# Confidential Information of ARM, Inc.
# Use subject to ARM license.
# Copyright (c) 2025 ARM, Inc.

# ACI Version r1p0

# Reifier 4.0.0

VERSION 5.7 ;

BUSBITCHARS "[]" ;

#name: High Speed Single Port SRAM HVT RVT Compiler | TSMC cln65lp 65nm Process, 0.620um^2 Bit Cell
#version: r1p0
#comment: 
#configuration:  -activity_factor 50 -back_biasing off -bits 32 -bmux off -bus_notation on -check_instname on -diodes on -drive 6 -ema on -frequency 1.0 -instname sp_hse_8192_m16 -left_bus_delim "[" -mux 16 -mvt "" -name_case upper -power_type otc -prefix "" -pwr_gnd_rename vddpe:VDDPE,vddce:VDDCE,vsse:VSSE -retention on -right_bus_delim "]" -rows_p_bl 64 -ser none -site_def off -top_layer m5-m10 -words 8192 -wp_size 1 -write_mask on -write_thru off -corners ff_1p32v_1p32v_125c,ff_1p32v_1p32v_m40c,ss_1p08v_1p08v_125c,ss_1p08v_1p08v_m40c,tt_1p20v_1p20v_25c
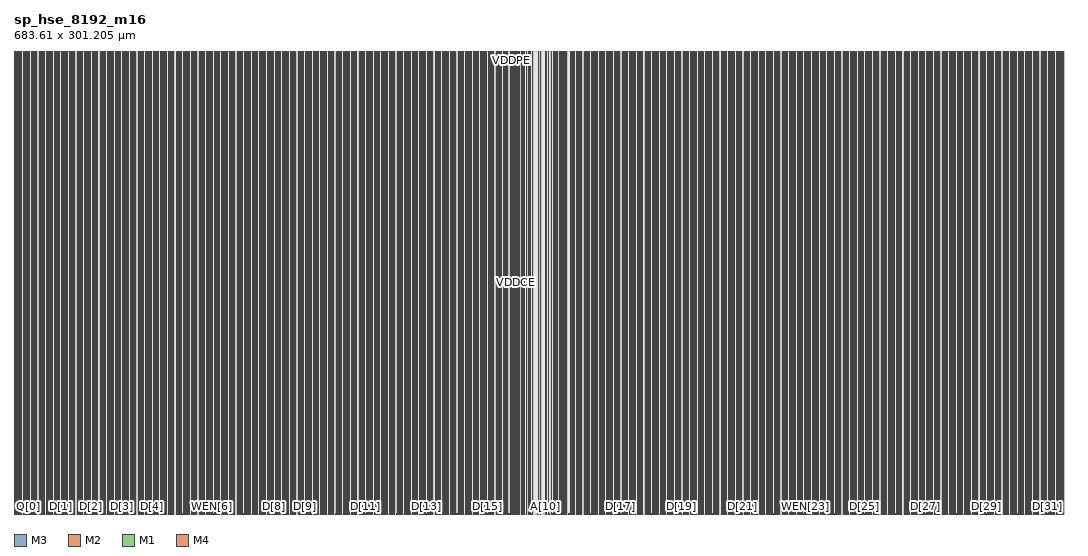
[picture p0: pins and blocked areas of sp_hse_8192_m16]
MACRO sp_hse_8192_m16
  FOREIGN sp_hse_8192_m16 0 0 ;
  SYMMETRY X Y R90 ;
  SIZE 683.61 BY 301.205 ;
  CLASS BLOCK ;
  PIN A[8]
    DIRECTION INPUT ;
    USE SIGNAL ;
    SHAPE ABUTMENT ;
    PORT
      LAYER M3 ;
      RECT 341.26 0.0 341.47 0.38 ;
      LAYER M2 ;
      RECT 341.26 0.0 341.47 0.38 ;
      LAYER M1 ;
      RECT 341.26 0.0 341.47 0.38 ;
      END
    ANTENNAGATEAREA 0.0072 ;
    ANTENNADIFFAREA 0.0737 ;
    END A[8]
  PIN A[9]
    DIRECTION INPUT ;
    USE SIGNAL ;
    SHAPE ABUTMENT ;
    PORT
      LAYER M1 ;
      RECT 345.865 0.0 346.075 0.38 ;
      LAYER M2 ;
      RECT 345.865 0.0 346.075 0.38 ;
      LAYER M3 ;
      RECT 345.865 0.0 346.075 0.38 ;
      END
    ANTENNAGATEAREA 0.0072 ;
    ANTENNADIFFAREA 0.0737 ;
    END A[9]
  PIN A[7]
    DIRECTION INPUT ;
    USE SIGNAL ;
    SHAPE ABUTMENT ;
    PORT
      LAYER M3 ;
      RECT 340.725 0.0 340.935 0.38 ;
      LAYER M2 ;
      RECT 340.725 0.0 340.935 0.38 ;
      LAYER M1 ;
      RECT 340.725 0.0 340.935 0.38 ;
      END
    ANTENNAGATEAREA 0.0072 ;
    ANTENNADIFFAREA 0.0737 ;
    END A[7]
  PIN A[10]
    DIRECTION INPUT ;
    USE SIGNAL ;
    SHAPE ABUTMENT ;
    PORT
      LAYER M1 ;
      RECT 346.245 0.0 346.455 0.38 ;
      LAYER M2 ;
      RECT 346.245 0.0 346.455 0.38 ;
      LAYER M3 ;
      RECT 346.245 0.0 346.455 0.38 ;
      END
    ANTENNAGATEAREA 0.0072 ;
    ANTENNADIFFAREA 0.0737 ;
    END A[10]
  PIN A[6]
    DIRECTION INPUT ;
    USE SIGNAL ;
    SHAPE ABUTMENT ;
    PORT
      LAYER M3 ;
      RECT 336.805 0.0 337.015 0.38 ;
      LAYER M2 ;
      RECT 336.805 0.0 337.015 0.38 ;
      LAYER M1 ;
      RECT 336.805 0.0 337.015 0.38 ;
      END
    ANTENNAGATEAREA 0.0072 ;
    ANTENNADIFFAREA 0.0737 ;
    END A[6]
  PIN A[4]
    DIRECTION INPUT ;
    USE SIGNAL ;
    SHAPE ABUTMENT ;
    PORT
      LAYER M1 ;
      RECT 348.32 0.0 348.53 0.38 ;
      LAYER M2 ;
      RECT 348.32 0.0 348.53 0.38 ;
      LAYER M3 ;
      RECT 348.32 0.0 348.53 0.38 ;
      END
    ANTENNAGATEAREA 0.0072 ;
    ANTENNADIFFAREA 0.0737 ;
    END A[4]
  PIN A[5]
    DIRECTION INPUT ;
    USE SIGNAL ;
    SHAPE ABUTMENT ;
    PORT
      LAYER M3 ;
      RECT 335.97 0.0 336.18 0.38 ;
      LAYER M2 ;
      RECT 335.97 0.0 336.18 0.38 ;
      LAYER M1 ;
      RECT 335.97 0.0 336.18 0.38 ;
      END
    ANTENNAGATEAREA 0.0072 ;
    ANTENNADIFFAREA 0.0737 ;
    END A[5]
  PIN A[11]
    DIRECTION INPUT ;
    USE SIGNAL ;
    SHAPE ABUTMENT ;
    PORT
      LAYER M1 ;
      RECT 350.39 0.0 350.6 0.38 ;
      LAYER M2 ;
      RECT 350.39 0.0 350.6 0.38 ;
      LAYER M3 ;
      RECT 350.39 0.0 350.6 0.38 ;
      END
    ANTENNAGATEAREA 0.0072 ;
    ANTENNADIFFAREA 0.0737 ;
    END A[11]
  PIN GWEN
    DIRECTION INPUT ;
    USE SIGNAL ;
    SHAPE ABUTMENT ;
    PORT
      LAYER M3 ;
      RECT 331.555 0.0 331.765 0.38 ;
      LAYER M2 ;
      RECT 331.555 0.0 331.765 0.38 ;
      LAYER M1 ;
      RECT 331.555 0.0 331.765 0.38 ;
      END
    ANTENNAGATEAREA 0.0072 ;
    ANTENNADIFFAREA 0.0737 ;
    END GWEN
  PIN A[12]
    DIRECTION INPUT ;
    USE SIGNAL ;
    SHAPE ABUTMENT ;
    PORT
      LAYER M1 ;
      RECT 350.985 0.0 351.195 0.38 ;
      LAYER M2 ;
      RECT 350.985 0.0 351.195 0.38 ;
      LAYER M3 ;
      RECT 350.985 0.0 351.195 0.38 ;
      END
    ANTENNAGATEAREA 0.0072 ;
    ANTENNADIFFAREA 0.0737 ;
    END A[12]
  PIN CEN
    DIRECTION INPUT ;
    USE SIGNAL ;
    SHAPE ABUTMENT ;
    PORT
      LAYER M3 ;
      RECT 331.14 0.0 331.35 0.38 ;
      LAYER M2 ;
      RECT 331.14 0.0 331.35 0.38 ;
      LAYER M1 ;
      RECT 331.14 0.0 331.35 0.38 ;
      END
    ANTENNAGATEAREA 0.0072 ;
    ANTENNADIFFAREA 0.0737 ;
    END CEN
  PIN A[3]
    DIRECTION INPUT ;
    USE SIGNAL ;
    SHAPE ABUTMENT ;
    PORT
      LAYER M1 ;
      RECT 354.62 0.0 354.83 0.38 ;
      LAYER M2 ;
      RECT 354.62 0.0 354.83 0.38 ;
      LAYER M3 ;
      RECT 354.62 0.0 354.83 0.38 ;
      END
    ANTENNAGATEAREA 0.0072 ;
    ANTENNADIFFAREA 0.0737 ;
    END A[3]
  PIN CLK
    DIRECTION INPUT ;
    USE SIGNAL ;
    SHAPE ABUTMENT ;
    PORT
      LAYER M4 ;
      RECT 327.685 0.0 327.895 0.38 ;
      LAYER M3 ;
      RECT 327.685 0.0 327.895 0.38 ;
      LAYER M2 ;
      RECT 327.685 0.0 327.895 0.38 ;
      LAYER M1 ;
      RECT 327.685 0.0 327.895 0.38 ;
      END
    ANTENNAGATEAREA 0.0072 ;
    ANTENNADIFFAREA 0.0737 ;
    END CLK
  PIN A[2]
    DIRECTION INPUT ;
    USE SIGNAL ;
    SHAPE ABUTMENT ;
    PORT
      LAYER M1 ;
      RECT 355.8 0.0 356.01 0.38 ;
      LAYER M2 ;
      RECT 355.8 0.0 356.01 0.38 ;
      LAYER M3 ;
      RECT 355.8 0.0 356.01 0.38 ;
      END
    ANTENNAGATEAREA 0.0072 ;
    ANTENNADIFFAREA 0.0737 ;
    END A[2]
  PIN EMAW[1]
    DIRECTION INPUT ;
    USE SIGNAL ;
    SHAPE ABUTMENT ;
    PORT
      LAYER M3 ;
      RECT 326.51 0.0 326.72 0.38 ;
      LAYER M2 ;
      RECT 326.51 0.0 326.72 0.38 ;
      LAYER M1 ;
      RECT 326.51 0.0 326.72 0.38 ;
      END
    ANTENNAGATEAREA 0.0072 ;
    ANTENNADIFFAREA 0.0737 ;
    END EMAW[1]
  PIN A[1]
    DIRECTION INPUT ;
    USE SIGNAL ;
    SHAPE ABUTMENT ;
    PORT
      LAYER M1 ;
      RECT 356.95 0.0 357.16 0.38 ;
      LAYER M2 ;
      RECT 356.95 0.0 357.16 0.38 ;
      LAYER M3 ;
      RECT 356.95 0.0 357.16 0.38 ;
      END
    ANTENNAGATEAREA 0.0072 ;
    ANTENNADIFFAREA 0.0737 ;
    END A[1]
  PIN EMAW[0]
    DIRECTION INPUT ;
    USE SIGNAL ;
    SHAPE ABUTMENT ;
    PORT
      LAYER M3 ;
      RECT 325.285 0.0 325.495 0.38 ;
      LAYER M2 ;
      RECT 325.285 0.0 325.495 0.38 ;
      LAYER M1 ;
      RECT 325.285 0.0 325.495 0.38 ;
      END
    ANTENNAGATEAREA 0.0072 ;
    ANTENNADIFFAREA 0.0737 ;
    END EMAW[0]
  PIN RET1N
    DIRECTION INPUT ;
    USE SIGNAL ;
    SHAPE ABUTMENT ;
    PORT
      LAYER M1 ;
      RECT 358.25 0.0 358.46 0.38 ;
      LAYER M2 ;
      RECT 358.25 0.0 358.46 0.38 ;
      LAYER M3 ;
      RECT 358.25 0.0 358.46 0.38 ;
      END
    ANTENNAGATEAREA 0.0072 ;
    ANTENNADIFFAREA 0.0737 ;
    END RET1N
  PIN EMA[2]
    DIRECTION INPUT ;
    USE SIGNAL ;
    SHAPE ABUTMENT ;
    PORT
      LAYER M3 ;
      RECT 322.23 0.0 322.44 0.38 ;
      LAYER M2 ;
      RECT 322.23 0.0 322.44 0.38 ;
      LAYER M1 ;
      RECT 322.23 0.0 322.44 0.38 ;
      END
    ANTENNAGATEAREA 0.0072 ;
    ANTENNADIFFAREA 0.0737 ;
    END EMA[2]
  PIN EMAS
    DIRECTION INPUT ;
    USE SIGNAL ;
    SHAPE ABUTMENT ;
    PORT
      LAYER M1 ;
      RECT 361.035 0.0 361.245 0.38 ;
      LAYER M2 ;
      RECT 361.035 0.0 361.245 0.38 ;
      LAYER M3 ;
      RECT 361.035 0.0 361.245 0.38 ;
      END
    ANTENNAGATEAREA 0.0072 ;
    ANTENNADIFFAREA 0.0737 ;
    END EMAS
  PIN EMA[1]
    DIRECTION INPUT ;
    USE SIGNAL ;
    SHAPE ABUTMENT ;
    PORT
      LAYER M3 ;
      RECT 321.84 0.0 322.05 0.38 ;
      LAYER M2 ;
      RECT 321.84 0.0 322.05 0.38 ;
      LAYER M1 ;
      RECT 321.84 0.0 322.05 0.38 ;
      END
    ANTENNAGATEAREA 0.0072 ;
    ANTENNADIFFAREA 0.0737 ;
    END EMA[1]
  PIN A[0]
    DIRECTION INPUT ;
    USE SIGNAL ;
    SHAPE ABUTMENT ;
    PORT
      LAYER M1 ;
      RECT 361.455 0.0 361.665 0.38 ;
      LAYER M2 ;
      RECT 361.455 0.0 361.665 0.38 ;
      LAYER M3 ;
      RECT 361.455 0.0 361.665 0.38 ;
      END
    ANTENNAGATEAREA 0.0072 ;
    ANTENNADIFFAREA 0.0737 ;
    END A[0]
  PIN EMA[0]
    DIRECTION INPUT ;
    USE SIGNAL ;
    SHAPE ABUTMENT ;
    PORT
      LAYER M3 ;
      RECT 321.48 0.0 321.69 0.38 ;
      LAYER M2 ;
      RECT 321.48 0.0 321.69 0.38 ;
      LAYER M1 ;
      RECT 321.48 0.0 321.69 0.38 ;
      END
    ANTENNAGATEAREA 0.0072 ;
    ANTENNADIFFAREA 0.0737 ;
    END EMA[0]
  PIN D[16]
    DIRECTION INPUT ;
    USE SIGNAL ;
    SHAPE ABUTMENT ;
    PORT
      LAYER M1 ;
      RECT 375.155 0.0 375.365 0.38 ;
      LAYER M2 ;
      RECT 375.155 0.0 375.365 0.38 ;
      LAYER M3 ;
      RECT 375.155 0.0 375.365 0.38 ;
      END
    ANTENNAGATEAREA 0.0072 ;
    ANTENNADIFFAREA 0.0737 ;
    END D[16]
  PIN D[15]
    DIRECTION INPUT ;
    USE SIGNAL ;
    SHAPE ABUTMENT ;
    PORT
      LAYER M3 ;
      RECT 308.245 0.0 308.455 0.38 ;
      LAYER M2 ;
      RECT 308.245 0.0 308.455 0.38 ;
      LAYER M1 ;
      RECT 308.245 0.0 308.455 0.38 ;
      END
    ANTENNAGATEAREA 0.0072 ;
    ANTENNADIFFAREA 0.0737 ;
    END D[15]
  PIN WEN[16]
    DIRECTION INPUT ;
    USE SIGNAL ;
    SHAPE ABUTMENT ;
    PORT
      LAYER M1 ;
      RECT 376.195 0.0 376.405 0.38 ;
      LAYER M2 ;
      RECT 376.195 0.0 376.405 0.38 ;
      LAYER M3 ;
      RECT 376.195 0.0 376.405 0.38 ;
      END
    ANTENNAGATEAREA 0.0072 ;
    ANTENNADIFFAREA 0.0737 ;
    END WEN[16]
  PIN WEN[15]
    DIRECTION INPUT ;
    USE SIGNAL ;
    SHAPE ABUTMENT ;
    PORT
      LAYER M3 ;
      RECT 307.205 0.0 307.415 0.38 ;
      LAYER M2 ;
      RECT 307.205 0.0 307.415 0.38 ;
      LAYER M1 ;
      RECT 307.205 0.0 307.415 0.38 ;
      END
    ANTENNAGATEAREA 0.0072 ;
    ANTENNADIFFAREA 0.0737 ;
    END WEN[15]
  PIN Q[16]
    DIRECTION OUTPUT ;
    USE SIGNAL ;
    SHAPE ABUTMENT ;
    PORT
      LAYER M1 ;
      RECT 376.545 0.0 376.755 0.38 ;
      LAYER M2 ;
      RECT 376.545 0.0 376.755 0.38 ;
      LAYER M3 ;
      RECT 376.545 0.0 376.755 0.38 ;
      END
    ANTENNADIFFAREA 0.0737 ;
    END Q[16]
  PIN Q[15]
    DIRECTION OUTPUT ;
    USE SIGNAL ;
    SHAPE ABUTMENT ;
    PORT
      LAYER M3 ;
      RECT 306.855 0.0 307.065 0.38 ;
      LAYER M2 ;
      RECT 306.855 0.0 307.065 0.38 ;
      LAYER M1 ;
      RECT 306.855 0.0 307.065 0.38 ;
      END
    ANTENNADIFFAREA 0.0737 ;
    END Q[15]
  PIN D[17]
    DIRECTION INPUT ;
    USE SIGNAL ;
    SHAPE ABUTMENT ;
    PORT
      LAYER M1 ;
      RECT 394.995 0.0 395.205 0.38 ;
      LAYER M2 ;
      RECT 394.995 0.0 395.205 0.38 ;
      LAYER M3 ;
      RECT 394.995 0.0 395.205 0.38 ;
      END
    ANTENNAGATEAREA 0.0072 ;
    ANTENNADIFFAREA 0.0737 ;
    END D[17]
  PIN D[14]
    DIRECTION INPUT ;
    USE SIGNAL ;
    SHAPE ABUTMENT ;
    PORT
      LAYER M3 ;
      RECT 288.405 0.0 288.615 0.38 ;
      LAYER M2 ;
      RECT 288.405 0.0 288.615 0.38 ;
      LAYER M1 ;
      RECT 288.405 0.0 288.615 0.38 ;
      END
    ANTENNAGATEAREA 0.0072 ;
    ANTENNADIFFAREA 0.0737 ;
    END D[14]
  PIN WEN[17]
    DIRECTION INPUT ;
    USE SIGNAL ;
    SHAPE ABUTMENT ;
    PORT
      LAYER M1 ;
      RECT 396.035 0.0 396.245 0.38 ;
      LAYER M2 ;
      RECT 396.035 0.0 396.245 0.38 ;
      LAYER M3 ;
      RECT 396.035 0.0 396.245 0.38 ;
      END
    ANTENNAGATEAREA 0.0072 ;
    ANTENNADIFFAREA 0.0737 ;
    END WEN[17]
  PIN WEN[14]
    DIRECTION INPUT ;
    USE SIGNAL ;
    SHAPE ABUTMENT ;
    PORT
      LAYER M3 ;
      RECT 287.365 0.0 287.575 0.38 ;
      LAYER M2 ;
      RECT 287.365 0.0 287.575 0.38 ;
      LAYER M1 ;
      RECT 287.365 0.0 287.575 0.38 ;
      END
    ANTENNAGATEAREA 0.0072 ;
    ANTENNADIFFAREA 0.0737 ;
    END WEN[14]
  PIN Q[17]
    DIRECTION OUTPUT ;
    USE SIGNAL ;
    SHAPE ABUTMENT ;
    PORT
      LAYER M1 ;
      RECT 396.385 0.0 396.595 0.38 ;
      LAYER M2 ;
      RECT 396.385 0.0 396.595 0.38 ;
      LAYER M3 ;
      RECT 396.385 0.0 396.595 0.38 ;
      END
    ANTENNADIFFAREA 0.0737 ;
    END Q[17]
  PIN Q[14]
    DIRECTION OUTPUT ;
    USE SIGNAL ;
    SHAPE ABUTMENT ;
    PORT
      LAYER M3 ;
      RECT 287.015 0.0 287.225 0.38 ;
      LAYER M2 ;
      RECT 287.015 0.0 287.225 0.38 ;
      LAYER M1 ;
      RECT 287.015 0.0 287.225 0.38 ;
      END
    ANTENNADIFFAREA 0.0737 ;
    END Q[14]
  PIN D[18]
    DIRECTION INPUT ;
    USE SIGNAL ;
    SHAPE ABUTMENT ;
    PORT
      LAYER M1 ;
      RECT 414.835 0.0 415.045 0.38 ;
      LAYER M2 ;
      RECT 414.835 0.0 415.045 0.38 ;
      LAYER M3 ;
      RECT 414.835 0.0 415.045 0.38 ;
      END
    ANTENNAGATEAREA 0.0072 ;
    ANTENNADIFFAREA 0.0737 ;
    END D[18]
  PIN D[13]
    DIRECTION INPUT ;
    USE SIGNAL ;
    SHAPE ABUTMENT ;
    PORT
      LAYER M3 ;
      RECT 268.565 0.0 268.775 0.38 ;
      LAYER M2 ;
      RECT 268.565 0.0 268.775 0.38 ;
      LAYER M1 ;
      RECT 268.565 0.0 268.775 0.38 ;
      END
    ANTENNAGATEAREA 0.0072 ;
    ANTENNADIFFAREA 0.0737 ;
    END D[13]
  PIN WEN[18]
    DIRECTION INPUT ;
    USE SIGNAL ;
    SHAPE ABUTMENT ;
    PORT
      LAYER M1 ;
      RECT 415.875 0.0 416.085 0.38 ;
      LAYER M2 ;
      RECT 415.875 0.0 416.085 0.38 ;
      LAYER M3 ;
      RECT 415.875 0.0 416.085 0.38 ;
      END
    ANTENNAGATEAREA 0.0072 ;
    ANTENNADIFFAREA 0.0737 ;
    END WEN[18]
  PIN WEN[13]
    DIRECTION INPUT ;
    USE SIGNAL ;
    SHAPE ABUTMENT ;
    PORT
      LAYER M3 ;
      RECT 267.525 0.0 267.735 0.38 ;
      LAYER M2 ;
      RECT 267.525 0.0 267.735 0.38 ;
      LAYER M1 ;
      RECT 267.525 0.0 267.735 0.38 ;
      END
    ANTENNAGATEAREA 0.0072 ;
    ANTENNADIFFAREA 0.0737 ;
    END WEN[13]
  PIN Q[18]
    DIRECTION OUTPUT ;
    USE SIGNAL ;
    SHAPE ABUTMENT ;
    PORT
      LAYER M1 ;
      RECT 416.225 0.0 416.435 0.38 ;
      LAYER M2 ;
      RECT 416.225 0.0 416.435 0.38 ;
      LAYER M3 ;
      RECT 416.225 0.0 416.435 0.38 ;
      END
    ANTENNADIFFAREA 0.0737 ;
    END Q[18]
  PIN Q[13]
    DIRECTION OUTPUT ;
    USE SIGNAL ;
    SHAPE ABUTMENT ;
    PORT
      LAYER M3 ;
      RECT 267.175 0.0 267.385 0.38 ;
      LAYER M2 ;
      RECT 267.175 0.0 267.385 0.38 ;
      LAYER M1 ;
      RECT 267.175 0.0 267.385 0.38 ;
      END
    ANTENNADIFFAREA 0.0737 ;
    END Q[13]
  PIN D[19]
    DIRECTION INPUT ;
    USE SIGNAL ;
    SHAPE ABUTMENT ;
    PORT
      LAYER M1 ;
      RECT 434.675 0.0 434.885 0.38 ;
      LAYER M2 ;
      RECT 434.675 0.0 434.885 0.38 ;
      LAYER M3 ;
      RECT 434.675 0.0 434.885 0.38 ;
      END
    ANTENNAGATEAREA 0.0072 ;
    ANTENNADIFFAREA 0.0737 ;
    END D[19]
  PIN D[12]
    DIRECTION INPUT ;
    USE SIGNAL ;
    SHAPE ABUTMENT ;
    PORT
      LAYER M3 ;
      RECT 248.725 0.0 248.935 0.38 ;
      LAYER M2 ;
      RECT 248.725 0.0 248.935 0.38 ;
      LAYER M1 ;
      RECT 248.725 0.0 248.935 0.38 ;
      END
    ANTENNAGATEAREA 0.0072 ;
    ANTENNADIFFAREA 0.0737 ;
    END D[12]
  PIN WEN[19]
    DIRECTION INPUT ;
    USE SIGNAL ;
    SHAPE ABUTMENT ;
    PORT
      LAYER M1 ;
      RECT 435.715 0.0 435.925 0.38 ;
      LAYER M2 ;
      RECT 435.715 0.0 435.925 0.38 ;
      LAYER M3 ;
      RECT 435.715 0.0 435.925 0.38 ;
      END
    ANTENNAGATEAREA 0.0072 ;
    ANTENNADIFFAREA 0.0737 ;
    END WEN[19]
  PIN WEN[12]
    DIRECTION INPUT ;
    USE SIGNAL ;
    SHAPE ABUTMENT ;
    PORT
      LAYER M3 ;
      RECT 247.685 0.0 247.895 0.38 ;
      LAYER M2 ;
      RECT 247.685 0.0 247.895 0.38 ;
      LAYER M1 ;
      RECT 247.685 0.0 247.895 0.38 ;
      END
    ANTENNAGATEAREA 0.0072 ;
    ANTENNADIFFAREA 0.0737 ;
    END WEN[12]
  PIN Q[19]
    DIRECTION OUTPUT ;
    USE SIGNAL ;
    SHAPE ABUTMENT ;
    PORT
      LAYER M1 ;
      RECT 436.065 0.0 436.275 0.38 ;
      LAYER M2 ;
      RECT 436.065 0.0 436.275 0.38 ;
      LAYER M3 ;
      RECT 436.065 0.0 436.275 0.38 ;
      END
    ANTENNADIFFAREA 0.0737 ;
    END Q[19]
  PIN Q[12]
    DIRECTION OUTPUT ;
    USE SIGNAL ;
    SHAPE ABUTMENT ;
    PORT
      LAYER M3 ;
      RECT 247.335 0.0 247.545 0.38 ;
      LAYER M2 ;
      RECT 247.335 0.0 247.545 0.38 ;
      LAYER M1 ;
      RECT 247.335 0.0 247.545 0.38 ;
      END
    ANTENNADIFFAREA 0.0737 ;
    END Q[12]
  PIN D[20]
    DIRECTION INPUT ;
    USE SIGNAL ;
    SHAPE ABUTMENT ;
    PORT
      LAYER M1 ;
      RECT 454.515 0.0 454.725 0.38 ;
      LAYER M2 ;
      RECT 454.515 0.0 454.725 0.38 ;
      LAYER M3 ;
      RECT 454.515 0.0 454.725 0.38 ;
      END
    ANTENNAGATEAREA 0.0072 ;
    ANTENNADIFFAREA 0.0737 ;
    END D[20]
  PIN D[11]
    DIRECTION INPUT ;
    USE SIGNAL ;
    SHAPE ABUTMENT ;
    PORT
      LAYER M3 ;
      RECT 228.885 0.0 229.095 0.38 ;
      LAYER M2 ;
      RECT 228.885 0.0 229.095 0.38 ;
      LAYER M1 ;
      RECT 228.885 0.0 229.095 0.38 ;
      END
    ANTENNAGATEAREA 0.0072 ;
    ANTENNADIFFAREA 0.0737 ;
    END D[11]
  PIN WEN[20]
    DIRECTION INPUT ;
    USE SIGNAL ;
    SHAPE ABUTMENT ;
    PORT
      LAYER M1 ;
      RECT 455.555 0.0 455.765 0.38 ;
      LAYER M2 ;
      RECT 455.555 0.0 455.765 0.38 ;
      LAYER M3 ;
      RECT 455.555 0.0 455.765 0.38 ;
      END
    ANTENNAGATEAREA 0.0072 ;
    ANTENNADIFFAREA 0.0737 ;
    END WEN[20]
  PIN WEN[11]
    DIRECTION INPUT ;
    USE SIGNAL ;
    SHAPE ABUTMENT ;
    PORT
      LAYER M3 ;
      RECT 227.845 0.0 228.055 0.38 ;
      LAYER M2 ;
      RECT 227.845 0.0 228.055 0.38 ;
      LAYER M1 ;
      RECT 227.845 0.0 228.055 0.38 ;
      END
    ANTENNAGATEAREA 0.0072 ;
    ANTENNADIFFAREA 0.0737 ;
    END WEN[11]
  PIN Q[20]
    DIRECTION OUTPUT ;
    USE SIGNAL ;
    SHAPE ABUTMENT ;
    PORT
      LAYER M1 ;
      RECT 455.905 0.0 456.115 0.38 ;
      LAYER M2 ;
      RECT 455.905 0.0 456.115 0.38 ;
      LAYER M3 ;
      RECT 455.905 0.0 456.115 0.38 ;
      END
    ANTENNADIFFAREA 0.0737 ;
    END Q[20]
  PIN Q[11]
    DIRECTION OUTPUT ;
    USE SIGNAL ;
    SHAPE ABUTMENT ;
    PORT
      LAYER M3 ;
      RECT 227.495 0.0 227.705 0.38 ;
      LAYER M2 ;
      RECT 227.495 0.0 227.705 0.38 ;
      LAYER M1 ;
      RECT 227.495 0.0 227.705 0.38 ;
      END
    ANTENNADIFFAREA 0.0737 ;
    END Q[11]
  PIN D[21]
    DIRECTION INPUT ;
    USE SIGNAL ;
    SHAPE ABUTMENT ;
    PORT
      LAYER M1 ;
      RECT 474.355 0.0 474.565 0.38 ;
      LAYER M2 ;
      RECT 474.355 0.0 474.565 0.38 ;
      LAYER M3 ;
      RECT 474.355 0.0 474.565 0.38 ;
      END
    ANTENNAGATEAREA 0.0072 ;
    ANTENNADIFFAREA 0.0737 ;
    END D[21]
  PIN D[10]
    DIRECTION INPUT ;
    USE SIGNAL ;
    SHAPE ABUTMENT ;
    PORT
      LAYER M3 ;
      RECT 209.045 0.0 209.255 0.38 ;
      LAYER M2 ;
      RECT 209.045 0.0 209.255 0.38 ;
      LAYER M1 ;
      RECT 209.045 0.0 209.255 0.38 ;
      END
    ANTENNAGATEAREA 0.0072 ;
    ANTENNADIFFAREA 0.0737 ;
    END D[10]
  PIN WEN[21]
    DIRECTION INPUT ;
    USE SIGNAL ;
    SHAPE ABUTMENT ;
    PORT
      LAYER M1 ;
      RECT 475.395 0.0 475.605 0.38 ;
      LAYER M2 ;
      RECT 475.395 0.0 475.605 0.38 ;
      LAYER M3 ;
      RECT 475.395 0.0 475.605 0.38 ;
      END
    ANTENNAGATEAREA 0.0072 ;
    ANTENNADIFFAREA 0.0737 ;
    END WEN[21]
  PIN WEN[10]
    DIRECTION INPUT ;
    USE SIGNAL ;
    SHAPE ABUTMENT ;
    PORT
      LAYER M3 ;
      RECT 208.005 0.0 208.215 0.38 ;
      LAYER M2 ;
      RECT 208.005 0.0 208.215 0.38 ;
      LAYER M1 ;
      RECT 208.005 0.0 208.215 0.38 ;
      END
    ANTENNAGATEAREA 0.0072 ;
    ANTENNADIFFAREA 0.0737 ;
    END WEN[10]
  PIN Q[21]
    DIRECTION OUTPUT ;
    USE SIGNAL ;
    SHAPE ABUTMENT ;
    PORT
      LAYER M1 ;
      RECT 475.745 0.0 475.955 0.38 ;
      LAYER M2 ;
      RECT 475.745 0.0 475.955 0.38 ;
      LAYER M3 ;
      RECT 475.745 0.0 475.955 0.38 ;
      END
    ANTENNADIFFAREA 0.0737 ;
    END Q[21]
  PIN Q[10]
    DIRECTION OUTPUT ;
    USE SIGNAL ;
    SHAPE ABUTMENT ;
    PORT
      LAYER M3 ;
      RECT 207.655 0.0 207.865 0.38 ;
      LAYER M2 ;
      RECT 207.655 0.0 207.865 0.38 ;
      LAYER M1 ;
      RECT 207.655 0.0 207.865 0.38 ;
      END
    ANTENNADIFFAREA 0.0737 ;
    END Q[10]
  PIN D[22]
    DIRECTION INPUT ;
    USE SIGNAL ;
    SHAPE ABUTMENT ;
    PORT
      LAYER M1 ;
      RECT 494.195 0.0 494.405 0.38 ;
      LAYER M2 ;
      RECT 494.195 0.0 494.405 0.38 ;
      LAYER M3 ;
      RECT 494.195 0.0 494.405 0.38 ;
      END
    ANTENNAGATEAREA 0.0072 ;
    ANTENNADIFFAREA 0.0737 ;
    END D[22]
  PIN D[9]
    DIRECTION INPUT ;
    USE SIGNAL ;
    SHAPE ABUTMENT ;
    PORT
      LAYER M3 ;
      RECT 189.205 0.0 189.415 0.38 ;
      LAYER M2 ;
      RECT 189.205 0.0 189.415 0.38 ;
      LAYER M1 ;
      RECT 189.205 0.0 189.415 0.38 ;
      END
    ANTENNAGATEAREA 0.0072 ;
    ANTENNADIFFAREA 0.0737 ;
    END D[9]
  PIN WEN[22]
    DIRECTION INPUT ;
    USE SIGNAL ;
    SHAPE ABUTMENT ;
    PORT
      LAYER M1 ;
      RECT 495.235 0.0 495.445 0.38 ;
      LAYER M2 ;
      RECT 495.235 0.0 495.445 0.38 ;
      LAYER M3 ;
      RECT 495.235 0.0 495.445 0.38 ;
      END
    ANTENNAGATEAREA 0.0072 ;
    ANTENNADIFFAREA 0.0737 ;
    END WEN[22]
  PIN WEN[9]
    DIRECTION INPUT ;
    USE SIGNAL ;
    SHAPE ABUTMENT ;
    PORT
      LAYER M3 ;
      RECT 188.165 0.0 188.375 0.38 ;
      LAYER M2 ;
      RECT 188.165 0.0 188.375 0.38 ;
      LAYER M1 ;
      RECT 188.165 0.0 188.375 0.38 ;
      END
    ANTENNAGATEAREA 0.0072 ;
    ANTENNADIFFAREA 0.0737 ;
    END WEN[9]
  PIN Q[22]
    DIRECTION OUTPUT ;
    USE SIGNAL ;
    SHAPE ABUTMENT ;
    PORT
      LAYER M1 ;
      RECT 495.585 0.0 495.795 0.38 ;
      LAYER M2 ;
      RECT 495.585 0.0 495.795 0.38 ;
      LAYER M3 ;
      RECT 495.585 0.0 495.795 0.38 ;
      END
    ANTENNADIFFAREA 0.0737 ;
    END Q[22]
  PIN Q[9]
    DIRECTION OUTPUT ;
    USE SIGNAL ;
    SHAPE ABUTMENT ;
    PORT
      LAYER M3 ;
      RECT 187.815 0.0 188.025 0.38 ;
      LAYER M2 ;
      RECT 187.815 0.0 188.025 0.38 ;
      LAYER M1 ;
      RECT 187.815 0.0 188.025 0.38 ;
      END
    ANTENNADIFFAREA 0.0737 ;
    END Q[9]
  PIN D[23]
    DIRECTION INPUT ;
    USE SIGNAL ;
    SHAPE ABUTMENT ;
    PORT
      LAYER M1 ;
      RECT 514.035 0.0 514.245 0.38 ;
      LAYER M2 ;
      RECT 514.035 0.0 514.245 0.38 ;
      LAYER M3 ;
      RECT 514.035 0.0 514.245 0.38 ;
      END
    ANTENNAGATEAREA 0.0072 ;
    ANTENNADIFFAREA 0.0737 ;
    END D[23]
  PIN D[8]
    DIRECTION INPUT ;
    USE SIGNAL ;
    SHAPE ABUTMENT ;
    PORT
      LAYER M3 ;
      RECT 169.365 0.0 169.575 0.38 ;
      LAYER M2 ;
      RECT 169.365 0.0 169.575 0.38 ;
      LAYER M1 ;
      RECT 169.365 0.0 169.575 0.38 ;
      END
    ANTENNAGATEAREA 0.0072 ;
    ANTENNADIFFAREA 0.0737 ;
    END D[8]
  PIN WEN[23]
    DIRECTION INPUT ;
    USE SIGNAL ;
    SHAPE ABUTMENT ;
    PORT
      LAYER M1 ;
      RECT 515.075 0.0 515.285 0.38 ;
      LAYER M2 ;
      RECT 515.075 0.0 515.285 0.38 ;
      LAYER M3 ;
      RECT 515.075 0.0 515.285 0.38 ;
      END
    ANTENNAGATEAREA 0.0072 ;
    ANTENNADIFFAREA 0.0737 ;
    END WEN[23]
  PIN WEN[8]
    DIRECTION INPUT ;
    USE SIGNAL ;
    SHAPE ABUTMENT ;
    PORT
      LAYER M3 ;
      RECT 168.325 0.0 168.535 0.38 ;
      LAYER M2 ;
      RECT 168.325 0.0 168.535 0.38 ;
      LAYER M1 ;
      RECT 168.325 0.0 168.535 0.38 ;
      END
    ANTENNAGATEAREA 0.0072 ;
    ANTENNADIFFAREA 0.0737 ;
    END WEN[8]
  PIN Q[23]
    DIRECTION OUTPUT ;
    USE SIGNAL ;
    SHAPE ABUTMENT ;
    PORT
      LAYER M1 ;
      RECT 515.425 0.0 515.635 0.38 ;
      LAYER M2 ;
      RECT 515.425 0.0 515.635 0.38 ;
      LAYER M3 ;
      RECT 515.425 0.0 515.635 0.38 ;
      END
    ANTENNADIFFAREA 0.0737 ;
    END Q[23]
  PIN Q[8]
    DIRECTION OUTPUT ;
    USE SIGNAL ;
    SHAPE ABUTMENT ;
    PORT
      LAYER M3 ;
      RECT 167.975 0.0 168.185 0.38 ;
      LAYER M2 ;
      RECT 167.975 0.0 168.185 0.38 ;
      LAYER M1 ;
      RECT 167.975 0.0 168.185 0.38 ;
      END
    ANTENNADIFFAREA 0.0737 ;
    END Q[8]
  PIN D[24]
    DIRECTION INPUT ;
    USE SIGNAL ;
    SHAPE ABUTMENT ;
    PORT
      LAYER M1 ;
      RECT 533.875 0.0 534.085 0.38 ;
      LAYER M2 ;
      RECT 533.875 0.0 534.085 0.38 ;
      LAYER M3 ;
      RECT 533.875 0.0 534.085 0.38 ;
      END
    ANTENNAGATEAREA 0.0072 ;
    ANTENNADIFFAREA 0.0737 ;
    END D[24]
  PIN D[7]
    DIRECTION INPUT ;
    USE SIGNAL ;
    SHAPE ABUTMENT ;
    PORT
      LAYER M3 ;
      RECT 149.525 0.0 149.735 0.38 ;
      LAYER M2 ;
      RECT 149.525 0.0 149.735 0.38 ;
      LAYER M1 ;
      RECT 149.525 0.0 149.735 0.38 ;
      END
    ANTENNAGATEAREA 0.0072 ;
    ANTENNADIFFAREA 0.0737 ;
    END D[7]
  PIN WEN[24]
    DIRECTION INPUT ;
    USE SIGNAL ;
    SHAPE ABUTMENT ;
    PORT
      LAYER M1 ;
      RECT 534.915 0.0 535.125 0.38 ;
      LAYER M2 ;
      RECT 534.915 0.0 535.125 0.38 ;
      LAYER M3 ;
      RECT 534.915 0.0 535.125 0.38 ;
      END
    ANTENNAGATEAREA 0.0072 ;
    ANTENNADIFFAREA 0.0737 ;
    END WEN[24]
  PIN WEN[7]
    DIRECTION INPUT ;
    USE SIGNAL ;
    SHAPE ABUTMENT ;
    PORT
      LAYER M3 ;
      RECT 148.485 0.0 148.695 0.38 ;
      LAYER M2 ;
      RECT 148.485 0.0 148.695 0.38 ;
      LAYER M1 ;
      RECT 148.485 0.0 148.695 0.38 ;
      END
    ANTENNAGATEAREA 0.0072 ;
    ANTENNADIFFAREA 0.0737 ;
    END WEN[7]
  PIN Q[24]
    DIRECTION OUTPUT ;
    USE SIGNAL ;
    SHAPE ABUTMENT ;
    PORT
      LAYER M1 ;
      RECT 535.265 0.0 535.475 0.38 ;
      LAYER M2 ;
      RECT 535.265 0.0 535.475 0.38 ;
      LAYER M3 ;
      RECT 535.265 0.0 535.475 0.38 ;
      END
    ANTENNADIFFAREA 0.0737 ;
    END Q[24]
  PIN Q[7]
    DIRECTION OUTPUT ;
    USE SIGNAL ;
    SHAPE ABUTMENT ;
    PORT
      LAYER M3 ;
      RECT 148.135 0.0 148.345 0.38 ;
      LAYER M2 ;
      RECT 148.135 0.0 148.345 0.38 ;
      LAYER M1 ;
      RECT 148.135 0.0 148.345 0.38 ;
      END
    ANTENNADIFFAREA 0.0737 ;
    END Q[7]
  PIN D[25]
    DIRECTION INPUT ;
    USE SIGNAL ;
    SHAPE ABUTMENT ;
    PORT
      LAYER M1 ;
      RECT 553.715 0.0 553.925 0.38 ;
      LAYER M2 ;
      RECT 553.715 0.0 553.925 0.38 ;
      LAYER M3 ;
      RECT 553.715 0.0 553.925 0.38 ;
      END
    ANTENNAGATEAREA 0.0072 ;
    ANTENNADIFFAREA 0.0737 ;
    END D[25]
  PIN D[6]
    DIRECTION INPUT ;
    USE SIGNAL ;
    SHAPE ABUTMENT ;
    PORT
      LAYER M3 ;
      RECT 129.685 0.0 129.895 0.38 ;
      LAYER M2 ;
      RECT 129.685 0.0 129.895 0.38 ;
      LAYER M1 ;
      RECT 129.685 0.0 129.895 0.38 ;
      END
    ANTENNAGATEAREA 0.0072 ;
    ANTENNADIFFAREA 0.0737 ;
    END D[6]
  PIN WEN[25]
    DIRECTION INPUT ;
    USE SIGNAL ;
    SHAPE ABUTMENT ;
    PORT
      LAYER M1 ;
      RECT 554.755 0.0 554.965 0.38 ;
      LAYER M2 ;
      RECT 554.755 0.0 554.965 0.38 ;
      LAYER M3 ;
      RECT 554.755 0.0 554.965 0.38 ;
      END
    ANTENNAGATEAREA 0.0072 ;
    ANTENNADIFFAREA 0.0737 ;
    END WEN[25]
  PIN WEN[6]
    DIRECTION INPUT ;
    USE SIGNAL ;
    SHAPE ABUTMENT ;
    PORT
      LAYER M3 ;
      RECT 128.645 0.0 128.855 0.38 ;
      LAYER M2 ;
      RECT 128.645 0.0 128.855 0.38 ;
      LAYER M1 ;
      RECT 128.645 0.0 128.855 0.38 ;
      END
    ANTENNAGATEAREA 0.0072 ;
    ANTENNADIFFAREA 0.0737 ;
    END WEN[6]
  PIN Q[25]
    DIRECTION OUTPUT ;
    USE SIGNAL ;
    SHAPE ABUTMENT ;
    PORT
      LAYER M1 ;
      RECT 555.105 0.0 555.315 0.38 ;
      LAYER M2 ;
      RECT 555.105 0.0 555.315 0.38 ;
      LAYER M3 ;
      RECT 555.105 0.0 555.315 0.38 ;
      END
    ANTENNADIFFAREA 0.0737 ;
    END Q[25]
  PIN Q[6]
    DIRECTION OUTPUT ;
    USE SIGNAL ;
    SHAPE ABUTMENT ;
    PORT
      LAYER M3 ;
      RECT 128.295 0.0 128.505 0.38 ;
      LAYER M2 ;
      RECT 128.295 0.0 128.505 0.38 ;
      LAYER M1 ;
      RECT 128.295 0.0 128.505 0.38 ;
      END
    ANTENNADIFFAREA 0.0737 ;
    END Q[6]
  PIN D[26]
    DIRECTION INPUT ;
    USE SIGNAL ;
    SHAPE ABUTMENT ;
    PORT
      LAYER M1 ;
      RECT 573.555 0.0 573.765 0.38 ;
      LAYER M2 ;
      RECT 573.555 0.0 573.765 0.38 ;
      LAYER M3 ;
      RECT 573.555 0.0 573.765 0.38 ;
      END
    ANTENNAGATEAREA 0.0072 ;
    ANTENNADIFFAREA 0.0737 ;
    END D[26]
  PIN D[5]
    DIRECTION INPUT ;
    USE SIGNAL ;
    SHAPE ABUTMENT ;
    PORT
      LAYER M3 ;
      RECT 109.845 0.0 110.055 0.38 ;
      LAYER M2 ;
      RECT 109.845 0.0 110.055 0.38 ;
      LAYER M1 ;
      RECT 109.845 0.0 110.055 0.38 ;
      END
    ANTENNAGATEAREA 0.0072 ;
    ANTENNADIFFAREA 0.0737 ;
    END D[5]
  PIN WEN[26]
    DIRECTION INPUT ;
    USE SIGNAL ;
    SHAPE ABUTMENT ;
    PORT
      LAYER M1 ;
      RECT 574.595 0.0 574.805 0.38 ;
      LAYER M2 ;
      RECT 574.595 0.0 574.805 0.38 ;
      LAYER M3 ;
      RECT 574.595 0.0 574.805 0.38 ;
      END
    ANTENNAGATEAREA 0.0072 ;
    ANTENNADIFFAREA 0.0737 ;
    END WEN[26]
  PIN WEN[5]
    DIRECTION INPUT ;
    USE SIGNAL ;
    SHAPE ABUTMENT ;
    PORT
      LAYER M3 ;
      RECT 108.805 0.0 109.015 0.38 ;
      LAYER M2 ;
      RECT 108.805 0.0 109.015 0.38 ;
      LAYER M1 ;
      RECT 108.805 0.0 109.015 0.38 ;
      END
    ANTENNAGATEAREA 0.0072 ;
    ANTENNADIFFAREA 0.0737 ;
    END WEN[5]
  PIN Q[26]
    DIRECTION OUTPUT ;
    USE SIGNAL ;
    SHAPE ABUTMENT ;
    PORT
      LAYER M1 ;
      RECT 574.945 0.0 575.155 0.38 ;
      LAYER M2 ;
      RECT 574.945 0.0 575.155 0.38 ;
      LAYER M3 ;
      RECT 574.945 0.0 575.155 0.38 ;
      END
    ANTENNADIFFAREA 0.0737 ;
    END Q[26]
  PIN Q[5]
    DIRECTION OUTPUT ;
    USE SIGNAL ;
    SHAPE ABUTMENT ;
    PORT
      LAYER M3 ;
      RECT 108.455 0.0 108.665 0.38 ;
      LAYER M2 ;
      RECT 108.455 0.0 108.665 0.38 ;
      LAYER M1 ;
      RECT 108.455 0.0 108.665 0.38 ;
      END
    ANTENNADIFFAREA 0.0737 ;
    END Q[5]
  PIN D[27]
    DIRECTION INPUT ;
    USE SIGNAL ;
    SHAPE ABUTMENT ;
    PORT
      LAYER M1 ;
      RECT 593.395 0.0 593.605 0.38 ;
      LAYER M2 ;
      RECT 593.395 0.0 593.605 0.38 ;
      LAYER M3 ;
      RECT 593.395 0.0 593.605 0.38 ;
      END
    ANTENNAGATEAREA 0.0072 ;
    ANTENNADIFFAREA 0.0737 ;
    END D[27]
  PIN D[4]
    DIRECTION INPUT ;
    USE SIGNAL ;
    SHAPE ABUTMENT ;
    PORT
      LAYER M3 ;
      RECT 90.005 0.0 90.215 0.38 ;
      LAYER M2 ;
      RECT 90.005 0.0 90.215 0.38 ;
      LAYER M1 ;
      RECT 90.005 0.0 90.215 0.38 ;
      END
    ANTENNAGATEAREA 0.0072 ;
    ANTENNADIFFAREA 0.0737 ;
    END D[4]
  PIN WEN[27]
    DIRECTION INPUT ;
    USE SIGNAL ;
    SHAPE ABUTMENT ;
    PORT
      LAYER M1 ;
      RECT 594.435 0.0 594.645 0.38 ;
      LAYER M2 ;
      RECT 594.435 0.0 594.645 0.38 ;
      LAYER M3 ;
      RECT 594.435 0.0 594.645 0.38 ;
      END
    ANTENNAGATEAREA 0.0072 ;
    ANTENNADIFFAREA 0.0737 ;
    END WEN[27]
  PIN WEN[4]
    DIRECTION INPUT ;
    USE SIGNAL ;
    SHAPE ABUTMENT ;
    PORT
      LAYER M3 ;
      RECT 88.965 0.0 89.175 0.38 ;
      LAYER M2 ;
      RECT 88.965 0.0 89.175 0.38 ;
      LAYER M1 ;
      RECT 88.965 0.0 89.175 0.38 ;
      END
    ANTENNAGATEAREA 0.0072 ;
    ANTENNADIFFAREA 0.0737 ;
    END WEN[4]
  PIN Q[27]
    DIRECTION OUTPUT ;
    USE SIGNAL ;
    SHAPE ABUTMENT ;
    PORT
      LAYER M1 ;
      RECT 594.785 0.0 594.995 0.38 ;
      LAYER M2 ;
      RECT 594.785 0.0 594.995 0.38 ;
      LAYER M3 ;
      RECT 594.785 0.0 594.995 0.38 ;
      END
    ANTENNADIFFAREA 0.0737 ;
    END Q[27]
  PIN Q[4]
    DIRECTION OUTPUT ;
    USE SIGNAL ;
    SHAPE ABUTMENT ;
    PORT
      LAYER M3 ;
      RECT 88.615 0.0 88.825 0.38 ;
      LAYER M2 ;
      RECT 88.615 0.0 88.825 0.38 ;
      LAYER M1 ;
      RECT 88.615 0.0 88.825 0.38 ;
      END
    ANTENNADIFFAREA 0.0737 ;
    END Q[4]
  PIN D[28]
    DIRECTION INPUT ;
    USE SIGNAL ;
    SHAPE ABUTMENT ;
    PORT
      LAYER M1 ;
      RECT 613.235 0.0 613.445 0.38 ;
      LAYER M2 ;
      RECT 613.235 0.0 613.445 0.38 ;
      LAYER M3 ;
      RECT 613.235 0.0 613.445 0.38 ;
      END
    ANTENNAGATEAREA 0.0072 ;
    ANTENNADIFFAREA 0.0737 ;
    END D[28]
  PIN D[3]
    DIRECTION INPUT ;
    USE SIGNAL ;
    SHAPE ABUTMENT ;
    PORT
      LAYER M3 ;
      RECT 70.165 0.0 70.375 0.38 ;
      LAYER M2 ;
      RECT 70.165 0.0 70.375 0.38 ;
      LAYER M1 ;
      RECT 70.165 0.0 70.375 0.38 ;
      END
    ANTENNAGATEAREA 0.0072 ;
    ANTENNADIFFAREA 0.0737 ;
    END D[3]
  PIN WEN[28]
    DIRECTION INPUT ;
    USE SIGNAL ;
    SHAPE ABUTMENT ;
    PORT
      LAYER M1 ;
      RECT 614.275 0.0 614.485 0.38 ;
      LAYER M2 ;
      RECT 614.275 0.0 614.485 0.38 ;
      LAYER M3 ;
      RECT 614.275 0.0 614.485 0.38 ;
      END
    ANTENNAGATEAREA 0.0072 ;
    ANTENNADIFFAREA 0.0737 ;
    END WEN[28]
  PIN WEN[3]
    DIRECTION INPUT ;
    USE SIGNAL ;
    SHAPE ABUTMENT ;
    PORT
      LAYER M3 ;
      RECT 69.125 0.0 69.335 0.38 ;
      LAYER M2 ;
      RECT 69.125 0.0 69.335 0.38 ;
      LAYER M1 ;
      RECT 69.125 0.0 69.335 0.38 ;
      END
    ANTENNAGATEAREA 0.0072 ;
    ANTENNADIFFAREA 0.0737 ;
    END WEN[3]
  PIN Q[28]
    DIRECTION OUTPUT ;
    USE SIGNAL ;
    SHAPE ABUTMENT ;
    PORT
      LAYER M1 ;
      RECT 614.625 0.0 614.835 0.38 ;
      LAYER M2 ;
      RECT 614.625 0.0 614.835 0.38 ;
      LAYER M3 ;
      RECT 614.625 0.0 614.835 0.38 ;
      END
    ANTENNADIFFAREA 0.0737 ;
    END Q[28]
  PIN Q[3]
    DIRECTION OUTPUT ;
    USE SIGNAL ;
    SHAPE ABUTMENT ;
    PORT
      LAYER M3 ;
      RECT 68.775 0.0 68.985 0.38 ;
      LAYER M2 ;
      RECT 68.775 0.0 68.985 0.38 ;
      LAYER M1 ;
      RECT 68.775 0.0 68.985 0.38 ;
      END
    ANTENNADIFFAREA 0.0737 ;
    END Q[3]
  PIN D[29]
    DIRECTION INPUT ;
    USE SIGNAL ;
    SHAPE ABUTMENT ;
    PORT
      LAYER M1 ;
      RECT 633.075 0.0 633.285 0.38 ;
      LAYER M2 ;
      RECT 633.075 0.0 633.285 0.38 ;
      LAYER M3 ;
      RECT 633.075 0.0 633.285 0.38 ;
      END
    ANTENNAGATEAREA 0.0072 ;
    ANTENNADIFFAREA 0.0737 ;
    END D[29]
  PIN D[2]
    DIRECTION INPUT ;
    USE SIGNAL ;
    SHAPE ABUTMENT ;
    PORT
      LAYER M3 ;
      RECT 50.325 0.0 50.535 0.38 ;
      LAYER M2 ;
      RECT 50.325 0.0 50.535 0.38 ;
      LAYER M1 ;
      RECT 50.325 0.0 50.535 0.38 ;
      END
    ANTENNAGATEAREA 0.0072 ;
    ANTENNADIFFAREA 0.0737 ;
    END D[2]
  PIN WEN[29]
    DIRECTION INPUT ;
    USE SIGNAL ;
    SHAPE ABUTMENT ;
    PORT
      LAYER M1 ;
      RECT 634.115 0.0 634.325 0.38 ;
      LAYER M2 ;
      RECT 634.115 0.0 634.325 0.38 ;
      LAYER M3 ;
      RECT 634.115 0.0 634.325 0.38 ;
      END
    ANTENNAGATEAREA 0.0072 ;
    ANTENNADIFFAREA 0.0737 ;
    END WEN[29]
  PIN WEN[2]
    DIRECTION INPUT ;
    USE SIGNAL ;
    SHAPE ABUTMENT ;
    PORT
      LAYER M3 ;
      RECT 49.285 0.0 49.495 0.38 ;
      LAYER M2 ;
      RECT 49.285 0.0 49.495 0.38 ;
      LAYER M1 ;
      RECT 49.285 0.0 49.495 0.38 ;
      END
    ANTENNAGATEAREA 0.0072 ;
    ANTENNADIFFAREA 0.0737 ;
    END WEN[2]
  PIN Q[29]
    DIRECTION OUTPUT ;
    USE SIGNAL ;
    SHAPE ABUTMENT ;
    PORT
      LAYER M1 ;
      RECT 634.465 0.0 634.675 0.38 ;
      LAYER M2 ;
      RECT 634.465 0.0 634.675 0.38 ;
      LAYER M3 ;
      RECT 634.465 0.0 634.675 0.38 ;
      END
    ANTENNADIFFAREA 0.0737 ;
    END Q[29]
  PIN Q[2]
    DIRECTION OUTPUT ;
    USE SIGNAL ;
    SHAPE ABUTMENT ;
    PORT
      LAYER M3 ;
      RECT 48.935 0.0 49.145 0.38 ;
      LAYER M2 ;
      RECT 48.935 0.0 49.145 0.38 ;
      LAYER M1 ;
      RECT 48.935 0.0 49.145 0.38 ;
      END
    ANTENNADIFFAREA 0.0737 ;
    END Q[2]
  PIN D[30]
    DIRECTION INPUT ;
    USE SIGNAL ;
    SHAPE ABUTMENT ;
    PORT
      LAYER M1 ;
      RECT 652.915 0.0 653.125 0.38 ;
      LAYER M2 ;
      RECT 652.915 0.0 653.125 0.38 ;
      LAYER M3 ;
      RECT 652.915 0.0 653.125 0.38 ;
      END
    ANTENNAGATEAREA 0.0072 ;
    ANTENNADIFFAREA 0.0737 ;
    END D[30]
  PIN D[1]
    DIRECTION INPUT ;
    USE SIGNAL ;
    SHAPE ABUTMENT ;
    PORT
      LAYER M3 ;
      RECT 30.485 0.0 30.695 0.38 ;
      LAYER M2 ;
      RECT 30.485 0.0 30.695 0.38 ;
      LAYER M1 ;
      RECT 30.485 0.0 30.695 0.38 ;
      END
    ANTENNAGATEAREA 0.0072 ;
    ANTENNADIFFAREA 0.0737 ;
    END D[1]
  PIN WEN[30]
    DIRECTION INPUT ;
    USE SIGNAL ;
    SHAPE ABUTMENT ;
    PORT
      LAYER M1 ;
      RECT 653.955 0.0 654.165 0.38 ;
      LAYER M2 ;
      RECT 653.955 0.0 654.165 0.38 ;
      LAYER M3 ;
      RECT 653.955 0.0 654.165 0.38 ;
      END
    ANTENNAGATEAREA 0.0072 ;
    ANTENNADIFFAREA 0.0737 ;
    END WEN[30]
  PIN WEN[1]
    DIRECTION INPUT ;
    USE SIGNAL ;
    SHAPE ABUTMENT ;
    PORT
      LAYER M3 ;
      RECT 29.445 0.0 29.655 0.38 ;
      LAYER M2 ;
      RECT 29.445 0.0 29.655 0.38 ;
      LAYER M1 ;
      RECT 29.445 0.0 29.655 0.38 ;
      END
    ANTENNAGATEAREA 0.0072 ;
    ANTENNADIFFAREA 0.0737 ;
    END WEN[1]
  PIN Q[30]
    DIRECTION OUTPUT ;
    USE SIGNAL ;
    SHAPE ABUTMENT ;
    PORT
      LAYER M1 ;
      RECT 654.305 0.0 654.515 0.38 ;
      LAYER M2 ;
      RECT 654.305 0.0 654.515 0.38 ;
      LAYER M3 ;
      RECT 654.305 0.0 654.515 0.38 ;
      END
    ANTENNADIFFAREA 0.0737 ;
    END Q[30]
  PIN Q[1]
    DIRECTION OUTPUT ;
    USE SIGNAL ;
    SHAPE ABUTMENT ;
    PORT
      LAYER M3 ;
      RECT 29.095 0.0 29.305 0.38 ;
      LAYER M2 ;
      RECT 29.095 0.0 29.305 0.38 ;
      LAYER M1 ;
      RECT 29.095 0.0 29.305 0.38 ;
      END
    ANTENNADIFFAREA 0.0737 ;
    END Q[1]
  PIN D[31]
    DIRECTION INPUT ;
    USE SIGNAL ;
    SHAPE ABUTMENT ;
    PORT
      LAYER M1 ;
      RECT 672.755 0.0 672.965 0.38 ;
      LAYER M2 ;
      RECT 672.755 0.0 672.965 0.38 ;
      LAYER M3 ;
      RECT 672.755 0.0 672.965 0.38 ;
      END
    ANTENNAGATEAREA 0.0072 ;
    ANTENNADIFFAREA 0.0737 ;
    END D[31]
  PIN D[0]
    DIRECTION INPUT ;
    USE SIGNAL ;
    SHAPE ABUTMENT ;
    PORT
      LAYER M3 ;
      RECT 10.645 0.0 10.855 0.38 ;
      LAYER M2 ;
      RECT 10.645 0.0 10.855 0.38 ;
      LAYER M1 ;
      RECT 10.645 0.0 10.855 0.38 ;
      END
    ANTENNAGATEAREA 0.0072 ;
    ANTENNADIFFAREA 0.0737 ;
    END D[0]
  PIN WEN[31]
    DIRECTION INPUT ;
    USE SIGNAL ;
    SHAPE ABUTMENT ;
    PORT
      LAYER M1 ;
      RECT 673.795 0.0 674.005 0.38 ;
      LAYER M2 ;
      RECT 673.795 0.0 674.005 0.38 ;
      LAYER M3 ;
      RECT 673.795 0.0 674.005 0.38 ;
      END
    ANTENNAGATEAREA 0.0072 ;
    ANTENNADIFFAREA 0.0737 ;
    END WEN[31]
  PIN WEN[0]
    DIRECTION INPUT ;
    USE SIGNAL ;
    SHAPE ABUTMENT ;
    PORT
      LAYER M3 ;
      RECT 9.605 0.0 9.815 0.38 ;
      LAYER M2 ;
      RECT 9.605 0.0 9.815 0.38 ;
      LAYER M1 ;
      RECT 9.605 0.0 9.815 0.38 ;
      END
    ANTENNAGATEAREA 0.0072 ;
    ANTENNADIFFAREA 0.0737 ;
    END WEN[0]
  PIN Q[31]
    DIRECTION OUTPUT ;
    USE SIGNAL ;
    SHAPE ABUTMENT ;
    PORT
      LAYER M1 ;
      RECT 674.145 0.0 674.355 0.38 ;
      LAYER M2 ;
      RECT 674.145 0.0 674.355 0.38 ;
      LAYER M3 ;
      RECT 674.145 0.0 674.355 0.38 ;
      END
    ANTENNADIFFAREA 0.0737 ;
    END Q[31]
  PIN Q[0]
    DIRECTION OUTPUT ;
    USE SIGNAL ;
    SHAPE ABUTMENT ;
    PORT
      LAYER M3 ;
      RECT 9.255 0.0 9.465 0.38 ;
      LAYER M2 ;
      RECT 9.255 0.0 9.465 0.38 ;
      LAYER M1 ;
      RECT 9.255 0.0 9.465 0.38 ;
      END
    ANTENNADIFFAREA 0.0737 ;
    END Q[0]
  PIN VDDCE
    DIRECTION INOUT ;
    USE POWER ;
    PORT
      LAYER M4 ;
      RECT 0.955 0.0 1.265 301.205 ;
      END
    PORT
      LAYER M4 ;
      RECT 2.905 0.0 3.235 301.205 ;
      END
    PORT
      LAYER M4 ;
      RECT 7.865 0.0 8.195 301.205 ;
      END
    PORT
      LAYER M4 ;
      RECT 12.825 0.0 13.155 301.205 ;
      END
    PORT
      LAYER M4 ;
      RECT 17.785 0.0 18.115 301.205 ;
      END
    PORT
      LAYER M4 ;
      RECT 22.745 0.0 23.075 301.205 ;
      END
    PORT
      LAYER M4 ;
      RECT 27.705 0.0 28.035 301.205 ;
      END
    PORT
      LAYER M4 ;
      RECT 32.665 0.0 32.995 301.205 ;
      END
    PORT
      LAYER M4 ;
      RECT 37.625 0.0 37.955 301.205 ;
      END
    PORT
      LAYER M4 ;
      RECT 42.585 0.0 42.915 301.205 ;
      END
    PORT
      LAYER M4 ;
      RECT 47.545 0.0 47.875 301.205 ;
      END
    PORT
      LAYER M4 ;
      RECT 52.505 0.0 52.835 301.205 ;
      END
    PORT
      LAYER M4 ;
      RECT 57.465 0.0 57.795 301.205 ;
      END
    PORT
      LAYER M4 ;
      RECT 62.425 0.0 62.755 301.205 ;
      END
    PORT
      LAYER M4 ;
      RECT 67.385 0.0 67.715 301.205 ;
      END
    PORT
      LAYER M4 ;
      RECT 72.345 0.0 72.675 301.205 ;
      END
    PORT
      LAYER M4 ;
      RECT 77.305 0.0 77.635 301.205 ;
      END
    PORT
      LAYER M4 ;
      RECT 82.265 0.0 82.595 301.205 ;
      END
    PORT
      LAYER M4 ;
      RECT 87.225 0.0 87.555 301.205 ;
      END
    PORT
      LAYER M4 ;
      RECT 92.185 0.0 92.515 301.205 ;
      END
    PORT
      LAYER M4 ;
      RECT 97.145 0.0 97.475 301.205 ;
      END
    PORT
      LAYER M4 ;
      RECT 102.105 0.0 102.435 301.205 ;
      END
    PORT
      LAYER M4 ;
      RECT 107.065 0.0 107.395 301.205 ;
      END
    PORT
      LAYER M4 ;
      RECT 112.025 0.0 112.355 301.205 ;
      END
    PORT
      LAYER M4 ;
      RECT 116.985 0.0 117.315 301.205 ;
      END
    PORT
      LAYER M4 ;
      RECT 121.945 0.0 122.275 301.205 ;
      END
    PORT
      LAYER M4 ;
      RECT 126.905 0.0 127.235 301.205 ;
      END
    PORT
      LAYER M4 ;
      RECT 131.865 0.0 132.195 301.205 ;
      END
    PORT
      LAYER M4 ;
      RECT 136.825 0.0 137.155 301.205 ;
      END
    PORT
      LAYER M4 ;
      RECT 141.785 0.0 142.115 301.205 ;
      END
    PORT
      LAYER M4 ;
      RECT 146.745 0.0 147.075 301.205 ;
      END
    PORT
      LAYER M4 ;
      RECT 151.705 0.0 152.035 301.205 ;
      END
    PORT
      LAYER M4 ;
      RECT 156.665 0.0 156.995 301.205 ;
      END
    PORT
      LAYER M4 ;
      RECT 161.625 0.0 161.955 301.205 ;
      END
    PORT
      LAYER M4 ;
      RECT 166.585 0.0 166.915 301.205 ;
      END
    PORT
      LAYER M4 ;
      RECT 171.545 0.0 171.875 301.205 ;
      END
    PORT
      LAYER M4 ;
      RECT 176.505 0.0 176.835 301.205 ;
      END
    PORT
      LAYER M4 ;
      RECT 181.465 0.0 181.795 301.205 ;
      END
    PORT
      LAYER M4 ;
      RECT 186.425 0.0 186.755 301.205 ;
      END
    PORT
      LAYER M4 ;
      RECT 191.385 0.0 191.715 301.205 ;
      END
    PORT
      LAYER M4 ;
      RECT 196.345 0.0 196.675 301.205 ;
      END
    PORT
      LAYER M4 ;
      RECT 201.305 0.0 201.635 301.205 ;
      END
    PORT
      LAYER M4 ;
      RECT 206.265 0.0 206.595 301.205 ;
      END
    PORT
      LAYER M4 ;
      RECT 211.225 0.0 211.555 301.205 ;
      END
    PORT
      LAYER M4 ;
      RECT 216.185 0.0 216.515 301.205 ;
      END
    PORT
      LAYER M4 ;
      RECT 221.145 0.0 221.475 301.205 ;
      END
    PORT
      LAYER M4 ;
      RECT 226.105 0.0 226.435 301.205 ;
      END
    PORT
      LAYER M4 ;
      RECT 231.065 0.0 231.395 301.205 ;
      END
    PORT
      LAYER M4 ;
      RECT 236.025 0.0 236.355 301.205 ;
      END
    PORT
      LAYER M4 ;
      RECT 240.985 0.0 241.315 301.205 ;
      END
    PORT
      LAYER M4 ;
      RECT 245.945 0.0 246.275 301.205 ;
      END
    PORT
      LAYER M4 ;
      RECT 250.905 0.0 251.235 301.205 ;
      END
    PORT
      LAYER M4 ;
      RECT 255.865 0.0 256.195 301.205 ;
      END
    PORT
      LAYER M4 ;
      RECT 260.825 0.0 261.155 301.205 ;
      END
    PORT
      LAYER M4 ;
      RECT 265.785 0.0 266.115 301.205 ;
      END
    PORT
      LAYER M4 ;
      RECT 270.745 0.0 271.075 301.205 ;
      END
    PORT
      LAYER M4 ;
      RECT 275.705 0.0 276.035 301.205 ;
      END
    PORT
      LAYER M4 ;
      RECT 280.665 0.0 280.995 301.205 ;
      END
    PORT
      LAYER M4 ;
      RECT 285.625 0.0 285.955 301.205 ;
      END
    PORT
      LAYER M4 ;
      RECT 290.585 0.0 290.915 301.205 ;
      END
    PORT
      LAYER M4 ;
      RECT 295.545 0.0 295.875 301.205 ;
      END
    PORT
      LAYER M4 ;
      RECT 300.505 0.0 300.835 301.205 ;
      END
    PORT
      LAYER M4 ;
      RECT 305.465 0.0 305.795 301.205 ;
      END
    PORT
      LAYER M4 ;
      RECT 310.425 0.0 310.755 301.205 ;
      END
    PORT
      LAYER M4 ;
      RECT 315.385 0.0 315.715 301.205 ;
      END
    PORT
      LAYER M4 ;
      RECT 319.76 0.0 320.08 301.205 ;
      END
    PORT
      LAYER M4 ;
      RECT 325.9 0.0 326.12 301.205 ;
      END
    PORT
      LAYER M4 ;
      RECT 326.525 0.0 326.905 301.205 ;
      END
    PORT
      LAYER M4 ;
      RECT 351.745 0.0 351.925 301.205 ;
      END
    PORT
      LAYER M4 ;
      RECT 355.255 0.0 355.555 301.205 ;
      END
    PORT
      LAYER M4 ;
      RECT 363.53 0.0 363.85 301.205 ;
      END
    PORT
      LAYER M4 ;
      RECT 367.895 0.0 368.225 301.205 ;
      END
    PORT
      LAYER M4 ;
      RECT 372.855 0.0 373.185 301.205 ;
      END
    PORT
      LAYER M4 ;
      RECT 377.815 0.0 378.145 301.205 ;
      END
    PORT
      LAYER M4 ;
      RECT 382.775 0.0 383.105 301.205 ;
      END
    PORT
      LAYER M4 ;
      RECT 387.735 0.0 388.065 301.205 ;
      END
    PORT
      LAYER M4 ;
      RECT 392.695 0.0 393.025 301.205 ;
      END
    PORT
      LAYER M4 ;
      RECT 397.655 0.0 397.985 301.205 ;
      END
    PORT
      LAYER M4 ;
      RECT 402.615 0.0 402.945 301.205 ;
      END
    PORT
      LAYER M4 ;
      RECT 407.575 0.0 407.905 301.205 ;
      END
    PORT
      LAYER M4 ;
      RECT 412.535 0.0 412.865 301.205 ;
      END
    PORT
      LAYER M4 ;
      RECT 417.495 0.0 417.825 301.205 ;
      END
    PORT
      LAYER M4 ;
      RECT 422.455 0.0 422.785 301.205 ;
      END
    PORT
      LAYER M4 ;
      RECT 427.415 0.0 427.745 301.205 ;
      END
    PORT
      LAYER M4 ;
      RECT 432.375 0.0 432.705 301.205 ;
      END
    PORT
      LAYER M4 ;
      RECT 437.335 0.0 437.665 301.205 ;
      END
    PORT
      LAYER M4 ;
      RECT 442.295 0.0 442.625 301.205 ;
      END
    PORT
      LAYER M4 ;
      RECT 447.255 0.0 447.585 301.205 ;
      END
    PORT
      LAYER M4 ;
      RECT 452.215 0.0 452.545 301.205 ;
      END
    PORT
      LAYER M4 ;
      RECT 457.175 0.0 457.505 301.205 ;
      END
    PORT
      LAYER M4 ;
      RECT 462.135 0.0 462.465 301.205 ;
      END
    PORT
      LAYER M4 ;
      RECT 467.095 0.0 467.425 301.205 ;
      END
    PORT
      LAYER M4 ;
      RECT 472.055 0.0 472.385 301.205 ;
      END
    PORT
      LAYER M4 ;
      RECT 477.015 0.0 477.345 301.205 ;
      END
    PORT
      LAYER M4 ;
      RECT 481.975 0.0 482.305 301.205 ;
      END
    PORT
      LAYER M4 ;
      RECT 486.935 0.0 487.265 301.205 ;
      END
    PORT
      LAYER M4 ;
      RECT 491.895 0.0 492.225 301.205 ;
      END
    PORT
      LAYER M4 ;
      RECT 496.855 0.0 497.185 301.205 ;
      END
    PORT
      LAYER M4 ;
      RECT 501.815 0.0 502.145 301.205 ;
      END
    PORT
      LAYER M4 ;
      RECT 506.775 0.0 507.105 301.205 ;
      END
    PORT
      LAYER M4 ;
      RECT 511.735 0.0 512.065 301.205 ;
      END
    PORT
      LAYER M4 ;
      RECT 516.695 0.0 517.025 301.205 ;
      END
    PORT
      LAYER M4 ;
      RECT 521.655 0.0 521.985 301.205 ;
      END
    PORT
      LAYER M4 ;
      RECT 526.615 0.0 526.945 301.205 ;
      END
    PORT
      LAYER M4 ;
      RECT 531.575 0.0 531.905 301.205 ;
      END
    PORT
      LAYER M4 ;
      RECT 536.535 0.0 536.865 301.205 ;
      END
    PORT
      LAYER M4 ;
      RECT 541.495 0.0 541.825 301.205 ;
      END
    PORT
      LAYER M4 ;
      RECT 546.455 0.0 546.785 301.205 ;
      END
    PORT
      LAYER M4 ;
      RECT 551.415 0.0 551.745 301.205 ;
      END
    PORT
      LAYER M4 ;
      RECT 556.375 0.0 556.705 301.205 ;
      END
    PORT
      LAYER M4 ;
      RECT 561.335 0.0 561.665 301.205 ;
      END
    PORT
      LAYER M4 ;
      RECT 566.295 0.0 566.625 301.205 ;
      END
    PORT
      LAYER M4 ;
      RECT 571.255 0.0 571.585 301.205 ;
      END
    PORT
      LAYER M4 ;
      RECT 576.215 0.0 576.545 301.205 ;
      END
    PORT
      LAYER M4 ;
      RECT 581.175 0.0 581.505 301.205 ;
      END
    PORT
      LAYER M4 ;
      RECT 586.135 0.0 586.465 301.205 ;
      END
    PORT
      LAYER M4 ;
      RECT 591.095 0.0 591.425 301.205 ;
      END
    PORT
      LAYER M4 ;
      RECT 596.055 0.0 596.385 301.205 ;
      END
    PORT
      LAYER M4 ;
      RECT 601.015 0.0 601.345 301.205 ;
      END
    PORT
      LAYER M4 ;
      RECT 605.975 0.0 606.305 301.205 ;
      END
    PORT
      LAYER M4 ;
      RECT 610.935 0.0 611.265 301.205 ;
      END
    PORT
      LAYER M4 ;
      RECT 615.895 0.0 616.225 301.205 ;
      END
    PORT
      LAYER M4 ;
      RECT 620.855 0.0 621.185 301.205 ;
      END
    PORT
      LAYER M4 ;
      RECT 625.815 0.0 626.145 301.205 ;
      END
    PORT
      LAYER M4 ;
      RECT 630.775 0.0 631.105 301.205 ;
      END
    PORT
      LAYER M4 ;
      RECT 635.735 0.0 636.065 301.205 ;
      END
    PORT
      LAYER M4 ;
      RECT 640.695 0.0 641.025 301.205 ;
      END
    PORT
      LAYER M4 ;
      RECT 645.655 0.0 645.985 301.205 ;
      END
    PORT
      LAYER M4 ;
      RECT 650.615 0.0 650.945 301.205 ;
      END
    PORT
      LAYER M4 ;
      RECT 655.575 0.0 655.905 301.205 ;
      END
    PORT
      LAYER M4 ;
      RECT 660.535 0.0 660.865 301.205 ;
      END
    PORT
      LAYER M4 ;
      RECT 665.495 0.0 665.825 301.205 ;
      END
    PORT
      LAYER M4 ;
      RECT 670.455 0.0 670.785 301.205 ;
      END
    PORT
      LAYER M4 ;
      RECT 675.415 0.0 675.745 301.205 ;
      END
    PORT
      LAYER M4 ;
      RECT 680.375 0.0 680.705 301.205 ;
      END
    PORT
      LAYER M4 ;
      RECT 682.345 0.0 682.655 301.205 ;
      END
    END VDDCE
  PIN VDDPE
    DIRECTION INOUT ;
    USE POWER ;
    PORT
      LAYER M4 ;
      RECT 0.065 0.0 0.375 301.205 ;
      END
    PORT
      LAYER M4 ;
      RECT 1.435 0.0 1.765 301.205 ;
      END
    PORT
      LAYER M4 ;
      RECT 3.885 0.0 4.215 301.205 ;
      END
    PORT
      LAYER M4 ;
      RECT 6.395 0.0 6.725 301.205 ;
      END
    PORT
      LAYER M4 ;
      RECT 8.845 0.0 9.175 301.205 ;
      END
    PORT
      LAYER M4 ;
      RECT 11.355 0.0 11.685 301.205 ;
      END
    PORT
      LAYER M4 ;
      RECT 13.805 0.0 14.135 301.205 ;
      END
    PORT
      LAYER M4 ;
      RECT 16.315 0.0 16.645 301.205 ;
      END
    PORT
      LAYER M4 ;
      RECT 18.765 0.0 19.095 301.205 ;
      END
    PORT
      LAYER M4 ;
      RECT 21.275 0.0 21.605 301.205 ;
      END
    PORT
      LAYER M4 ;
      RECT 23.725 0.0 24.055 301.205 ;
      END
    PORT
      LAYER M4 ;
      RECT 26.235 0.0 26.565 301.205 ;
      END
    PORT
      LAYER M4 ;
      RECT 28.685 0.0 29.015 301.205 ;
      END
    PORT
      LAYER M4 ;
      RECT 31.195 0.0 31.525 301.205 ;
      END
    PORT
      LAYER M4 ;
      RECT 33.645 0.0 33.975 301.205 ;
      END
    PORT
      LAYER M4 ;
      RECT 36.155 0.0 36.485 301.205 ;
      END
    PORT
      LAYER M4 ;
      RECT 38.605 0.0 38.935 301.205 ;
      END
    PORT
      LAYER M4 ;
      RECT 41.115 0.0 41.445 301.205 ;
      END
    PORT
      LAYER M4 ;
      RECT 43.565 0.0 43.895 301.205 ;
      END
    PORT
      LAYER M4 ;
      RECT 46.075 0.0 46.405 301.205 ;
      END
    PORT
      LAYER M4 ;
      RECT 48.525 0.0 48.855 301.205 ;
      END
    PORT
      LAYER M4 ;
      RECT 51.035 0.0 51.365 301.205 ;
      END
    PORT
      LAYER M4 ;
      RECT 53.485 0.0 53.815 301.205 ;
      END
    PORT
      LAYER M4 ;
      RECT 55.995 0.0 56.325 301.205 ;
      END
    PORT
      LAYER M4 ;
      RECT 58.445 0.0 58.775 301.205 ;
      END
    PORT
      LAYER M4 ;
      RECT 60.955 0.0 61.285 301.205 ;
      END
    PORT
      LAYER M4 ;
      RECT 63.405 0.0 63.735 301.205 ;
      END
    PORT
      LAYER M4 ;
      RECT 65.915 0.0 66.245 301.205 ;
      END
    PORT
      LAYER M4 ;
      RECT 68.365 0.0 68.695 301.205 ;
      END
    PORT
      LAYER M4 ;
      RECT 70.875 0.0 71.205 301.205 ;
      END
    PORT
      LAYER M4 ;
      RECT 73.325 0.0 73.655 301.205 ;
      END
    PORT
      LAYER M4 ;
      RECT 75.835 0.0 76.165 301.205 ;
      END
    PORT
      LAYER M4 ;
      RECT 78.285 0.0 78.615 301.205 ;
      END
    PORT
      LAYER M4 ;
      RECT 80.795 0.0 81.125 301.205 ;
      END
    PORT
      LAYER M4 ;
      RECT 83.245 0.0 83.575 301.205 ;
      END
    PORT
      LAYER M4 ;
      RECT 85.755 0.0 86.085 301.205 ;
      END
    PORT
      LAYER M4 ;
      RECT 88.205 0.0 88.535 301.205 ;
      END
    PORT
      LAYER M4 ;
      RECT 90.715 0.0 91.045 301.205 ;
      END
    PORT
      LAYER M4 ;
      RECT 93.165 0.0 93.495 301.205 ;
      END
    PORT
      LAYER M4 ;
      RECT 95.675 0.0 96.005 301.205 ;
      END
    PORT
      LAYER M4 ;
      RECT 98.125 0.0 98.455 301.205 ;
      END
    PORT
      LAYER M4 ;
      RECT 100.635 0.0 100.965 301.205 ;
      END
    PORT
      LAYER M4 ;
      RECT 103.085 0.0 103.415 301.205 ;
      END
    PORT
      LAYER M4 ;
      RECT 105.595 0.0 105.925 301.205 ;
      END
    PORT
      LAYER M4 ;
      RECT 108.045 0.0 108.375 301.205 ;
      END
    PORT
      LAYER M4 ;
      RECT 110.555 0.0 110.885 301.205 ;
      END
    PORT
      LAYER M4 ;
      RECT 113.005 0.0 113.335 301.205 ;
      END
    PORT
      LAYER M4 ;
      RECT 115.515 0.0 115.845 301.205 ;
      END
    PORT
      LAYER M4 ;
      RECT 117.965 0.0 118.295 301.205 ;
      END
    PORT
      LAYER M4 ;
      RECT 120.475 0.0 120.805 301.205 ;
      END
    PORT
      LAYER M4 ;
      RECT 122.925 0.0 123.255 301.205 ;
      END
    PORT
      LAYER M4 ;
      RECT 125.435 0.0 125.765 301.205 ;
      END
    PORT
      LAYER M4 ;
      RECT 127.885 0.0 128.215 301.205 ;
      END
    PORT
      LAYER M4 ;
      RECT 130.395 0.0 130.725 301.205 ;
      END
    PORT
      LAYER M4 ;
      RECT 132.845 0.0 133.175 301.205 ;
      END
    PORT
      LAYER M4 ;
      RECT 135.355 0.0 135.685 301.205 ;
      END
    PORT
      LAYER M4 ;
      RECT 137.805 0.0 138.135 301.205 ;
      END
    PORT
      LAYER M4 ;
      RECT 140.315 0.0 140.645 301.205 ;
      END
    PORT
      LAYER M4 ;
      RECT 142.765 0.0 143.095 301.205 ;
      END
    PORT
      LAYER M4 ;
      RECT 145.275 0.0 145.605 301.205 ;
      END
    PORT
      LAYER M4 ;
      RECT 147.725 0.0 148.055 301.205 ;
      END
    PORT
      LAYER M4 ;
      RECT 150.235 0.0 150.565 301.205 ;
      END
    PORT
      LAYER M4 ;
      RECT 152.685 0.0 153.015 301.205 ;
      END
    PORT
      LAYER M4 ;
      RECT 155.195 0.0 155.525 301.205 ;
      END
    PORT
      LAYER M4 ;
      RECT 157.645 0.0 157.975 301.205 ;
      END
    PORT
      LAYER M4 ;
      RECT 160.155 0.0 160.485 301.205 ;
      END
    PORT
      LAYER M4 ;
      RECT 162.605 0.0 162.935 301.205 ;
      END
    PORT
      LAYER M4 ;
      RECT 165.115 0.0 165.445 301.205 ;
      END
    PORT
      LAYER M4 ;
      RECT 167.565 0.0 167.895 301.205 ;
      END
    PORT
      LAYER M4 ;
      RECT 170.075 0.0 170.405 301.205 ;
      END
    PORT
      LAYER M4 ;
      RECT 172.525 0.0 172.855 301.205 ;
      END
    PORT
      LAYER M4 ;
      RECT 175.035 0.0 175.365 301.205 ;
      END
    PORT
      LAYER M4 ;
      RECT 177.485 0.0 177.815 301.205 ;
      END
    PORT
      LAYER M4 ;
      RECT 179.995 0.0 180.325 301.205 ;
      END
    PORT
      LAYER M4 ;
      RECT 182.445 0.0 182.775 301.205 ;
      END
    PORT
      LAYER M4 ;
      RECT 184.955 0.0 185.285 301.205 ;
      END
    PORT
      LAYER M4 ;
      RECT 187.405 0.0 187.735 301.205 ;
      END
    PORT
      LAYER M4 ;
      RECT 189.915 0.0 190.245 301.205 ;
      END
    PORT
      LAYER M4 ;
      RECT 192.365 0.0 192.695 301.205 ;
      END
    PORT
      LAYER M4 ;
      RECT 194.875 0.0 195.205 301.205 ;
      END
    PORT
      LAYER M4 ;
      RECT 197.325 0.0 197.655 301.205 ;
      END
    PORT
      LAYER M4 ;
      RECT 199.835 0.0 200.165 301.205 ;
      END
    PORT
      LAYER M4 ;
      RECT 202.285 0.0 202.615 301.205 ;
      END
    PORT
      LAYER M4 ;
      RECT 204.795 0.0 205.125 301.205 ;
      END
    PORT
      LAYER M4 ;
      RECT 207.245 0.0 207.575 301.205 ;
      END
    PORT
      LAYER M4 ;
      RECT 209.755 0.0 210.085 301.205 ;
      END
    PORT
      LAYER M4 ;
      RECT 212.205 0.0 212.535 301.205 ;
      END
    PORT
      LAYER M4 ;
      RECT 214.715 0.0 215.045 301.205 ;
      END
    PORT
      LAYER M4 ;
      RECT 217.165 0.0 217.495 301.205 ;
      END
    PORT
      LAYER M4 ;
      RECT 219.675 0.0 220.005 301.205 ;
      END
    PORT
      LAYER M4 ;
      RECT 222.125 0.0 222.455 301.205 ;
      END
    PORT
      LAYER M4 ;
      RECT 224.635 0.0 224.965 301.205 ;
      END
    PORT
      LAYER M4 ;
      RECT 227.085 0.0 227.415 301.205 ;
      END
    PORT
      LAYER M4 ;
      RECT 229.595 0.0 229.925 301.205 ;
      END
    PORT
      LAYER M4 ;
      RECT 232.045 0.0 232.375 301.205 ;
      END
    PORT
      LAYER M4 ;
      RECT 234.555 0.0 234.885 301.205 ;
      END
    PORT
      LAYER M4 ;
      RECT 237.005 0.0 237.335 301.205 ;
      END
    PORT
      LAYER M4 ;
      RECT 239.515 0.0 239.845 301.205 ;
      END
    PORT
      LAYER M4 ;
      RECT 241.965 0.0 242.295 301.205 ;
      END
    PORT
      LAYER M4 ;
      RECT 244.475 0.0 244.805 301.205 ;
      END
    PORT
      LAYER M4 ;
      RECT 246.925 0.0 247.255 301.205 ;
      END
    PORT
      LAYER M4 ;
      RECT 249.435 0.0 249.765 301.205 ;
      END
    PORT
      LAYER M4 ;
      RECT 251.885 0.0 252.215 301.205 ;
      END
    PORT
      LAYER M4 ;
      RECT 254.395 0.0 254.725 301.205 ;
      END
    PORT
      LAYER M4 ;
      RECT 256.845 0.0 257.175 301.205 ;
      END
    PORT
      LAYER M4 ;
      RECT 259.355 0.0 259.685 301.205 ;
      END
    PORT
      LAYER M4 ;
      RECT 261.805 0.0 262.135 301.205 ;
      END
    PORT
      LAYER M4 ;
      RECT 264.315 0.0 264.645 301.205 ;
      END
    PORT
      LAYER M4 ;
      RECT 266.765 0.0 267.095 301.205 ;
      END
    PORT
      LAYER M4 ;
      RECT 269.275 0.0 269.605 301.205 ;
      END
    PORT
      LAYER M4 ;
      RECT 271.725 0.0 272.055 301.205 ;
      END
    PORT
      LAYER M4 ;
      RECT 274.235 0.0 274.565 301.205 ;
      END
    PORT
      LAYER M4 ;
      RECT 276.685 0.0 277.015 301.205 ;
      END
    PORT
      LAYER M4 ;
      RECT 279.195 0.0 279.525 301.205 ;
      END
    PORT
      LAYER M4 ;
      RECT 281.645 0.0 281.975 301.205 ;
      END
    PORT
      LAYER M4 ;
      RECT 284.155 0.0 284.485 301.205 ;
      END
    PORT
      LAYER M4 ;
      RECT 286.605 0.0 286.935 301.205 ;
      END
    PORT
      LAYER M4 ;
      RECT 289.115 0.0 289.445 301.205 ;
      END
    PORT
      LAYER M4 ;
      RECT 291.565 0.0 291.895 301.205 ;
      END
    PORT
      LAYER M4 ;
      RECT 294.075 0.0 294.405 301.205 ;
      END
    PORT
      LAYER M4 ;
      RECT 296.525 0.0 296.855 301.205 ;
      END
    PORT
      LAYER M4 ;
      RECT 299.035 0.0 299.365 301.205 ;
      END
    PORT
      LAYER M4 ;
      RECT 301.485 0.0 301.815 301.205 ;
      END
    PORT
      LAYER M4 ;
      RECT 303.995 0.0 304.325 301.205 ;
      END
    PORT
      LAYER M4 ;
      RECT 306.445 0.0 306.775 301.205 ;
      END
    PORT
      LAYER M4 ;
      RECT 308.955 0.0 309.285 301.205 ;
      END
    PORT
      LAYER M4 ;
      RECT 311.405 0.0 311.735 301.205 ;
      END
    PORT
      LAYER M4 ;
      RECT 313.915 0.0 314.245 301.205 ;
      END
    PORT
      LAYER M4 ;
      RECT 316.365 0.0 316.695 301.205 ;
      END
    PORT
      LAYER M4 ;
      RECT 318.85 0.0 319.17 301.205 ;
      END
    PORT
      LAYER M4 ;
      RECT 320.285 0.0 320.685 301.205 ;
      END
    PORT
      LAYER M4 ;
      RECT 323.715 0.0 324.115 301.205 ;
      END
    PORT
      LAYER M4 ;
      RECT 325.045 0.0 325.435 301.205 ;
      END
    PORT
      LAYER M4 ;
      RECT 329.075 0.0 329.285 301.205 ;
      END
    PORT
      LAYER M4 ;
      RECT 330.095 0.0 330.305 301.205 ;
      END
    PORT
      LAYER M4 ;
      RECT 331.235 0.0 331.535 301.205 ;
      END
    PORT
      LAYER M4 ;
      RECT 332.175 0.0 332.475 301.205 ;
      END
    PORT
      LAYER M4 ;
      RECT 334.975 0.0 335.275 301.205 ;
      END
    PORT
      LAYER M4 ;
      RECT 337.605 0.0 337.825 301.205 ;
      END
    PORT
      LAYER M4 ;
      RECT 341.345 0.0 341.745 301.205 ;
      END
    PORT
      LAYER M4 ;
      RECT 342.735 0.0 343.105 301.205 ;
      END
    PORT
      LAYER M4 ;
      RECT 346.345 0.0 346.525 301.205 ;
      END
    PORT
      LAYER M4 ;
      RECT 351.285 0.0 351.585 301.205 ;
      END
    PORT
      LAYER M4 ;
      RECT 352.53 0.0 352.83 301.205 ;
      END
    PORT
      LAYER M4 ;
      RECT 353.98 0.0 354.16 301.205 ;
      END
    PORT
      LAYER M4 ;
      RECT 357.195 0.0 357.375 301.205 ;
      END
    PORT
      LAYER M4 ;
      RECT 358.4 0.0 358.8 301.205 ;
      END
    PORT
      LAYER M4 ;
      RECT 359.62 0.0 359.92 301.205 ;
      END
    PORT
      LAYER M4 ;
      RECT 362.4 0.0 362.7 301.205 ;
      END
    PORT
      LAYER M4 ;
      RECT 364.44 0.0 364.76 301.205 ;
      END
    PORT
      LAYER M4 ;
      RECT 366.915 0.0 367.245 301.205 ;
      END
    PORT
      LAYER M4 ;
      RECT 369.365 0.0 369.695 301.205 ;
      END
    PORT
      LAYER M4 ;
      RECT 371.875 0.0 372.205 301.205 ;
      END
    PORT
      LAYER M4 ;
      RECT 374.325 0.0 374.655 301.205 ;
      END
    PORT
      LAYER M4 ;
      RECT 376.835 0.0 377.165 301.205 ;
      END
    PORT
      LAYER M4 ;
      RECT 379.285 0.0 379.615 301.205 ;
      END
    PORT
      LAYER M4 ;
      RECT 381.795 0.0 382.125 301.205 ;
      END
    PORT
      LAYER M4 ;
      RECT 384.245 0.0 384.575 301.205 ;
      END
    PORT
      LAYER M4 ;
      RECT 386.755 0.0 387.085 301.205 ;
      END
    PORT
      LAYER M4 ;
      RECT 389.205 0.0 389.535 301.205 ;
      END
    PORT
      LAYER M4 ;
      RECT 391.715 0.0 392.045 301.205 ;
      END
    PORT
      LAYER M4 ;
      RECT 394.165 0.0 394.495 301.205 ;
      END
    PORT
      LAYER M4 ;
      RECT 396.675 0.0 397.005 301.205 ;
      END
    PORT
      LAYER M4 ;
      RECT 399.125 0.0 399.455 301.205 ;
      END
    PORT
      LAYER M4 ;
      RECT 401.635 0.0 401.965 301.205 ;
      END
    PORT
      LAYER M4 ;
      RECT 404.085 0.0 404.415 301.205 ;
      END
    PORT
      LAYER M4 ;
      RECT 406.595 0.0 406.925 301.205 ;
      END
    PORT
      LAYER M4 ;
      RECT 409.045 0.0 409.375 301.205 ;
      END
    PORT
      LAYER M4 ;
      RECT 411.555 0.0 411.885 301.205 ;
      END
    PORT
      LAYER M4 ;
      RECT 414.005 0.0 414.335 301.205 ;
      END
    PORT
      LAYER M4 ;
      RECT 416.515 0.0 416.845 301.205 ;
      END
    PORT
      LAYER M4 ;
      RECT 418.965 0.0 419.295 301.205 ;
      END
    PORT
      LAYER M4 ;
      RECT 421.475 0.0 421.805 301.205 ;
      END
    PORT
      LAYER M4 ;
      RECT 423.925 0.0 424.255 301.205 ;
      END
    PORT
      LAYER M4 ;
      RECT 426.435 0.0 426.765 301.205 ;
      END
    PORT
      LAYER M4 ;
      RECT 428.885 0.0 429.215 301.205 ;
      END
    PORT
      LAYER M4 ;
      RECT 431.395 0.0 431.725 301.205 ;
      END
    PORT
      LAYER M4 ;
      RECT 433.845 0.0 434.175 301.205 ;
      END
    PORT
      LAYER M4 ;
      RECT 436.355 0.0 436.685 301.205 ;
      END
    PORT
      LAYER M4 ;
      RECT 438.805 0.0 439.135 301.205 ;
      END
    PORT
      LAYER M4 ;
      RECT 441.315 0.0 441.645 301.205 ;
      END
    PORT
      LAYER M4 ;
      RECT 443.765 0.0 444.095 301.205 ;
      END
    PORT
      LAYER M4 ;
      RECT 446.275 0.0 446.605 301.205 ;
      END
    PORT
      LAYER M4 ;
      RECT 448.725 0.0 449.055 301.205 ;
      END
    PORT
      LAYER M4 ;
      RECT 451.235 0.0 451.565 301.205 ;
      END
    PORT
      LAYER M4 ;
      RECT 453.685 0.0 454.015 301.205 ;
      END
    PORT
      LAYER M4 ;
      RECT 456.195 0.0 456.525 301.205 ;
      END
    PORT
      LAYER M4 ;
      RECT 458.645 0.0 458.975 301.205 ;
      END
    PORT
      LAYER M4 ;
      RECT 461.155 0.0 461.485 301.205 ;
      END
    PORT
      LAYER M4 ;
      RECT 463.605 0.0 463.935 301.205 ;
      END
    PORT
      LAYER M4 ;
      RECT 466.115 0.0 466.445 301.205 ;
      END
    PORT
      LAYER M4 ;
      RECT 468.565 0.0 468.895 301.205 ;
      END
    PORT
      LAYER M4 ;
      RECT 471.075 0.0 471.405 301.205 ;
      END
    PORT
      LAYER M4 ;
      RECT 473.525 0.0 473.855 301.205 ;
      END
    PORT
      LAYER M4 ;
      RECT 476.035 0.0 476.365 301.205 ;
      END
    PORT
      LAYER M4 ;
      RECT 478.485 0.0 478.815 301.205 ;
      END
    PORT
      LAYER M4 ;
      RECT 480.995 0.0 481.325 301.205 ;
      END
    PORT
      LAYER M4 ;
      RECT 483.445 0.0 483.775 301.205 ;
      END
    PORT
      LAYER M4 ;
      RECT 485.955 0.0 486.285 301.205 ;
      END
    PORT
      LAYER M4 ;
      RECT 488.405 0.0 488.735 301.205 ;
      END
    PORT
      LAYER M4 ;
      RECT 490.915 0.0 491.245 301.205 ;
      END
    PORT
      LAYER M4 ;
      RECT 493.365 0.0 493.695 301.205 ;
      END
    PORT
      LAYER M4 ;
      RECT 495.875 0.0 496.205 301.205 ;
      END
    PORT
      LAYER M4 ;
      RECT 498.325 0.0 498.655 301.205 ;
      END
    PORT
      LAYER M4 ;
      RECT 500.835 0.0 501.165 301.205 ;
      END
    PORT
      LAYER M4 ;
      RECT 503.285 0.0 503.615 301.205 ;
      END
    PORT
      LAYER M4 ;
      RECT 505.795 0.0 506.125 301.205 ;
      END
    PORT
      LAYER M4 ;
      RECT 508.245 0.0 508.575 301.205 ;
      END
    PORT
      LAYER M4 ;
      RECT 510.755 0.0 511.085 301.205 ;
      END
    PORT
      LAYER M4 ;
      RECT 513.205 0.0 513.535 301.205 ;
      END
    PORT
      LAYER M4 ;
      RECT 515.715 0.0 516.045 301.205 ;
      END
    PORT
      LAYER M4 ;
      RECT 518.165 0.0 518.495 301.205 ;
      END
    PORT
      LAYER M4 ;
      RECT 520.675 0.0 521.005 301.205 ;
      END
    PORT
      LAYER M4 ;
      RECT 523.125 0.0 523.455 301.205 ;
      END
    PORT
      LAYER M4 ;
      RECT 525.635 0.0 525.965 301.205 ;
      END
    PORT
      LAYER M4 ;
      RECT 528.085 0.0 528.415 301.205 ;
      END
    PORT
      LAYER M4 ;
      RECT 530.595 0.0 530.925 301.205 ;
      END
    PORT
      LAYER M4 ;
      RECT 533.045 0.0 533.375 301.205 ;
      END
    PORT
      LAYER M4 ;
      RECT 535.555 0.0 535.885 301.205 ;
      END
    PORT
      LAYER M4 ;
      RECT 538.005 0.0 538.335 301.205 ;
      END
    PORT
      LAYER M4 ;
      RECT 540.515 0.0 540.845 301.205 ;
      END
    PORT
      LAYER M4 ;
      RECT 542.965 0.0 543.295 301.205 ;
      END
    PORT
      LAYER M4 ;
      RECT 545.475 0.0 545.805 301.205 ;
      END
    PORT
      LAYER M4 ;
      RECT 547.925 0.0 548.255 301.205 ;
      END
    PORT
      LAYER M4 ;
      RECT 550.435 0.0 550.765 301.205 ;
      END
    PORT
      LAYER M4 ;
      RECT 552.885 0.0 553.215 301.205 ;
      END
    PORT
      LAYER M4 ;
      RECT 555.395 0.0 555.725 301.205 ;
      END
    PORT
      LAYER M4 ;
      RECT 557.845 0.0 558.175 301.205 ;
      END
    PORT
      LAYER M4 ;
      RECT 560.355 0.0 560.685 301.205 ;
      END
    PORT
      LAYER M4 ;
      RECT 562.805 0.0 563.135 301.205 ;
      END
    PORT
      LAYER M4 ;
      RECT 565.315 0.0 565.645 301.205 ;
      END
    PORT
      LAYER M4 ;
      RECT 567.765 0.0 568.095 301.205 ;
      END
    PORT
      LAYER M4 ;
      RECT 570.275 0.0 570.605 301.205 ;
      END
    PORT
      LAYER M4 ;
      RECT 572.725 0.0 573.055 301.205 ;
      END
    PORT
      LAYER M4 ;
      RECT 575.235 0.0 575.565 301.205 ;
      END
    PORT
      LAYER M4 ;
      RECT 577.685 0.0 578.015 301.205 ;
      END
    PORT
      LAYER M4 ;
      RECT 580.195 0.0 580.525 301.205 ;
      END
    PORT
      LAYER M4 ;
      RECT 582.645 0.0 582.975 301.205 ;
      END
    PORT
      LAYER M4 ;
      RECT 585.155 0.0 585.485 301.205 ;
      END
    PORT
      LAYER M4 ;
      RECT 587.605 0.0 587.935 301.205 ;
      END
    PORT
      LAYER M4 ;
      RECT 590.115 0.0 590.445 301.205 ;
      END
    PORT
      LAYER M4 ;
      RECT 592.565 0.0 592.895 301.205 ;
      END
    PORT
      LAYER M4 ;
      RECT 595.075 0.0 595.405 301.205 ;
      END
    PORT
      LAYER M4 ;
      RECT 597.525 0.0 597.855 301.205 ;
      END
    PORT
      LAYER M4 ;
      RECT 600.035 0.0 600.365 301.205 ;
      END
    PORT
      LAYER M4 ;
      RECT 602.485 0.0 602.815 301.205 ;
      END
    PORT
      LAYER M4 ;
      RECT 604.995 0.0 605.325 301.205 ;
      END
    PORT
      LAYER M4 ;
      RECT 607.445 0.0 607.775 301.205 ;
      END
    PORT
      LAYER M4 ;
      RECT 609.955 0.0 610.285 301.205 ;
      END
    PORT
      LAYER M4 ;
      RECT 612.405 0.0 612.735 301.205 ;
      END
    PORT
      LAYER M4 ;
      RECT 614.915 0.0 615.245 301.205 ;
      END
    PORT
      LAYER M4 ;
      RECT 617.365 0.0 617.695 301.205 ;
      END
    PORT
      LAYER M4 ;
      RECT 619.875 0.0 620.205 301.205 ;
      END
    PORT
      LAYER M4 ;
      RECT 622.325 0.0 622.655 301.205 ;
      END
    PORT
      LAYER M4 ;
      RECT 624.835 0.0 625.165 301.205 ;
      END
    PORT
      LAYER M4 ;
      RECT 627.285 0.0 627.615 301.205 ;
      END
    PORT
      LAYER M4 ;
      RECT 629.795 0.0 630.125 301.205 ;
      END
    PORT
      LAYER M4 ;
      RECT 632.245 0.0 632.575 301.205 ;
      END
    PORT
      LAYER M4 ;
      RECT 634.755 0.0 635.085 301.205 ;
      END
    PORT
      LAYER M4 ;
      RECT 637.205 0.0 637.535 301.205 ;
      END
    PORT
      LAYER M4 ;
      RECT 639.715 0.0 640.045 301.205 ;
      END
    PORT
      LAYER M4 ;
      RECT 642.165 0.0 642.495 301.205 ;
      END
    PORT
      LAYER M4 ;
      RECT 644.675 0.0 645.005 301.205 ;
      END
    PORT
      LAYER M4 ;
      RECT 647.125 0.0 647.455 301.205 ;
      END
    PORT
      LAYER M4 ;
      RECT 649.635 0.0 649.965 301.205 ;
      END
    PORT
      LAYER M4 ;
      RECT 652.085 0.0 652.415 301.205 ;
      END
    PORT
      LAYER M4 ;
      RECT 654.595 0.0 654.925 301.205 ;
      END
    PORT
      LAYER M4 ;
      RECT 657.045 0.0 657.375 301.205 ;
      END
    PORT
      LAYER M4 ;
      RECT 659.555 0.0 659.885 301.205 ;
      END
    PORT
      LAYER M4 ;
      RECT 662.005 0.0 662.335 301.205 ;
      END
    PORT
      LAYER M4 ;
      RECT 664.515 0.0 664.845 301.205 ;
      END
    PORT
      LAYER M4 ;
      RECT 666.965 0.0 667.295 301.205 ;
      END
    PORT
      LAYER M4 ;
      RECT 669.475 0.0 669.805 301.205 ;
      END
    PORT
      LAYER M4 ;
      RECT 671.925 0.0 672.255 301.205 ;
      END
    PORT
      LAYER M4 ;
      RECT 674.435 0.0 674.765 301.205 ;
      END
    PORT
      LAYER M4 ;
      RECT 676.885 0.0 677.215 301.205 ;
      END
    PORT
      LAYER M4 ;
      RECT 679.395 0.0 679.725 301.205 ;
      END
    PORT
      LAYER M4 ;
      RECT 681.845 0.0 682.175 301.205 ;
      END
    PORT
      LAYER M4 ;
      RECT 683.235 0.0 683.545 301.205 ;
      END
    END VDDPE
  PIN VSSE
    DIRECTION INOUT ;
    USE GROUND ;
    PORT
      LAYER M4 ;
      RECT 0.51 0.0 0.82 301.205 ;
      END
    PORT
      LAYER M4 ;
      RECT 2.415 0.0 2.745 301.205 ;
      END
    PORT
      LAYER M4 ;
      RECT 4.615 0.0 4.945 301.205 ;
      END
    PORT
      LAYER M4 ;
      RECT 7.375 0.0 7.705 301.205 ;
      END
    PORT
      LAYER M4 ;
      RECT 9.575 0.0 9.905 301.205 ;
      END
    PORT
      LAYER M4 ;
      RECT 12.335 0.0 12.665 301.205 ;
      END
    PORT
      LAYER M4 ;
      RECT 14.535 0.0 14.865 301.205 ;
      END
    PORT
      LAYER M4 ;
      RECT 17.295 0.0 17.625 301.205 ;
      END
    PORT
      LAYER M4 ;
      RECT 19.495 0.0 19.825 301.205 ;
      END
    PORT
      LAYER M4 ;
      RECT 22.255 0.0 22.585 301.205 ;
      END
    PORT
      LAYER M4 ;
      RECT 24.455 0.0 24.785 301.205 ;
      END
    PORT
      LAYER M4 ;
      RECT 27.215 0.0 27.545 301.205 ;
      END
    PORT
      LAYER M4 ;
      RECT 29.415 0.0 29.745 301.205 ;
      END
    PORT
      LAYER M4 ;
      RECT 32.175 0.0 32.505 301.205 ;
      END
    PORT
      LAYER M4 ;
      RECT 34.375 0.0 34.705 301.205 ;
      END
    PORT
      LAYER M4 ;
      RECT 37.135 0.0 37.465 301.205 ;
      END
    PORT
      LAYER M4 ;
      RECT 39.335 0.0 39.665 301.205 ;
      END
    PORT
      LAYER M4 ;
      RECT 42.095 0.0 42.425 301.205 ;
      END
    PORT
      LAYER M4 ;
      RECT 44.295 0.0 44.625 301.205 ;
      END
    PORT
      LAYER M4 ;
      RECT 47.055 0.0 47.385 301.205 ;
      END
    PORT
      LAYER M4 ;
      RECT 49.255 0.0 49.585 301.205 ;
      END
    PORT
      LAYER M4 ;
      RECT 52.015 0.0 52.345 301.205 ;
      END
    PORT
      LAYER M4 ;
      RECT 54.215 0.0 54.545 301.205 ;
      END
    PORT
      LAYER M4 ;
      RECT 56.975 0.0 57.305 301.205 ;
      END
    PORT
      LAYER M4 ;
      RECT 59.175 0.0 59.505 301.205 ;
      END
    PORT
      LAYER M4 ;
      RECT 61.935 0.0 62.265 301.205 ;
      END
    PORT
      LAYER M4 ;
      RECT 64.135 0.0 64.465 301.205 ;
      END
    PORT
      LAYER M4 ;
      RECT 66.895 0.0 67.225 301.205 ;
      END
    PORT
      LAYER M4 ;
      RECT 69.095 0.0 69.425 301.205 ;
      END
    PORT
      LAYER M4 ;
      RECT 71.855 0.0 72.185 301.205 ;
      END
    PORT
      LAYER M4 ;
      RECT 74.055 0.0 74.385 301.205 ;
      END
    PORT
      LAYER M4 ;
      RECT 76.815 0.0 77.145 301.205 ;
      END
    PORT
      LAYER M4 ;
      RECT 79.015 0.0 79.345 301.205 ;
      END
    PORT
      LAYER M4 ;
      RECT 81.775 0.0 82.105 301.205 ;
      END
    PORT
      LAYER M4 ;
      RECT 83.975 0.0 84.305 301.205 ;
      END
    PORT
      LAYER M4 ;
      RECT 86.735 0.0 87.065 301.205 ;
      END
    PORT
      LAYER M4 ;
      RECT 88.935 0.0 89.265 301.205 ;
      END
    PORT
      LAYER M4 ;
      RECT 91.695 0.0 92.025 301.205 ;
      END
    PORT
      LAYER M4 ;
      RECT 93.895 0.0 94.225 301.205 ;
      END
    PORT
      LAYER M4 ;
      RECT 96.655 0.0 96.985 301.205 ;
      END
    PORT
      LAYER M4 ;
      RECT 98.855 0.0 99.185 301.205 ;
      END
    PORT
      LAYER M4 ;
      RECT 101.615 0.0 101.945 301.205 ;
      END
    PORT
      LAYER M4 ;
      RECT 103.815 0.0 104.145 301.205 ;
      END
    PORT
      LAYER M4 ;
      RECT 106.575 0.0 106.905 301.205 ;
      END
    PORT
      LAYER M4 ;
      RECT 108.775 0.0 109.105 301.205 ;
      END
    PORT
      LAYER M4 ;
      RECT 111.535 0.0 111.865 301.205 ;
      END
    PORT
      LAYER M4 ;
      RECT 113.735 0.0 114.065 301.205 ;
      END
    PORT
      LAYER M4 ;
      RECT 116.495 0.0 116.825 301.205 ;
      END
    PORT
      LAYER M4 ;
      RECT 118.695 0.0 119.025 301.205 ;
      END
    PORT
      LAYER M4 ;
      RECT 121.455 0.0 121.785 301.205 ;
      END
    PORT
      LAYER M4 ;
      RECT 123.655 0.0 123.985 301.205 ;
      END
    PORT
      LAYER M4 ;
      RECT 126.415 0.0 126.745 301.205 ;
      END
    PORT
      LAYER M4 ;
      RECT 128.615 0.0 128.945 301.205 ;
      END
    PORT
      LAYER M4 ;
      RECT 131.375 0.0 131.705 301.205 ;
      END
    PORT
      LAYER M4 ;
      RECT 133.575 0.0 133.905 301.205 ;
      END
    PORT
      LAYER M4 ;
      RECT 136.335 0.0 136.665 301.205 ;
      END
    PORT
      LAYER M4 ;
      RECT 138.535 0.0 138.865 301.205 ;
      END
    PORT
      LAYER M4 ;
      RECT 141.295 0.0 141.625 301.205 ;
      END
    PORT
      LAYER M4 ;
      RECT 143.495 0.0 143.825 301.205 ;
      END
    PORT
      LAYER M4 ;
      RECT 146.255 0.0 146.585 301.205 ;
      END
    PORT
      LAYER M4 ;
      RECT 148.455 0.0 148.785 301.205 ;
      END
    PORT
      LAYER M4 ;
      RECT 151.215 0.0 151.545 301.205 ;
      END
    PORT
      LAYER M4 ;
      RECT 153.415 0.0 153.745 301.205 ;
      END
    PORT
      LAYER M4 ;
      RECT 156.175 0.0 156.505 301.205 ;
      END
    PORT
      LAYER M4 ;
      RECT 158.375 0.0 158.705 301.205 ;
      END
    PORT
      LAYER M4 ;
      RECT 161.135 0.0 161.465 301.205 ;
      END
    PORT
      LAYER M4 ;
      RECT 163.335 0.0 163.665 301.205 ;
      END
    PORT
      LAYER M4 ;
      RECT 166.095 0.0 166.425 301.205 ;
      END
    PORT
      LAYER M4 ;
      RECT 168.295 0.0 168.625 301.205 ;
      END
    PORT
      LAYER M4 ;
      RECT 171.055 0.0 171.385 301.205 ;
      END
    PORT
      LAYER M4 ;
      RECT 173.255 0.0 173.585 301.205 ;
      END
    PORT
      LAYER M4 ;
      RECT 176.015 0.0 176.345 301.205 ;
      END
    PORT
      LAYER M4 ;
      RECT 178.215 0.0 178.545 301.205 ;
      END
    PORT
      LAYER M4 ;
      RECT 180.975 0.0 181.305 301.205 ;
      END
    PORT
      LAYER M4 ;
      RECT 183.175 0.0 183.505 301.205 ;
      END
    PORT
      LAYER M4 ;
      RECT 185.935 0.0 186.265 301.205 ;
      END
    PORT
      LAYER M4 ;
      RECT 188.135 0.0 188.465 301.205 ;
      END
    PORT
      LAYER M4 ;
      RECT 190.895 0.0 191.225 301.205 ;
      END
    PORT
      LAYER M4 ;
      RECT 193.095 0.0 193.425 301.205 ;
      END
    PORT
      LAYER M4 ;
      RECT 195.855 0.0 196.185 301.205 ;
      END
    PORT
      LAYER M4 ;
      RECT 198.055 0.0 198.385 301.205 ;
      END
    PORT
      LAYER M4 ;
      RECT 200.815 0.0 201.145 301.205 ;
      END
    PORT
      LAYER M4 ;
      RECT 203.015 0.0 203.345 301.205 ;
      END
    PORT
      LAYER M4 ;
      RECT 205.775 0.0 206.105 301.205 ;
      END
    PORT
      LAYER M4 ;
      RECT 207.975 0.0 208.305 301.205 ;
      END
    PORT
      LAYER M4 ;
      RECT 210.735 0.0 211.065 301.205 ;
      END
    PORT
      LAYER M4 ;
      RECT 212.935 0.0 213.265 301.205 ;
      END
    PORT
      LAYER M4 ;
      RECT 215.695 0.0 216.025 301.205 ;
      END
    PORT
      LAYER M4 ;
      RECT 217.895 0.0 218.225 301.205 ;
      END
    PORT
      LAYER M4 ;
      RECT 220.655 0.0 220.985 301.205 ;
      END
    PORT
      LAYER M4 ;
      RECT 222.855 0.0 223.185 301.205 ;
      END
    PORT
      LAYER M4 ;
      RECT 225.615 0.0 225.945 301.205 ;
      END
    PORT
      LAYER M4 ;
      RECT 227.815 0.0 228.145 301.205 ;
      END
    PORT
      LAYER M4 ;
      RECT 230.575 0.0 230.905 301.205 ;
      END
    PORT
      LAYER M4 ;
      RECT 232.775 0.0 233.105 301.205 ;
      END
    PORT
      LAYER M4 ;
      RECT 235.535 0.0 235.865 301.205 ;
      END
    PORT
      LAYER M4 ;
      RECT 237.735 0.0 238.065 301.205 ;
      END
    PORT
      LAYER M4 ;
      RECT 240.495 0.0 240.825 301.205 ;
      END
    PORT
      LAYER M4 ;
      RECT 242.695 0.0 243.025 301.205 ;
      END
    PORT
      LAYER M4 ;
      RECT 245.455 0.0 245.785 301.205 ;
      END
    PORT
      LAYER M4 ;
      RECT 247.655 0.0 247.985 301.205 ;
      END
    PORT
      LAYER M4 ;
      RECT 250.415 0.0 250.745 301.205 ;
      END
    PORT
      LAYER M4 ;
      RECT 252.615 0.0 252.945 301.205 ;
      END
    PORT
      LAYER M4 ;
      RECT 255.375 0.0 255.705 301.205 ;
      END
    PORT
      LAYER M4 ;
      RECT 257.575 0.0 257.905 301.205 ;
      END
    PORT
      LAYER M4 ;
      RECT 260.335 0.0 260.665 301.205 ;
      END
    PORT
      LAYER M4 ;
      RECT 262.535 0.0 262.865 301.205 ;
      END
    PORT
      LAYER M4 ;
      RECT 265.295 0.0 265.625 301.205 ;
      END
    PORT
      LAYER M4 ;
      RECT 267.495 0.0 267.825 301.205 ;
      END
    PORT
      LAYER M4 ;
      RECT 270.255 0.0 270.585 301.205 ;
      END
    PORT
      LAYER M4 ;
      RECT 272.455 0.0 272.785 301.205 ;
      END
    PORT
      LAYER M4 ;
      RECT 275.215 0.0 275.545 301.205 ;
      END
    PORT
      LAYER M4 ;
      RECT 277.415 0.0 277.745 301.205 ;
      END
    PORT
      LAYER M4 ;
      RECT 280.175 0.0 280.505 301.205 ;
      END
    PORT
      LAYER M4 ;
      RECT 282.375 0.0 282.705 301.205 ;
      END
    PORT
      LAYER M4 ;
      RECT 285.135 0.0 285.465 301.205 ;
      END
    PORT
      LAYER M4 ;
      RECT 287.335 0.0 287.665 301.205 ;
      END
    PORT
      LAYER M4 ;
      RECT 290.095 0.0 290.425 301.205 ;
      END
    PORT
      LAYER M4 ;
      RECT 292.295 0.0 292.625 301.205 ;
      END
    PORT
      LAYER M4 ;
      RECT 295.055 0.0 295.385 301.205 ;
      END
    PORT
      LAYER M4 ;
      RECT 297.255 0.0 297.585 301.205 ;
      END
    PORT
      LAYER M4 ;
      RECT 300.015 0.0 300.345 301.205 ;
      END
    PORT
      LAYER M4 ;
      RECT 302.215 0.0 302.545 301.205 ;
      END
    PORT
      LAYER M4 ;
      RECT 304.975 0.0 305.305 301.205 ;
      END
    PORT
      LAYER M4 ;
      RECT 307.175 0.0 307.505 301.205 ;
      END
    PORT
      LAYER M4 ;
      RECT 309.935 0.0 310.265 301.205 ;
      END
    PORT
      LAYER M4 ;
      RECT 312.135 0.0 312.465 301.205 ;
      END
    PORT
      LAYER M4 ;
      RECT 314.895 0.0 315.225 301.205 ;
      END
    PORT
      LAYER M4 ;
      RECT 317.095 0.0 317.425 301.205 ;
      END
    PORT
      LAYER M4 ;
      RECT 319.305 0.0 319.625 301.205 ;
      END
    PORT
      LAYER M4 ;
      RECT 321.135 0.0 321.535 301.205 ;
      END
    PORT
      LAYER M4 ;
      RECT 323.04 0.0 323.44 301.205 ;
      END
    PORT
      LAYER M4 ;
      RECT 324.435 0.0 324.835 301.205 ;
      END
    PORT
      LAYER M4 ;
      RECT 328.12 0.0 328.52 301.205 ;
      END
    PORT
      LAYER M4 ;
      RECT 330.5 0.0 330.81 301.205 ;
      END
    PORT
      LAYER M4 ;
      RECT 333.755 0.0 333.965 301.205 ;
      END
    PORT
      LAYER M4 ;
      RECT 335.685 0.0 335.985 301.205 ;
      END
    PORT
      LAYER M4 ;
      RECT 347.92 0.0 348.14 301.205 ;
      END
    PORT
      LAYER M4 ;
      RECT 349.685 0.0 350.085 301.205 ;
      END
    PORT
      LAYER M4 ;
      RECT 352.99 0.0 353.29 301.205 ;
      END
    PORT
      LAYER M4 ;
      RECT 356.45 0.0 356.75 301.205 ;
      END
    PORT
      LAYER M4 ;
      RECT 357.79 0.0 358.19 301.205 ;
      END
    PORT
      LAYER M4 ;
      RECT 359.01 0.0 359.41 301.205 ;
      END
    PORT
      LAYER M4 ;
      RECT 362.89 0.0 363.29 301.205 ;
      END
    PORT
      LAYER M4 ;
      RECT 363.985 0.0 364.305 301.205 ;
      END
    PORT
      LAYER M4 ;
      RECT 366.185 0.0 366.515 301.205 ;
      END
    PORT
      LAYER M4 ;
      RECT 368.385 0.0 368.715 301.205 ;
      END
    PORT
      LAYER M4 ;
      RECT 371.145 0.0 371.475 301.205 ;
      END
    PORT
      LAYER M4 ;
      RECT 373.345 0.0 373.675 301.205 ;
      END
    PORT
      LAYER M4 ;
      RECT 376.105 0.0 376.435 301.205 ;
      END
    PORT
      LAYER M4 ;
      RECT 378.305 0.0 378.635 301.205 ;
      END
    PORT
      LAYER M4 ;
      RECT 381.065 0.0 381.395 301.205 ;
      END
    PORT
      LAYER M4 ;
      RECT 383.265 0.0 383.595 301.205 ;
      END
    PORT
      LAYER M4 ;
      RECT 386.025 0.0 386.355 301.205 ;
      END
    PORT
      LAYER M4 ;
      RECT 388.225 0.0 388.555 301.205 ;
      END
    PORT
      LAYER M4 ;
      RECT 390.985 0.0 391.315 301.205 ;
      END
    PORT
      LAYER M4 ;
      RECT 393.185 0.0 393.515 301.205 ;
      END
    PORT
      LAYER M4 ;
      RECT 395.945 0.0 396.275 301.205 ;
      END
    PORT
      LAYER M4 ;
      RECT 398.145 0.0 398.475 301.205 ;
      END
    PORT
      LAYER M4 ;
      RECT 400.905 0.0 401.235 301.205 ;
      END
    PORT
      LAYER M4 ;
      RECT 403.105 0.0 403.435 301.205 ;
      END
    PORT
      LAYER M4 ;
      RECT 405.865 0.0 406.195 301.205 ;
      END
    PORT
      LAYER M4 ;
      RECT 408.065 0.0 408.395 301.205 ;
      END
    PORT
      LAYER M4 ;
      RECT 410.825 0.0 411.155 301.205 ;
      END
    PORT
      LAYER M4 ;
      RECT 413.025 0.0 413.355 301.205 ;
      END
    PORT
      LAYER M4 ;
      RECT 415.785 0.0 416.115 301.205 ;
      END
    PORT
      LAYER M4 ;
      RECT 417.985 0.0 418.315 301.205 ;
      END
    PORT
      LAYER M4 ;
      RECT 420.745 0.0 421.075 301.205 ;
      END
    PORT
      LAYER M4 ;
      RECT 422.945 0.0 423.275 301.205 ;
      END
    PORT
      LAYER M4 ;
      RECT 425.705 0.0 426.035 301.205 ;
      END
    PORT
      LAYER M4 ;
      RECT 427.905 0.0 428.235 301.205 ;
      END
    PORT
      LAYER M4 ;
      RECT 430.665 0.0 430.995 301.205 ;
      END
    PORT
      LAYER M4 ;
      RECT 432.865 0.0 433.195 301.205 ;
      END
    PORT
      LAYER M4 ;
      RECT 435.625 0.0 435.955 301.205 ;
      END
    PORT
      LAYER M4 ;
      RECT 437.825 0.0 438.155 301.205 ;
      END
    PORT
      LAYER M4 ;
      RECT 440.585 0.0 440.915 301.205 ;
      END
    PORT
      LAYER M4 ;
      RECT 442.785 0.0 443.115 301.205 ;
      END
    PORT
      LAYER M4 ;
      RECT 445.545 0.0 445.875 301.205 ;
      END
    PORT
      LAYER M4 ;
      RECT 447.745 0.0 448.075 301.205 ;
      END
    PORT
      LAYER M4 ;
      RECT 450.505 0.0 450.835 301.205 ;
      END
    PORT
      LAYER M4 ;
      RECT 452.705 0.0 453.035 301.205 ;
      END
    PORT
      LAYER M4 ;
      RECT 455.465 0.0 455.795 301.205 ;
      END
    PORT
      LAYER M4 ;
      RECT 457.665 0.0 457.995 301.205 ;
      END
    PORT
      LAYER M4 ;
      RECT 460.425 0.0 460.755 301.205 ;
      END
    PORT
      LAYER M4 ;
      RECT 462.625 0.0 462.955 301.205 ;
      END
    PORT
      LAYER M4 ;
      RECT 465.385 0.0 465.715 301.205 ;
      END
    PORT
      LAYER M4 ;
      RECT 467.585 0.0 467.915 301.205 ;
      END
    PORT
      LAYER M4 ;
      RECT 470.345 0.0 470.675 301.205 ;
      END
    PORT
      LAYER M4 ;
      RECT 472.545 0.0 472.875 301.205 ;
      END
    PORT
      LAYER M4 ;
      RECT 475.305 0.0 475.635 301.205 ;
      END
    PORT
      LAYER M4 ;
      RECT 477.505 0.0 477.835 301.205 ;
      END
    PORT
      LAYER M4 ;
      RECT 480.265 0.0 480.595 301.205 ;
      END
    PORT
      LAYER M4 ;
      RECT 482.465 0.0 482.795 301.205 ;
      END
    PORT
      LAYER M4 ;
      RECT 485.225 0.0 485.555 301.205 ;
      END
    PORT
      LAYER M4 ;
      RECT 487.425 0.0 487.755 301.205 ;
      END
    PORT
      LAYER M4 ;
      RECT 490.185 0.0 490.515 301.205 ;
      END
    PORT
      LAYER M4 ;
      RECT 492.385 0.0 492.715 301.205 ;
      END
    PORT
      LAYER M4 ;
      RECT 495.145 0.0 495.475 301.205 ;
      END
    PORT
      LAYER M4 ;
      RECT 497.345 0.0 497.675 301.205 ;
      END
    PORT
      LAYER M4 ;
      RECT 500.105 0.0 500.435 301.205 ;
      END
    PORT
      LAYER M4 ;
      RECT 502.305 0.0 502.635 301.205 ;
      END
    PORT
      LAYER M4 ;
      RECT 505.065 0.0 505.395 301.205 ;
      END
    PORT
      LAYER M4 ;
      RECT 507.265 0.0 507.595 301.205 ;
      END
    PORT
      LAYER M4 ;
      RECT 510.025 0.0 510.355 301.205 ;
      END
    PORT
      LAYER M4 ;
      RECT 512.225 0.0 512.555 301.205 ;
      END
    PORT
      LAYER M4 ;
      RECT 514.985 0.0 515.315 301.205 ;
      END
    PORT
      LAYER M4 ;
      RECT 517.185 0.0 517.515 301.205 ;
      END
    PORT
      LAYER M4 ;
      RECT 519.945 0.0 520.275 301.205 ;
      END
    PORT
      LAYER M4 ;
      RECT 522.145 0.0 522.475 301.205 ;
      END
    PORT
      LAYER M4 ;
      RECT 524.905 0.0 525.235 301.205 ;
      END
    PORT
      LAYER M4 ;
      RECT 527.105 0.0 527.435 301.205 ;
      END
    PORT
      LAYER M4 ;
      RECT 529.865 0.0 530.195 301.205 ;
      END
    PORT
      LAYER M4 ;
      RECT 532.065 0.0 532.395 301.205 ;
      END
    PORT
      LAYER M4 ;
      RECT 534.825 0.0 535.155 301.205 ;
      END
    PORT
      LAYER M4 ;
      RECT 537.025 0.0 537.355 301.205 ;
      END
    PORT
      LAYER M4 ;
      RECT 539.785 0.0 540.115 301.205 ;
      END
    PORT
      LAYER M4 ;
      RECT 541.985 0.0 542.315 301.205 ;
      END
    PORT
      LAYER M4 ;
      RECT 544.745 0.0 545.075 301.205 ;
      END
    PORT
      LAYER M4 ;
      RECT 546.945 0.0 547.275 301.205 ;
      END
    PORT
      LAYER M4 ;
      RECT 549.705 0.0 550.035 301.205 ;
      END
    PORT
      LAYER M4 ;
      RECT 551.905 0.0 552.235 301.205 ;
      END
    PORT
      LAYER M4 ;
      RECT 554.665 0.0 554.995 301.205 ;
      END
    PORT
      LAYER M4 ;
      RECT 556.865 0.0 557.195 301.205 ;
      END
    PORT
      LAYER M4 ;
      RECT 559.625 0.0 559.955 301.205 ;
      END
    PORT
      LAYER M4 ;
      RECT 561.825 0.0 562.155 301.205 ;
      END
    PORT
      LAYER M4 ;
      RECT 564.585 0.0 564.915 301.205 ;
      END
    PORT
      LAYER M4 ;
      RECT 566.785 0.0 567.115 301.205 ;
      END
    PORT
      LAYER M4 ;
      RECT 569.545 0.0 569.875 301.205 ;
      END
    PORT
      LAYER M4 ;
      RECT 571.745 0.0 572.075 301.205 ;
      END
    PORT
      LAYER M4 ;
      RECT 574.505 0.0 574.835 301.205 ;
      END
    PORT
      LAYER M4 ;
      RECT 576.705 0.0 577.035 301.205 ;
      END
    PORT
      LAYER M4 ;
      RECT 579.465 0.0 579.795 301.205 ;
      END
    PORT
      LAYER M4 ;
      RECT 581.665 0.0 581.995 301.205 ;
      END
    PORT
      LAYER M4 ;
      RECT 584.425 0.0 584.755 301.205 ;
      END
    PORT
      LAYER M4 ;
      RECT 586.625 0.0 586.955 301.205 ;
      END
    PORT
      LAYER M4 ;
      RECT 589.385 0.0 589.715 301.205 ;
      END
    PORT
      LAYER M4 ;
      RECT 591.585 0.0 591.915 301.205 ;
      END
    PORT
      LAYER M4 ;
      RECT 594.345 0.0 594.675 301.205 ;
      END
    PORT
      LAYER M4 ;
      RECT 596.545 0.0 596.875 301.205 ;
      END
    PORT
      LAYER M4 ;
      RECT 599.305 0.0 599.635 301.205 ;
      END
    PORT
      LAYER M4 ;
      RECT 601.505 0.0 601.835 301.205 ;
      END
    PORT
      LAYER M4 ;
      RECT 604.265 0.0 604.595 301.205 ;
      END
    PORT
      LAYER M4 ;
      RECT 606.465 0.0 606.795 301.205 ;
      END
    PORT
      LAYER M4 ;
      RECT 609.225 0.0 609.555 301.205 ;
      END
    PORT
      LAYER M4 ;
      RECT 611.425 0.0 611.755 301.205 ;
      END
    PORT
      LAYER M4 ;
      RECT 614.185 0.0 614.515 301.205 ;
      END
    PORT
      LAYER M4 ;
      RECT 616.385 0.0 616.715 301.205 ;
      END
    PORT
      LAYER M4 ;
      RECT 619.145 0.0 619.475 301.205 ;
      END
    PORT
      LAYER M4 ;
      RECT 621.345 0.0 621.675 301.205 ;
      END
    PORT
      LAYER M4 ;
      RECT 624.105 0.0 624.435 301.205 ;
      END
    PORT
      LAYER M4 ;
      RECT 626.305 0.0 626.635 301.205 ;
      END
    PORT
      LAYER M4 ;
      RECT 629.065 0.0 629.395 301.205 ;
      END
    PORT
      LAYER M4 ;
      RECT 631.265 0.0 631.595 301.205 ;
      END
    PORT
      LAYER M4 ;
      RECT 634.025 0.0 634.355 301.205 ;
      END
    PORT
      LAYER M4 ;
      RECT 636.225 0.0 636.555 301.205 ;
      END
    PORT
      LAYER M4 ;
      RECT 638.985 0.0 639.315 301.205 ;
      END
    PORT
      LAYER M4 ;
      RECT 641.185 0.0 641.515 301.205 ;
      END
    PORT
      LAYER M4 ;
      RECT 643.945 0.0 644.275 301.205 ;
      END
    PORT
      LAYER M4 ;
      RECT 646.145 0.0 646.475 301.205 ;
      END
    PORT
      LAYER M4 ;
      RECT 648.905 0.0 649.235 301.205 ;
      END
    PORT
      LAYER M4 ;
      RECT 651.105 0.0 651.435 301.205 ;
      END
    PORT
      LAYER M4 ;
      RECT 653.865 0.0 654.195 301.205 ;
      END
    PORT
      LAYER M4 ;
      RECT 656.065 0.0 656.395 301.205 ;
      END
    PORT
      LAYER M4 ;
      RECT 658.825 0.0 659.155 301.205 ;
      END
    PORT
      LAYER M4 ;
      RECT 661.025 0.0 661.355 301.205 ;
      END
    PORT
      LAYER M4 ;
      RECT 663.785 0.0 664.115 301.205 ;
      END
    PORT
      LAYER M4 ;
      RECT 665.985 0.0 666.315 301.205 ;
      END
    PORT
      LAYER M4 ;
      RECT 668.745 0.0 669.075 301.205 ;
      END
    PORT
      LAYER M4 ;
      RECT 670.945 0.0 671.275 301.205 ;
      END
    PORT
      LAYER M4 ;
      RECT 673.705 0.0 674.035 301.205 ;
      END
    PORT
      LAYER M4 ;
      RECT 675.905 0.0 676.235 301.205 ;
      END
    PORT
      LAYER M4 ;
      RECT 678.665 0.0 678.995 301.205 ;
      END
    PORT
      LAYER M4 ;
      RECT 680.865 0.0 681.195 301.205 ;
      END
    PORT
      LAYER M4 ;
      RECT 682.79 0.0 683.1 301.205 ;
      END
    END VSSE
  OBS
    #otc obstructions
    LAYER M1 DESIGNRULEWIDTH 0.1 ;
    RECT 674.475 0.0 683.61 0.48 ;
    RECT 673.085 0.0 673.675 0.48 ;
    RECT 654.635 0.0 672.635 0.48 ;
    RECT 653.245 0.0 653.835 0.48 ;
    RECT 634.795 0.0 652.795 0.48 ;
    RECT 633.405 0.0 633.995 0.48 ;
    RECT 614.955 0.0 632.955 0.48 ;
    RECT 613.565 0.0 614.155 0.48 ;
    RECT 595.115 0.0 613.115 0.48 ;
    RECT 593.725 0.0 594.315 0.48 ;
    RECT 575.275 0.0 593.275 0.48 ;
    RECT 573.885 0.0 574.475 0.48 ;
    RECT 555.435 0.0 573.435 0.48 ;
    RECT 554.045 0.0 554.635 0.48 ;
    RECT 535.595 0.0 553.595 0.48 ;
    RECT 534.205 0.0 534.795 0.48 ;
    RECT 515.755 0.0 533.755 0.48 ;
    RECT 514.365 0.0 514.955 0.48 ;
    RECT 495.915 0.0 513.915 0.48 ;
    RECT 494.525 0.0 495.115 0.48 ;
    RECT 476.075 0.0 494.075 0.48 ;
    RECT 474.685 0.0 475.275 0.48 ;
    RECT 456.235 0.0 474.235 0.48 ;
    RECT 454.845 0.0 455.435 0.48 ;
    RECT 436.395 0.0 454.395 0.48 ;
    RECT 435.005 0.0 435.595 0.48 ;
    RECT 416.555 0.0 434.555 0.48 ;
    RECT 415.165 0.0 415.755 0.48 ;
    RECT 396.715 0.0 414.715 0.48 ;
    RECT 395.325 0.0 395.915 0.48 ;
    RECT 376.875 0.0 394.875 0.48 ;
    RECT 375.485 0.0 376.075 0.48 ;
    RECT 361.785 0.0 375.035 0.48 ;
    RECT 358.58 0.0 360.915 0.48 ;
    RECT 357.28 0.0 358.13 0.48 ;
    RECT 356.13 0.0 356.83 0.48 ;
    RECT 354.95 0.0 355.68 0.48 ;
    RECT 351.315 0.0 354.5 0.48 ;
    RECT 350.72 0.0 350.865 0.48 ;
    RECT 348.65 0.0 350.27 0.48 ;
    RECT 346.575 0.0 348.2 0.48 ;
    RECT 341.59 0.0 345.745 0.48 ;
    RECT 337.135 0.0 340.605 0.48 ;
    RECT 336.3 0.0 336.685 0.48 ;
    RECT 331.885 0.0 335.85 0.48 ;
    RECT 328.015 0.0 331.02 0.48 ;
    RECT 326.84 0.0 327.565 0.48 ;
    RECT 325.615 0.0 326.39 0.48 ;
    RECT 322.56 0.0 325.165 0.48 ;
    RECT 308.575 0.0 321.36 0.48 ;
    RECT 307.535 0.0 308.125 0.48 ;
    RECT 288.735 0.0 306.735 0.48 ;
    RECT 287.695 0.0 288.285 0.48 ;
    RECT 268.895 0.0 286.895 0.48 ;
    RECT 267.855 0.0 268.445 0.48 ;
    RECT 249.055 0.0 267.055 0.48 ;
    RECT 248.015 0.0 248.605 0.48 ;
    RECT 229.215 0.0 247.215 0.48 ;
    RECT 228.175 0.0 228.765 0.48 ;
    RECT 209.375 0.0 227.375 0.48 ;
    RECT 208.335 0.0 208.925 0.48 ;
    RECT 189.535 0.0 207.535 0.48 ;
    RECT 188.495 0.0 189.085 0.48 ;
    RECT 169.695 0.0 187.695 0.48 ;
    RECT 168.655 0.0 169.245 0.48 ;
    RECT 149.855 0.0 167.855 0.48 ;
    RECT 148.815 0.0 149.405 0.48 ;
    RECT 130.015 0.0 148.015 0.48 ;
    RECT 128.975 0.0 129.565 0.48 ;
    RECT 110.175 0.0 128.175 0.48 ;
    RECT 109.135 0.0 109.725 0.48 ;
    RECT 90.335 0.0 108.335 0.48 ;
    RECT 89.295 0.0 89.885 0.48 ;
    RECT 70.495 0.0 88.495 0.48 ;
    RECT 69.455 0.0 70.045 0.48 ;
    RECT 50.655 0.0 68.655 0.48 ;
    RECT 49.615 0.0 50.205 0.48 ;
    RECT 30.815 0.0 48.815 0.48 ;
    RECT 29.775 0.0 30.365 0.48 ;
    RECT 10.975 0.0 28.975 0.48 ;
    RECT 9.935 0.0 10.525 0.48 ;
    RECT 0.0 0.0 9.135 0.48 ;
    RECT 0.0 0.48 683.61 301.205 ;
    LAYER VIA1 ;
    RECT 0.0 0.0 683.61 301.205 ;
    LAYER M2 DESIGNRULEWIDTH 0.1 ;
    RECT 674.475 0.0 683.61 0.48 ;
    RECT 673.085 0.0 673.675 0.48 ;
    RECT 654.635 0.0 672.635 0.48 ;
    RECT 653.245 0.0 653.835 0.48 ;
    RECT 634.795 0.0 652.795 0.48 ;
    RECT 633.405 0.0 633.995 0.48 ;
    RECT 614.955 0.0 632.955 0.48 ;
    RECT 613.565 0.0 614.155 0.48 ;
    RECT 595.115 0.0 613.115 0.48 ;
    RECT 593.725 0.0 594.315 0.48 ;
    RECT 575.275 0.0 593.275 0.48 ;
    RECT 573.885 0.0 574.475 0.48 ;
    RECT 555.435 0.0 573.435 0.48 ;
    RECT 554.045 0.0 554.635 0.48 ;
    RECT 535.595 0.0 553.595 0.48 ;
    RECT 534.205 0.0 534.795 0.48 ;
    RECT 515.755 0.0 533.755 0.48 ;
    RECT 514.365 0.0 514.955 0.48 ;
    RECT 495.915 0.0 513.915 0.48 ;
    RECT 494.525 0.0 495.115 0.48 ;
    RECT 476.075 0.0 494.075 0.48 ;
    RECT 474.685 0.0 475.275 0.48 ;
    RECT 456.235 0.0 474.235 0.48 ;
    RECT 454.845 0.0 455.435 0.48 ;
    RECT 436.395 0.0 454.395 0.48 ;
    RECT 435.005 0.0 435.595 0.48 ;
    RECT 416.555 0.0 434.555 0.48 ;
    RECT 415.165 0.0 415.755 0.48 ;
    RECT 396.715 0.0 414.715 0.48 ;
    RECT 395.325 0.0 395.915 0.48 ;
    RECT 376.875 0.0 394.875 0.48 ;
    RECT 375.485 0.0 376.075 0.48 ;
    RECT 361.785 0.0 375.035 0.48 ;
    RECT 358.58 0.0 360.915 0.48 ;
    RECT 357.28 0.0 358.13 0.48 ;
    RECT 356.13 0.0 356.83 0.48 ;
    RECT 354.95 0.0 355.68 0.48 ;
    RECT 351.315 0.0 354.5 0.48 ;
    RECT 350.72 0.0 350.865 0.48 ;
    RECT 348.65 0.0 350.27 0.48 ;
    RECT 346.575 0.0 348.2 0.48 ;
    RECT 341.59 0.0 345.745 0.48 ;
    RECT 337.135 0.0 340.605 0.48 ;
    RECT 336.3 0.0 336.685 0.48 ;
    RECT 331.885 0.0 335.85 0.48 ;
    RECT 328.015 0.0 331.02 0.48 ;
    RECT 326.84 0.0 327.565 0.48 ;
    RECT 325.615 0.0 326.39 0.48 ;
    RECT 322.56 0.0 325.165 0.48 ;
    RECT 308.575 0.0 321.36 0.48 ;
    RECT 307.535 0.0 308.125 0.48 ;
    RECT 288.735 0.0 306.735 0.48 ;
    RECT 287.695 0.0 288.285 0.48 ;
    RECT 268.895 0.0 286.895 0.48 ;
    RECT 267.855 0.0 268.445 0.48 ;
    RECT 249.055 0.0 267.055 0.48 ;
    RECT 248.015 0.0 248.605 0.48 ;
    RECT 229.215 0.0 247.215 0.48 ;
    RECT 228.175 0.0 228.765 0.48 ;
    RECT 209.375 0.0 227.375 0.48 ;
    RECT 208.335 0.0 208.925 0.48 ;
    RECT 189.535 0.0 207.535 0.48 ;
    RECT 188.495 0.0 189.085 0.48 ;
    RECT 169.695 0.0 187.695 0.48 ;
    RECT 168.655 0.0 169.245 0.48 ;
    RECT 149.855 0.0 167.855 0.48 ;
    RECT 148.815 0.0 149.405 0.48 ;
    RECT 130.015 0.0 148.015 0.48 ;
    RECT 128.975 0.0 129.565 0.48 ;
    RECT 110.175 0.0 128.175 0.48 ;
    RECT 109.135 0.0 109.725 0.48 ;
    RECT 90.335 0.0 108.335 0.48 ;
    RECT 89.295 0.0 89.885 0.48 ;
    RECT 70.495 0.0 88.495 0.48 ;
    RECT 69.455 0.0 70.045 0.48 ;
    RECT 50.655 0.0 68.655 0.48 ;
    RECT 49.615 0.0 50.205 0.48 ;
    RECT 30.815 0.0 48.815 0.48 ;
    RECT 29.775 0.0 30.365 0.48 ;
    RECT 10.975 0.0 28.975 0.48 ;
    RECT 9.935 0.0 10.525 0.48 ;
    RECT 0.0 0.0 9.135 0.48 ;
    RECT 0.0 0.48 683.61 301.205 ;
    LAYER VIA2 ;
    RECT 0.0 0.0 683.61 301.205 ;
    LAYER M3 DESIGNRULEWIDTH 0.1 ;
    RECT 674.475 0.0 683.61 0.48 ;
    RECT 673.085 0.0 673.675 0.48 ;
    RECT 654.635 0.0 672.635 0.48 ;
    RECT 653.245 0.0 653.835 0.48 ;
    RECT 634.795 0.0 652.795 0.48 ;
    RECT 633.405 0.0 633.995 0.48 ;
    RECT 614.955 0.0 632.955 0.48 ;
    RECT 613.565 0.0 614.155 0.48 ;
    RECT 595.115 0.0 613.115 0.48 ;
    RECT 593.725 0.0 594.315 0.48 ;
    RECT 575.275 0.0 593.275 0.48 ;
    RECT 573.885 0.0 574.475 0.48 ;
    RECT 555.435 0.0 573.435 0.48 ;
    RECT 554.045 0.0 554.635 0.48 ;
    RECT 535.595 0.0 553.595 0.48 ;
    RECT 534.205 0.0 534.795 0.48 ;
    RECT 515.755 0.0 533.755 0.48 ;
    RECT 514.365 0.0 514.955 0.48 ;
    RECT 495.915 0.0 513.915 0.48 ;
    RECT 494.525 0.0 495.115 0.48 ;
    RECT 476.075 0.0 494.075 0.48 ;
    RECT 474.685 0.0 475.275 0.48 ;
    RECT 456.235 0.0 474.235 0.48 ;
    RECT 454.845 0.0 455.435 0.48 ;
    RECT 436.395 0.0 454.395 0.48 ;
    RECT 435.005 0.0 435.595 0.48 ;
    RECT 416.555 0.0 434.555 0.48 ;
    RECT 415.165 0.0 415.755 0.48 ;
    RECT 396.715 0.0 414.715 0.48 ;
    RECT 395.325 0.0 395.915 0.48 ;
    RECT 376.875 0.0 394.875 0.48 ;
    RECT 375.485 0.0 376.075 0.48 ;
    RECT 361.785 0.0 375.035 0.48 ;
    RECT 358.58 0.0 360.915 0.48 ;
    RECT 357.28 0.0 358.13 0.48 ;
    RECT 356.13 0.0 356.83 0.48 ;
    RECT 354.95 0.0 355.68 0.48 ;
    RECT 351.315 0.0 354.5 0.48 ;
    RECT 350.72 0.0 350.865 0.48 ;
    RECT 348.65 0.0 350.27 0.48 ;
    RECT 346.575 0.0 348.2 0.48 ;
    RECT 341.59 0.0 345.745 0.48 ;
    RECT 337.135 0.0 340.605 0.48 ;
    RECT 336.3 0.0 336.685 0.48 ;
    RECT 331.885 0.0 335.85 0.48 ;
    RECT 328.015 0.0 331.02 0.48 ;
    RECT 326.84 0.0 327.565 0.48 ;
    RECT 325.615 0.0 326.39 0.48 ;
    RECT 322.56 0.0 325.165 0.48 ;
    RECT 308.575 0.0 321.36 0.48 ;
    RECT 307.535 0.0 308.125 0.48 ;
    RECT 288.735 0.0 306.735 0.48 ;
    RECT 287.695 0.0 288.285 0.48 ;
    RECT 268.895 0.0 286.895 0.48 ;
    RECT 267.855 0.0 268.445 0.48 ;
    RECT 249.055 0.0 267.055 0.48 ;
    RECT 248.015 0.0 248.605 0.48 ;
    RECT 229.215 0.0 247.215 0.48 ;
    RECT 228.175 0.0 228.765 0.48 ;
    RECT 209.375 0.0 227.375 0.48 ;
    RECT 208.335 0.0 208.925 0.48 ;
    RECT 189.535 0.0 207.535 0.48 ;
    RECT 188.495 0.0 189.085 0.48 ;
    RECT 169.695 0.0 187.695 0.48 ;
    RECT 168.655 0.0 169.245 0.48 ;
    RECT 149.855 0.0 167.855 0.48 ;
    RECT 148.815 0.0 149.405 0.48 ;
    RECT 130.015 0.0 148.015 0.48 ;
    RECT 128.975 0.0 129.565 0.48 ;
    RECT 110.175 0.0 128.175 0.48 ;
    RECT 109.135 0.0 109.725 0.48 ;
    RECT 90.335 0.0 108.335 0.48 ;
    RECT 89.295 0.0 89.885 0.48 ;
    RECT 70.495 0.0 88.495 0.48 ;
    RECT 69.455 0.0 70.045 0.48 ;
    RECT 50.655 0.0 68.655 0.48 ;
    RECT 49.615 0.0 50.205 0.48 ;
    RECT 30.815 0.0 48.815 0.48 ;
    RECT 29.775 0.0 30.365 0.48 ;
    RECT 10.975 0.0 28.975 0.48 ;
    RECT 9.935 0.0 10.525 0.48 ;
    RECT 0.0 0.0 9.135 0.48 ;
    RECT 0.0 0.48 683.61 301.205 ;
    LAYER VIA3 ;
    RECT 0.0 0.0 683.61 301.205 ;
    LAYER M4 DESIGNRULEWIDTH 0.1 ;
    RECT 681.315 0.0 681.725 0.48 ;
    RECT 679.845 0.0 680.255 0.48 ;
    RECT 679.115 0.0 679.275 0.48 ;
    RECT 677.335 0.0 678.545 0.48 ;
    RECT 676.355 0.0 676.765 0.48 ;
    RECT 674.885 0.0 675.295 0.48 ;
    RECT 674.155 0.0 674.315 0.48 ;
    RECT 672.375 0.0 673.585 0.48 ;
    RECT 671.395 0.0 671.805 0.48 ;
    RECT 669.925 0.0 670.335 0.48 ;
    RECT 669.195 0.0 669.355 0.48 ;
    RECT 667.415 0.0 668.625 0.48 ;
    RECT 666.435 0.0 666.845 0.48 ;
    RECT 664.965 0.0 665.375 0.48 ;
    RECT 664.235 0.0 664.395 0.48 ;
    RECT 662.455 0.0 663.665 0.48 ;
    RECT 661.475 0.0 661.885 0.48 ;
    RECT 660.005 0.0 660.415 0.48 ;
    RECT 659.275 0.0 659.435 0.48 ;
    RECT 657.495 0.0 658.705 0.48 ;
    RECT 656.515 0.0 656.925 0.48 ;
    RECT 655.045 0.0 655.455 0.48 ;
    RECT 654.315 0.0 654.475 0.48 ;
    RECT 652.535 0.0 653.745 0.48 ;
    RECT 651.555 0.0 651.965 0.48 ;
    RECT 650.085 0.0 650.495 0.48 ;
    RECT 649.355 0.0 649.515 0.48 ;
    RECT 647.575 0.0 648.785 0.48 ;
    RECT 646.595 0.0 647.005 0.48 ;
    RECT 645.125 0.0 645.535 0.48 ;
    RECT 644.395 0.0 644.555 0.48 ;
    RECT 642.615 0.0 643.825 0.48 ;
    RECT 641.635 0.0 642.045 0.48 ;
    RECT 640.165 0.0 640.575 0.48 ;
    RECT 639.435 0.0 639.595 0.48 ;
    RECT 637.655 0.0 638.865 0.48 ;
    RECT 636.675 0.0 637.085 0.48 ;
    RECT 635.205 0.0 635.615 0.48 ;
    RECT 634.475 0.0 634.635 0.48 ;
    RECT 632.695 0.0 633.905 0.48 ;
    RECT 631.715 0.0 632.125 0.48 ;
    RECT 630.245 0.0 630.655 0.48 ;
    RECT 629.515 0.0 629.675 0.48 ;
    RECT 627.735 0.0 628.945 0.48 ;
    RECT 626.755 0.0 627.165 0.48 ;
    RECT 625.285 0.0 625.695 0.48 ;
    RECT 624.555 0.0 624.715 0.48 ;
    RECT 622.775 0.0 623.985 0.48 ;
    RECT 621.795 0.0 622.205 0.48 ;
    RECT 620.325 0.0 620.735 0.48 ;
    RECT 619.595 0.0 619.755 0.48 ;
    RECT 617.815 0.0 619.025 0.48 ;
    RECT 616.835 0.0 617.245 0.48 ;
    RECT 615.365 0.0 615.775 0.48 ;
    RECT 614.635 0.0 614.795 0.48 ;
    RECT 612.855 0.0 614.065 0.48 ;
    RECT 611.875 0.0 612.285 0.48 ;
    RECT 610.405 0.0 610.815 0.48 ;
    RECT 609.675 0.0 609.835 0.48 ;
    RECT 607.895 0.0 609.105 0.48 ;
    RECT 606.915 0.0 607.325 0.48 ;
    RECT 605.445 0.0 605.855 0.48 ;
    RECT 604.715 0.0 604.875 0.48 ;
    RECT 602.935 0.0 604.145 0.48 ;
    RECT 601.955 0.0 602.365 0.48 ;
    RECT 600.485 0.0 600.895 0.48 ;
    RECT 599.755 0.0 599.915 0.48 ;
    RECT 597.975 0.0 599.185 0.48 ;
    RECT 596.995 0.0 597.405 0.48 ;
    RECT 595.525 0.0 595.935 0.48 ;
    RECT 594.795 0.0 594.955 0.48 ;
    RECT 593.015 0.0 594.225 0.48 ;
    RECT 592.035 0.0 592.445 0.48 ;
    RECT 590.565 0.0 590.975 0.48 ;
    RECT 589.835 0.0 589.995 0.48 ;
    RECT 588.055 0.0 589.265 0.48 ;
    RECT 587.075 0.0 587.485 0.48 ;
    RECT 585.605 0.0 586.015 0.48 ;
    RECT 584.875 0.0 585.035 0.48 ;
    RECT 583.095 0.0 584.305 0.48 ;
    RECT 582.115 0.0 582.525 0.48 ;
    RECT 580.645 0.0 581.055 0.48 ;
    RECT 579.915 0.0 580.075 0.48 ;
    RECT 578.135 0.0 579.345 0.48 ;
    RECT 577.155 0.0 577.565 0.48 ;
    RECT 575.685 0.0 576.095 0.48 ;
    RECT 574.955 0.0 575.115 0.48 ;
    RECT 573.175 0.0 574.385 0.48 ;
    RECT 572.195 0.0 572.605 0.48 ;
    RECT 570.725 0.0 571.135 0.48 ;
    RECT 569.995 0.0 570.155 0.48 ;
    RECT 568.215 0.0 569.425 0.48 ;
    RECT 567.235 0.0 567.645 0.48 ;
    RECT 565.765 0.0 566.175 0.48 ;
    RECT 565.035 0.0 565.195 0.48 ;
    RECT 563.255 0.0 564.465 0.48 ;
    RECT 562.275 0.0 562.685 0.48 ;
    RECT 560.805 0.0 561.215 0.48 ;
    RECT 560.075 0.0 560.235 0.48 ;
    RECT 558.295 0.0 559.505 0.48 ;
    RECT 557.315 0.0 557.725 0.48 ;
    RECT 555.845 0.0 556.255 0.48 ;
    RECT 555.115 0.0 555.275 0.48 ;
    RECT 553.335 0.0 554.545 0.48 ;
    RECT 552.355 0.0 552.765 0.48 ;
    RECT 550.885 0.0 551.295 0.48 ;
    RECT 550.155 0.0 550.315 0.48 ;
    RECT 548.375 0.0 549.585 0.48 ;
    RECT 547.395 0.0 547.805 0.48 ;
    RECT 545.925 0.0 546.335 0.48 ;
    RECT 545.195 0.0 545.355 0.48 ;
    RECT 543.415 0.0 544.625 0.48 ;
    RECT 542.435 0.0 542.845 0.48 ;
    RECT 540.965 0.0 541.375 0.48 ;
    RECT 540.235 0.0 540.395 0.48 ;
    RECT 538.455 0.0 539.665 0.48 ;
    RECT 537.475 0.0 537.885 0.48 ;
    RECT 536.005 0.0 536.415 0.48 ;
    RECT 535.275 0.0 535.435 0.48 ;
    RECT 533.495 0.0 534.705 0.48 ;
    RECT 532.515 0.0 532.925 0.48 ;
    RECT 531.045 0.0 531.455 0.48 ;
    RECT 530.315 0.0 530.475 0.48 ;
    RECT 528.535 0.0 529.745 0.48 ;
    RECT 527.555 0.0 527.965 0.48 ;
    RECT 526.085 0.0 526.495 0.48 ;
    RECT 525.355 0.0 525.515 0.48 ;
    RECT 523.575 0.0 524.785 0.48 ;
    RECT 522.595 0.0 523.005 0.48 ;
    RECT 521.125 0.0 521.535 0.48 ;
    RECT 520.395 0.0 520.555 0.48 ;
    RECT 518.615 0.0 519.825 0.48 ;
    RECT 517.635 0.0 518.045 0.48 ;
    RECT 516.165 0.0 516.575 0.48 ;
    RECT 515.435 0.0 515.595 0.48 ;
    RECT 513.655 0.0 514.865 0.48 ;
    RECT 512.675 0.0 513.085 0.48 ;
    RECT 511.205 0.0 511.615 0.48 ;
    RECT 510.475 0.0 510.635 0.48 ;
    RECT 508.695 0.0 509.905 0.48 ;
    RECT 507.715 0.0 508.125 0.48 ;
    RECT 506.245 0.0 506.655 0.48 ;
    RECT 505.515 0.0 505.675 0.48 ;
    RECT 503.735 0.0 504.945 0.48 ;
    RECT 502.755 0.0 503.165 0.48 ;
    RECT 501.285 0.0 501.695 0.48 ;
    RECT 500.555 0.0 500.715 0.48 ;
    RECT 498.775 0.0 499.985 0.48 ;
    RECT 497.795 0.0 498.205 0.48 ;
    RECT 496.325 0.0 496.735 0.48 ;
    RECT 495.595 0.0 495.755 0.48 ;
    RECT 493.815 0.0 495.025 0.48 ;
    RECT 492.835 0.0 493.245 0.48 ;
    RECT 491.365 0.0 491.775 0.48 ;
    RECT 490.635 0.0 490.795 0.48 ;
    RECT 488.855 0.0 490.065 0.48 ;
    RECT 487.875 0.0 488.285 0.48 ;
    RECT 486.405 0.0 486.815 0.48 ;
    RECT 485.675 0.0 485.835 0.48 ;
    RECT 483.895 0.0 485.105 0.48 ;
    RECT 482.915 0.0 483.325 0.48 ;
    RECT 481.445 0.0 481.855 0.48 ;
    RECT 480.715 0.0 480.875 0.48 ;
    RECT 478.935 0.0 480.145 0.48 ;
    RECT 477.955 0.0 478.365 0.48 ;
    RECT 476.485 0.0 476.895 0.48 ;
    RECT 475.755 0.0 475.915 0.48 ;
    RECT 473.975 0.0 475.185 0.48 ;
    RECT 472.995 0.0 473.405 0.48 ;
    RECT 471.525 0.0 471.935 0.48 ;
    RECT 470.795 0.0 470.955 0.48 ;
    RECT 469.015 0.0 470.225 0.48 ;
    RECT 468.035 0.0 468.445 0.48 ;
    RECT 466.565 0.0 466.975 0.48 ;
    RECT 465.835 0.0 465.995 0.48 ;
    RECT 464.055 0.0 465.265 0.48 ;
    RECT 463.075 0.0 463.485 0.48 ;
    RECT 461.605 0.0 462.015 0.48 ;
    RECT 460.875 0.0 461.035 0.48 ;
    RECT 459.095 0.0 460.305 0.48 ;
    RECT 458.115 0.0 458.525 0.48 ;
    RECT 456.645 0.0 457.055 0.48 ;
    RECT 455.915 0.0 456.075 0.48 ;
    RECT 454.135 0.0 455.345 0.48 ;
    RECT 453.155 0.0 453.565 0.48 ;
    RECT 451.685 0.0 452.095 0.48 ;
    RECT 450.955 0.0 451.115 0.48 ;
    RECT 449.175 0.0 450.385 0.48 ;
    RECT 448.195 0.0 448.605 0.48 ;
    RECT 446.725 0.0 447.135 0.48 ;
    RECT 445.995 0.0 446.155 0.48 ;
    RECT 444.215 0.0 445.425 0.48 ;
    RECT 443.235 0.0 443.645 0.48 ;
    RECT 441.765 0.0 442.175 0.48 ;
    RECT 441.035 0.0 441.195 0.48 ;
    RECT 439.255 0.0 440.465 0.48 ;
    RECT 438.275 0.0 438.685 0.48 ;
    RECT 436.805 0.0 437.215 0.48 ;
    RECT 436.075 0.0 436.235 0.48 ;
    RECT 434.295 0.0 435.505 0.48 ;
    RECT 433.315 0.0 433.725 0.48 ;
    RECT 431.845 0.0 432.255 0.48 ;
    RECT 431.115 0.0 431.275 0.48 ;
    RECT 429.335 0.0 430.545 0.48 ;
    RECT 428.355 0.0 428.765 0.48 ;
    RECT 426.885 0.0 427.295 0.48 ;
    RECT 426.155 0.0 426.315 0.48 ;
    RECT 424.375 0.0 425.585 0.48 ;
    RECT 423.395 0.0 423.805 0.48 ;
    RECT 421.925 0.0 422.335 0.48 ;
    RECT 421.195 0.0 421.355 0.48 ;
    RECT 419.415 0.0 420.625 0.48 ;
    RECT 418.435 0.0 418.845 0.48 ;
    RECT 416.965 0.0 417.375 0.48 ;
    RECT 416.235 0.0 416.395 0.48 ;
    RECT 414.455 0.0 415.665 0.48 ;
    RECT 413.475 0.0 413.885 0.48 ;
    RECT 412.005 0.0 412.415 0.48 ;
    RECT 411.275 0.0 411.435 0.48 ;
    RECT 409.495 0.0 410.705 0.48 ;
    RECT 408.515 0.0 408.925 0.48 ;
    RECT 407.045 0.0 407.455 0.48 ;
    RECT 406.315 0.0 406.475 0.48 ;
    RECT 404.535 0.0 405.745 0.48 ;
    RECT 403.555 0.0 403.965 0.48 ;
    RECT 402.085 0.0 402.495 0.48 ;
    RECT 401.355 0.0 401.515 0.48 ;
    RECT 399.575 0.0 400.785 0.48 ;
    RECT 398.595 0.0 399.005 0.48 ;
    RECT 397.125 0.0 397.535 0.48 ;
    RECT 396.395 0.0 396.555 0.48 ;
    RECT 394.615 0.0 395.825 0.48 ;
    RECT 393.635 0.0 394.045 0.48 ;
    RECT 392.165 0.0 392.575 0.48 ;
    RECT 391.435 0.0 391.595 0.48 ;
    RECT 389.655 0.0 390.865 0.48 ;
    RECT 388.675 0.0 389.085 0.48 ;
    RECT 387.205 0.0 387.615 0.48 ;
    RECT 386.475 0.0 386.635 0.48 ;
    RECT 384.695 0.0 385.905 0.48 ;
    RECT 383.715 0.0 384.125 0.48 ;
    RECT 382.245 0.0 382.655 0.48 ;
    RECT 381.515 0.0 381.675 0.48 ;
    RECT 379.735 0.0 380.945 0.48 ;
    RECT 378.755 0.0 379.165 0.48 ;
    RECT 377.285 0.0 377.695 0.48 ;
    RECT 376.555 0.0 376.715 0.48 ;
    RECT 374.775 0.0 375.985 0.48 ;
    RECT 373.795 0.0 374.205 0.48 ;
    RECT 372.325 0.0 372.735 0.48 ;
    RECT 371.595 0.0 371.755 0.48 ;
    RECT 369.815 0.0 371.025 0.48 ;
    RECT 368.835 0.0 369.245 0.48 ;
    RECT 367.365 0.0 367.775 0.48 ;
    RECT 366.635 0.0 366.795 0.48 ;
    RECT 364.88 0.0 366.065 0.48 ;
    RECT 360.04 0.0 362.28 0.48 ;
    RECT 357.475 0.0 357.67 0.48 ;
    RECT 356.87 0.0 357.095 0.48 ;
    RECT 355.675 0.0 356.33 0.48 ;
    RECT 354.26 0.0 355.135 0.48 ;
    RECT 353.41 0.0 353.88 0.48 ;
    RECT 352.025 0.0 352.41 0.48 ;
    RECT 350.205 0.0 351.165 0.48 ;
    RECT 348.26 0.0 349.565 0.48 ;
    RECT 346.625 0.0 347.8 0.48 ;
    RECT 343.225 0.0 346.245 0.48 ;
    RECT 341.865 0.0 342.615 0.48 ;
    RECT 337.945 0.0 341.225 0.48 ;
    RECT 336.105 0.0 337.485 0.48 ;
    RECT 335.395 0.0 335.565 0.48 ;
    RECT 334.085 0.0 334.855 0.48 ;
    RECT 332.595 0.0 333.635 0.48 ;
    RECT 331.655 0.0 332.055 0.48 ;
    RECT 330.93 0.0 331.115 0.48 ;
    RECT 329.405 0.0 329.975 0.48 ;
    RECT 328.64 0.0 328.955 0.48 ;
    RECT 327.025 0.0 327.565 0.48 ;
    RECT 326.24 0.0 326.405 0.48 ;
    RECT 325.555 0.0 325.78 0.48 ;
    RECT 321.655 0.0 322.92 0.48 ;
    RECT 320.805 0.0 321.015 0.48 ;
    RECT 317.545 0.0 318.73 0.48 ;
    RECT 316.815 0.0 316.975 0.48 ;
    RECT 315.835 0.0 316.245 0.48 ;
    RECT 314.365 0.0 314.775 0.48 ;
    RECT 312.585 0.0 313.795 0.48 ;
    RECT 311.855 0.0 312.015 0.48 ;
    RECT 310.875 0.0 311.285 0.48 ;
    RECT 309.405 0.0 309.815 0.48 ;
    RECT 307.625 0.0 308.835 0.48 ;
    RECT 306.895 0.0 307.055 0.48 ;
    RECT 305.915 0.0 306.325 0.48 ;
    RECT 304.445 0.0 304.855 0.48 ;
    RECT 302.665 0.0 303.875 0.48 ;
    RECT 301.935 0.0 302.095 0.48 ;
    RECT 300.955 0.0 301.365 0.48 ;
    RECT 299.485 0.0 299.895 0.48 ;
    RECT 297.705 0.0 298.915 0.48 ;
    RECT 296.975 0.0 297.135 0.48 ;
    RECT 295.995 0.0 296.405 0.48 ;
    RECT 294.525 0.0 294.935 0.48 ;
    RECT 292.745 0.0 293.955 0.48 ;
    RECT 292.015 0.0 292.175 0.48 ;
    RECT 291.035 0.0 291.445 0.48 ;
    RECT 289.565 0.0 289.975 0.48 ;
    RECT 287.785 0.0 288.995 0.48 ;
    RECT 287.055 0.0 287.215 0.48 ;
    RECT 286.075 0.0 286.485 0.48 ;
    RECT 284.605 0.0 285.015 0.48 ;
    RECT 282.825 0.0 284.035 0.48 ;
    RECT 282.095 0.0 282.255 0.48 ;
    RECT 281.115 0.0 281.525 0.48 ;
    RECT 279.645 0.0 280.055 0.48 ;
    RECT 277.865 0.0 279.075 0.48 ;
    RECT 277.135 0.0 277.295 0.48 ;
    RECT 276.155 0.0 276.565 0.48 ;
    RECT 274.685 0.0 275.095 0.48 ;
    RECT 272.905 0.0 274.115 0.48 ;
    RECT 272.175 0.0 272.335 0.48 ;
    RECT 271.195 0.0 271.605 0.48 ;
    RECT 269.725 0.0 270.135 0.48 ;
    RECT 267.945 0.0 269.155 0.48 ;
    RECT 267.215 0.0 267.375 0.48 ;
    RECT 266.235 0.0 266.645 0.48 ;
    RECT 264.765 0.0 265.175 0.48 ;
    RECT 262.985 0.0 264.195 0.48 ;
    RECT 262.255 0.0 262.415 0.48 ;
    RECT 261.275 0.0 261.685 0.48 ;
    RECT 259.805 0.0 260.215 0.48 ;
    RECT 258.025 0.0 259.235 0.48 ;
    RECT 257.295 0.0 257.455 0.48 ;
    RECT 256.315 0.0 256.725 0.48 ;
    RECT 254.845 0.0 255.255 0.48 ;
    RECT 253.065 0.0 254.275 0.48 ;
    RECT 252.335 0.0 252.495 0.48 ;
    RECT 251.355 0.0 251.765 0.48 ;
    RECT 249.885 0.0 250.295 0.48 ;
    RECT 248.105 0.0 249.315 0.48 ;
    RECT 247.375 0.0 247.535 0.48 ;
    RECT 246.395 0.0 246.805 0.48 ;
    RECT 244.925 0.0 245.335 0.48 ;
    RECT 243.145 0.0 244.355 0.48 ;
    RECT 242.415 0.0 242.575 0.48 ;
    RECT 241.435 0.0 241.845 0.48 ;
    RECT 239.965 0.0 240.375 0.48 ;
    RECT 238.185 0.0 239.395 0.48 ;
    RECT 237.455 0.0 237.615 0.48 ;
    RECT 236.475 0.0 236.885 0.48 ;
    RECT 235.005 0.0 235.415 0.48 ;
    RECT 233.225 0.0 234.435 0.48 ;
    RECT 232.495 0.0 232.655 0.48 ;
    RECT 231.515 0.0 231.925 0.48 ;
    RECT 230.045 0.0 230.455 0.48 ;
    RECT 228.265 0.0 229.475 0.48 ;
    RECT 227.535 0.0 227.695 0.48 ;
    RECT 226.555 0.0 226.965 0.48 ;
    RECT 225.085 0.0 225.495 0.48 ;
    RECT 223.305 0.0 224.515 0.48 ;
    RECT 222.575 0.0 222.735 0.48 ;
    RECT 221.595 0.0 222.005 0.48 ;
    RECT 220.125 0.0 220.535 0.48 ;
    RECT 218.345 0.0 219.555 0.48 ;
    RECT 217.615 0.0 217.775 0.48 ;
    RECT 216.635 0.0 217.045 0.48 ;
    RECT 215.165 0.0 215.575 0.48 ;
    RECT 213.385 0.0 214.595 0.48 ;
    RECT 212.655 0.0 212.815 0.48 ;
    RECT 211.675 0.0 212.085 0.48 ;
    RECT 210.205 0.0 210.615 0.48 ;
    RECT 208.425 0.0 209.635 0.48 ;
    RECT 207.695 0.0 207.855 0.48 ;
    RECT 206.715 0.0 207.125 0.48 ;
    RECT 205.245 0.0 205.655 0.48 ;
    RECT 203.465 0.0 204.675 0.48 ;
    RECT 202.735 0.0 202.895 0.48 ;
    RECT 201.755 0.0 202.165 0.48 ;
    RECT 200.285 0.0 200.695 0.48 ;
    RECT 198.505 0.0 199.715 0.48 ;
    RECT 197.775 0.0 197.935 0.48 ;
    RECT 196.795 0.0 197.205 0.48 ;
    RECT 195.325 0.0 195.735 0.48 ;
    RECT 193.545 0.0 194.755 0.48 ;
    RECT 192.815 0.0 192.975 0.48 ;
    RECT 191.835 0.0 192.245 0.48 ;
    RECT 190.365 0.0 190.775 0.48 ;
    RECT 188.585 0.0 189.795 0.48 ;
    RECT 187.855 0.0 188.015 0.48 ;
    RECT 186.875 0.0 187.285 0.48 ;
    RECT 185.405 0.0 185.815 0.48 ;
    RECT 183.625 0.0 184.835 0.48 ;
    RECT 182.895 0.0 183.055 0.48 ;
    RECT 181.915 0.0 182.325 0.48 ;
    RECT 180.445 0.0 180.855 0.48 ;
    RECT 178.665 0.0 179.875 0.48 ;
    RECT 177.935 0.0 178.095 0.48 ;
    RECT 176.955 0.0 177.365 0.48 ;
    RECT 175.485 0.0 175.895 0.48 ;
    RECT 173.705 0.0 174.915 0.48 ;
    RECT 172.975 0.0 173.135 0.48 ;
    RECT 171.995 0.0 172.405 0.48 ;
    RECT 170.525 0.0 170.935 0.48 ;
    RECT 168.745 0.0 169.955 0.48 ;
    RECT 168.015 0.0 168.175 0.48 ;
    RECT 167.035 0.0 167.445 0.48 ;
    RECT 165.565 0.0 165.975 0.48 ;
    RECT 163.785 0.0 164.995 0.48 ;
    RECT 163.055 0.0 163.215 0.48 ;
    RECT 162.075 0.0 162.485 0.48 ;
    RECT 160.605 0.0 161.015 0.48 ;
    RECT 158.825 0.0 160.035 0.48 ;
    RECT 158.095 0.0 158.255 0.48 ;
    RECT 157.115 0.0 157.525 0.48 ;
    RECT 155.645 0.0 156.055 0.48 ;
    RECT 153.865 0.0 155.075 0.48 ;
    RECT 153.135 0.0 153.295 0.48 ;
    RECT 152.155 0.0 152.565 0.48 ;
    RECT 150.685 0.0 151.095 0.48 ;
    RECT 148.905 0.0 150.115 0.48 ;
    RECT 148.175 0.0 148.335 0.48 ;
    RECT 147.195 0.0 147.605 0.48 ;
    RECT 145.725 0.0 146.135 0.48 ;
    RECT 143.945 0.0 145.155 0.48 ;
    RECT 143.215 0.0 143.375 0.48 ;
    RECT 142.235 0.0 142.645 0.48 ;
    RECT 140.765 0.0 141.175 0.48 ;
    RECT 138.985 0.0 140.195 0.48 ;
    RECT 138.255 0.0 138.415 0.48 ;
    RECT 137.275 0.0 137.685 0.48 ;
    RECT 135.805 0.0 136.215 0.48 ;
    RECT 134.025 0.0 135.235 0.48 ;
    RECT 133.295 0.0 133.455 0.48 ;
    RECT 132.315 0.0 132.725 0.48 ;
    RECT 130.845 0.0 131.255 0.48 ;
    RECT 129.065 0.0 130.275 0.48 ;
    RECT 128.335 0.0 128.495 0.48 ;
    RECT 127.355 0.0 127.765 0.48 ;
    RECT 125.885 0.0 126.295 0.48 ;
    RECT 124.105 0.0 125.315 0.48 ;
    RECT 123.375 0.0 123.535 0.48 ;
    RECT 122.395 0.0 122.805 0.48 ;
    RECT 120.925 0.0 121.335 0.48 ;
    RECT 119.145 0.0 120.355 0.48 ;
    RECT 118.415 0.0 118.575 0.48 ;
    RECT 117.435 0.0 117.845 0.48 ;
    RECT 115.965 0.0 116.375 0.48 ;
    RECT 114.185 0.0 115.395 0.48 ;
    RECT 113.455 0.0 113.615 0.48 ;
    RECT 112.475 0.0 112.885 0.48 ;
    RECT 111.005 0.0 111.415 0.48 ;
    RECT 109.225 0.0 110.435 0.48 ;
    RECT 108.495 0.0 108.655 0.48 ;
    RECT 107.515 0.0 107.925 0.48 ;
    RECT 106.045 0.0 106.455 0.48 ;
    RECT 104.265 0.0 105.475 0.48 ;
    RECT 103.535 0.0 103.695 0.48 ;
    RECT 102.555 0.0 102.965 0.48 ;
    RECT 101.085 0.0 101.495 0.48 ;
    RECT 99.305 0.0 100.515 0.48 ;
    RECT 98.575 0.0 98.735 0.48 ;
    RECT 97.595 0.0 98.005 0.48 ;
    RECT 96.125 0.0 96.535 0.48 ;
    RECT 94.345 0.0 95.555 0.48 ;
    RECT 93.615 0.0 93.775 0.48 ;
    RECT 92.635 0.0 93.045 0.48 ;
    RECT 91.165 0.0 91.575 0.48 ;
    RECT 89.385 0.0 90.595 0.48 ;
    RECT 88.655 0.0 88.815 0.48 ;
    RECT 87.675 0.0 88.085 0.48 ;
    RECT 86.205 0.0 86.615 0.48 ;
    RECT 84.425 0.0 85.635 0.48 ;
    RECT 83.695 0.0 83.855 0.48 ;
    RECT 82.715 0.0 83.125 0.48 ;
    RECT 81.245 0.0 81.655 0.48 ;
    RECT 79.465 0.0 80.675 0.48 ;
    RECT 78.735 0.0 78.895 0.48 ;
    RECT 77.755 0.0 78.165 0.48 ;
    RECT 76.285 0.0 76.695 0.48 ;
    RECT 74.505 0.0 75.715 0.48 ;
    RECT 73.775 0.0 73.935 0.48 ;
    RECT 72.795 0.0 73.205 0.48 ;
    RECT 71.325 0.0 71.735 0.48 ;
    RECT 69.545 0.0 70.755 0.48 ;
    RECT 68.815 0.0 68.975 0.48 ;
    RECT 67.835 0.0 68.245 0.48 ;
    RECT 66.365 0.0 66.775 0.48 ;
    RECT 64.585 0.0 65.795 0.48 ;
    RECT 63.855 0.0 64.015 0.48 ;
    RECT 62.875 0.0 63.285 0.48 ;
    RECT 61.405 0.0 61.815 0.48 ;
    RECT 59.625 0.0 60.835 0.48 ;
    RECT 58.895 0.0 59.055 0.48 ;
    RECT 57.915 0.0 58.325 0.48 ;
    RECT 56.445 0.0 56.855 0.48 ;
    RECT 54.665 0.0 55.875 0.48 ;
    RECT 53.935 0.0 54.095 0.48 ;
    RECT 52.955 0.0 53.365 0.48 ;
    RECT 51.485 0.0 51.895 0.48 ;
    RECT 49.705 0.0 50.915 0.48 ;
    RECT 48.975 0.0 49.135 0.48 ;
    RECT 47.995 0.0 48.405 0.48 ;
    RECT 46.525 0.0 46.935 0.48 ;
    RECT 44.745 0.0 45.955 0.48 ;
    RECT 44.015 0.0 44.175 0.48 ;
    RECT 43.035 0.0 43.445 0.48 ;
    RECT 41.565 0.0 41.975 0.48 ;
    RECT 39.785 0.0 40.995 0.48 ;
    RECT 39.055 0.0 39.215 0.48 ;
    RECT 38.075 0.0 38.485 0.48 ;
    RECT 36.605 0.0 37.015 0.48 ;
    RECT 34.825 0.0 36.035 0.48 ;
    RECT 34.095 0.0 34.255 0.48 ;
    RECT 33.115 0.0 33.525 0.48 ;
    RECT 31.645 0.0 32.055 0.48 ;
    RECT 29.865 0.0 31.075 0.48 ;
    RECT 29.135 0.0 29.295 0.48 ;
    RECT 28.155 0.0 28.565 0.48 ;
    RECT 26.685 0.0 27.095 0.48 ;
    RECT 24.905 0.0 26.115 0.48 ;
    RECT 24.175 0.0 24.335 0.48 ;
    RECT 23.195 0.0 23.605 0.48 ;
    RECT 21.725 0.0 22.135 0.48 ;
    RECT 19.945 0.0 21.155 0.48 ;
    RECT 19.215 0.0 19.375 0.48 ;
    RECT 18.235 0.0 18.645 0.48 ;
    RECT 16.765 0.0 17.175 0.48 ;
    RECT 14.985 0.0 16.195 0.48 ;
    RECT 14.255 0.0 14.415 0.48 ;
    RECT 13.275 0.0 13.685 0.48 ;
    RECT 11.805 0.0 12.215 0.48 ;
    RECT 10.025 0.0 11.235 0.48 ;
    RECT 9.295 0.0 9.455 0.48 ;
    RECT 8.315 0.0 8.725 0.48 ;
    RECT 6.845 0.0 7.255 0.48 ;
    RECT 5.065 0.0 6.275 0.48 ;
    RECT 4.335 0.0 4.495 0.48 ;
    RECT 3.355 0.0 3.765 0.48 ;
    RECT 1.885 0.0 2.295 0.48 ;
    RECT 681.315 0.48 681.725 301.205 ;
    RECT 679.845 0.48 680.255 301.205 ;
    RECT 679.115 0.48 679.275 301.205 ;
    RECT 677.335 0.48 678.545 301.205 ;
    RECT 676.355 0.48 676.765 301.205 ;
    RECT 674.885 0.48 675.295 301.205 ;
    RECT 674.155 0.48 674.315 301.205 ;
    RECT 672.375 0.48 673.585 301.205 ;
    RECT 671.395 0.48 671.805 301.205 ;
    RECT 669.925 0.48 670.335 301.205 ;
    RECT 669.195 0.48 669.355 301.205 ;
    RECT 667.415 0.48 668.625 301.205 ;
    RECT 666.435 0.48 666.845 301.205 ;
    RECT 664.965 0.48 665.375 301.205 ;
    RECT 664.235 0.48 664.395 301.205 ;
    RECT 662.455 0.48 663.665 301.205 ;
    RECT 661.475 0.48 661.885 301.205 ;
    RECT 660.005 0.48 660.415 301.205 ;
    RECT 659.275 0.48 659.435 301.205 ;
    RECT 657.495 0.48 658.705 301.205 ;
    RECT 656.515 0.48 656.925 301.205 ;
    RECT 655.045 0.48 655.455 301.205 ;
    RECT 654.315 0.48 654.475 301.205 ;
    RECT 652.535 0.48 653.745 301.205 ;
    RECT 651.555 0.48 651.965 301.205 ;
    RECT 650.085 0.48 650.495 301.205 ;
    RECT 649.355 0.48 649.515 301.205 ;
    RECT 647.575 0.48 648.785 301.205 ;
    RECT 646.595 0.48 647.005 301.205 ;
    RECT 645.125 0.48 645.535 301.205 ;
    RECT 644.395 0.48 644.555 301.205 ;
    RECT 642.615 0.48 643.825 301.205 ;
    RECT 641.635 0.48 642.045 301.205 ;
    RECT 640.165 0.48 640.575 301.205 ;
    RECT 639.435 0.48 639.595 301.205 ;
    RECT 637.655 0.48 638.865 301.205 ;
    RECT 636.675 0.48 637.085 301.205 ;
    RECT 635.205 0.48 635.615 301.205 ;
    RECT 634.475 0.48 634.635 301.205 ;
    RECT 632.695 0.48 633.905 301.205 ;
    RECT 631.715 0.48 632.125 301.205 ;
    RECT 630.245 0.48 630.655 301.205 ;
    RECT 629.515 0.48 629.675 301.205 ;
    RECT 627.735 0.48 628.945 301.205 ;
    RECT 626.755 0.48 627.165 301.205 ;
    RECT 625.285 0.48 625.695 301.205 ;
    RECT 624.555 0.48 624.715 301.205 ;
    RECT 622.775 0.48 623.985 301.205 ;
    RECT 621.795 0.48 622.205 301.205 ;
    RECT 620.325 0.48 620.735 301.205 ;
    RECT 619.595 0.48 619.755 301.205 ;
    RECT 617.815 0.48 619.025 301.205 ;
    RECT 616.835 0.48 617.245 301.205 ;
    RECT 615.365 0.48 615.775 301.205 ;
    RECT 614.635 0.48 614.795 301.205 ;
    RECT 612.855 0.48 614.065 301.205 ;
    RECT 611.875 0.48 612.285 301.205 ;
    RECT 610.405 0.48 610.815 301.205 ;
    RECT 609.675 0.48 609.835 301.205 ;
    RECT 607.895 0.48 609.105 301.205 ;
    RECT 606.915 0.48 607.325 301.205 ;
    RECT 605.445 0.48 605.855 301.205 ;
    RECT 604.715 0.48 604.875 301.205 ;
    RECT 602.935 0.48 604.145 301.205 ;
    RECT 601.955 0.48 602.365 301.205 ;
    RECT 600.485 0.48 600.895 301.205 ;
    RECT 599.755 0.48 599.915 301.205 ;
    RECT 597.975 0.48 599.185 301.205 ;
    RECT 596.995 0.48 597.405 301.205 ;
    RECT 595.525 0.48 595.935 301.205 ;
    RECT 594.795 0.48 594.955 301.205 ;
    RECT 593.015 0.48 594.225 301.205 ;
    RECT 592.035 0.48 592.445 301.205 ;
    RECT 590.565 0.48 590.975 301.205 ;
    RECT 589.835 0.48 589.995 301.205 ;
    RECT 588.055 0.48 589.265 301.205 ;
    RECT 587.075 0.48 587.485 301.205 ;
    RECT 585.605 0.48 586.015 301.205 ;
    RECT 584.875 0.48 585.035 301.205 ;
    RECT 583.095 0.48 584.305 301.205 ;
    RECT 582.115 0.48 582.525 301.205 ;
    RECT 580.645 0.48 581.055 301.205 ;
    RECT 579.915 0.48 580.075 301.205 ;
    RECT 578.135 0.48 579.345 301.205 ;
    RECT 577.155 0.48 577.565 301.205 ;
    RECT 575.685 0.48 576.095 301.205 ;
    RECT 574.955 0.48 575.115 301.205 ;
    RECT 573.175 0.48 574.385 301.205 ;
    RECT 572.195 0.48 572.605 301.205 ;
    RECT 570.725 0.48 571.135 301.205 ;
    RECT 569.995 0.48 570.155 301.205 ;
    RECT 568.215 0.48 569.425 301.205 ;
    RECT 567.235 0.48 567.645 301.205 ;
    RECT 565.765 0.48 566.175 301.205 ;
    RECT 565.035 0.48 565.195 301.205 ;
    RECT 563.255 0.48 564.465 301.205 ;
    RECT 562.275 0.48 562.685 301.205 ;
    RECT 560.805 0.48 561.215 301.205 ;
    RECT 560.075 0.48 560.235 301.205 ;
    RECT 558.295 0.48 559.505 301.205 ;
    RECT 557.315 0.48 557.725 301.205 ;
    RECT 555.845 0.48 556.255 301.205 ;
    RECT 555.115 0.48 555.275 301.205 ;
    RECT 553.335 0.48 554.545 301.205 ;
    RECT 552.355 0.48 552.765 301.205 ;
    RECT 550.885 0.48 551.295 301.205 ;
    RECT 550.155 0.48 550.315 301.205 ;
    RECT 548.375 0.48 549.585 301.205 ;
    RECT 547.395 0.48 547.805 301.205 ;
    RECT 545.925 0.48 546.335 301.205 ;
    RECT 545.195 0.48 545.355 301.205 ;
    RECT 543.415 0.48 544.625 301.205 ;
    RECT 542.435 0.48 542.845 301.205 ;
    RECT 540.965 0.48 541.375 301.205 ;
    RECT 540.235 0.48 540.395 301.205 ;
    RECT 538.455 0.48 539.665 301.205 ;
    RECT 537.475 0.48 537.885 301.205 ;
    RECT 536.005 0.48 536.415 301.205 ;
    RECT 535.275 0.48 535.435 301.205 ;
    RECT 533.495 0.48 534.705 301.205 ;
    RECT 532.515 0.48 532.925 301.205 ;
    RECT 531.045 0.48 531.455 301.205 ;
    RECT 530.315 0.48 530.475 301.205 ;
    RECT 528.535 0.48 529.745 301.205 ;
    RECT 527.555 0.48 527.965 301.205 ;
    RECT 526.085 0.48 526.495 301.205 ;
    RECT 525.355 0.48 525.515 301.205 ;
    RECT 523.575 0.48 524.785 301.205 ;
    RECT 522.595 0.48 523.005 301.205 ;
    RECT 521.125 0.48 521.535 301.205 ;
    RECT 520.395 0.48 520.555 301.205 ;
    RECT 518.615 0.48 519.825 301.205 ;
    RECT 517.635 0.48 518.045 301.205 ;
    RECT 516.165 0.48 516.575 301.205 ;
    RECT 515.435 0.48 515.595 301.205 ;
    RECT 513.655 0.48 514.865 301.205 ;
    RECT 512.675 0.48 513.085 301.205 ;
    RECT 511.205 0.48 511.615 301.205 ;
    RECT 510.475 0.48 510.635 301.205 ;
    RECT 508.695 0.48 509.905 301.205 ;
    RECT 507.715 0.48 508.125 301.205 ;
    RECT 506.245 0.48 506.655 301.205 ;
    RECT 505.515 0.48 505.675 301.205 ;
    RECT 503.735 0.48 504.945 301.205 ;
    RECT 502.755 0.48 503.165 301.205 ;
    RECT 501.285 0.48 501.695 301.205 ;
    RECT 500.555 0.48 500.715 301.205 ;
    RECT 498.775 0.48 499.985 301.205 ;
    RECT 497.795 0.48 498.205 301.205 ;
    RECT 496.325 0.48 496.735 301.205 ;
    RECT 495.595 0.48 495.755 301.205 ;
    RECT 493.815 0.48 495.025 301.205 ;
    RECT 492.835 0.48 493.245 301.205 ;
    RECT 491.365 0.48 491.775 301.205 ;
    RECT 490.635 0.48 490.795 301.205 ;
    RECT 488.855 0.48 490.065 301.205 ;
    RECT 487.875 0.48 488.285 301.205 ;
    RECT 486.405 0.48 486.815 301.205 ;
    RECT 485.675 0.48 485.835 301.205 ;
    RECT 483.895 0.48 485.105 301.205 ;
    RECT 482.915 0.48 483.325 301.205 ;
    RECT 481.445 0.48 481.855 301.205 ;
    RECT 480.715 0.48 480.875 301.205 ;
    RECT 478.935 0.48 480.145 301.205 ;
    RECT 477.955 0.48 478.365 301.205 ;
    RECT 476.485 0.48 476.895 301.205 ;
    RECT 475.755 0.48 475.915 301.205 ;
    RECT 473.975 0.48 475.185 301.205 ;
    RECT 472.995 0.48 473.405 301.205 ;
    RECT 471.525 0.48 471.935 301.205 ;
    RECT 470.795 0.48 470.955 301.205 ;
    RECT 469.015 0.48 470.225 301.205 ;
    RECT 468.035 0.48 468.445 301.205 ;
    RECT 466.565 0.48 466.975 301.205 ;
    RECT 465.835 0.48 465.995 301.205 ;
    RECT 464.055 0.48 465.265 301.205 ;
    RECT 463.075 0.48 463.485 301.205 ;
    RECT 461.605 0.48 462.015 301.205 ;
    RECT 460.875 0.48 461.035 301.205 ;
    RECT 459.095 0.48 460.305 301.205 ;
    RECT 458.115 0.48 458.525 301.205 ;
    RECT 456.645 0.48 457.055 301.205 ;
    RECT 455.915 0.48 456.075 301.205 ;
    RECT 454.135 0.48 455.345 301.205 ;
    RECT 453.155 0.48 453.565 301.205 ;
    RECT 451.685 0.48 452.095 301.205 ;
    RECT 450.955 0.48 451.115 301.205 ;
    RECT 449.175 0.48 450.385 301.205 ;
    RECT 448.195 0.48 448.605 301.205 ;
    RECT 446.725 0.48 447.135 301.205 ;
    RECT 445.995 0.48 446.155 301.205 ;
    RECT 444.215 0.48 445.425 301.205 ;
    RECT 443.235 0.48 443.645 301.205 ;
    RECT 441.765 0.48 442.175 301.205 ;
    RECT 441.035 0.48 441.195 301.205 ;
    RECT 439.255 0.48 440.465 301.205 ;
    RECT 438.275 0.48 438.685 301.205 ;
    RECT 436.805 0.48 437.215 301.205 ;
    RECT 436.075 0.48 436.235 301.205 ;
    RECT 434.295 0.48 435.505 301.205 ;
    RECT 433.315 0.48 433.725 301.205 ;
    RECT 431.845 0.48 432.255 301.205 ;
    RECT 431.115 0.48 431.275 301.205 ;
    RECT 429.335 0.48 430.545 301.205 ;
    RECT 428.355 0.48 428.765 301.205 ;
    RECT 426.885 0.48 427.295 301.205 ;
    RECT 426.155 0.48 426.315 301.205 ;
    RECT 424.375 0.48 425.585 301.205 ;
    RECT 423.395 0.48 423.805 301.205 ;
    RECT 421.925 0.48 422.335 301.205 ;
    RECT 421.195 0.48 421.355 301.205 ;
    RECT 419.415 0.48 420.625 301.205 ;
    RECT 418.435 0.48 418.845 301.205 ;
    RECT 416.965 0.48 417.375 301.205 ;
    RECT 416.235 0.48 416.395 301.205 ;
    RECT 414.455 0.48 415.665 301.205 ;
    RECT 413.475 0.48 413.885 301.205 ;
    RECT 412.005 0.48 412.415 301.205 ;
    RECT 411.275 0.48 411.435 301.205 ;
    RECT 409.495 0.48 410.705 301.205 ;
    RECT 408.515 0.48 408.925 301.205 ;
    RECT 407.045 0.48 407.455 301.205 ;
    RECT 406.315 0.48 406.475 301.205 ;
    RECT 404.535 0.48 405.745 301.205 ;
    RECT 403.555 0.48 403.965 301.205 ;
    RECT 402.085 0.48 402.495 301.205 ;
    RECT 401.355 0.48 401.515 301.205 ;
    RECT 399.575 0.48 400.785 301.205 ;
    RECT 398.595 0.48 399.005 301.205 ;
    RECT 397.125 0.48 397.535 301.205 ;
    RECT 396.395 0.48 396.555 301.205 ;
    RECT 394.615 0.48 395.825 301.205 ;
    RECT 393.635 0.48 394.045 301.205 ;
    RECT 392.165 0.48 392.575 301.205 ;
    RECT 391.435 0.48 391.595 301.205 ;
    RECT 389.655 0.48 390.865 301.205 ;
    RECT 388.675 0.48 389.085 301.205 ;
    RECT 387.205 0.48 387.615 301.205 ;
    RECT 386.475 0.48 386.635 301.205 ;
    RECT 384.695 0.48 385.905 301.205 ;
    RECT 383.715 0.48 384.125 301.205 ;
    RECT 382.245 0.48 382.655 301.205 ;
    RECT 381.515 0.48 381.675 301.205 ;
    RECT 379.735 0.48 380.945 301.205 ;
    RECT 378.755 0.48 379.165 301.205 ;
    RECT 377.285 0.48 377.695 301.205 ;
    RECT 376.555 0.48 376.715 301.205 ;
    RECT 374.775 0.48 375.985 301.205 ;
    RECT 373.795 0.48 374.205 301.205 ;
    RECT 372.325 0.48 372.735 301.205 ;
    RECT 371.595 0.48 371.755 301.205 ;
    RECT 369.815 0.48 371.025 301.205 ;
    RECT 368.835 0.48 369.245 301.205 ;
    RECT 367.365 0.48 367.775 301.205 ;
    RECT 366.635 0.48 366.795 301.205 ;
    RECT 364.88 0.48 366.065 301.205 ;
    RECT 360.04 0.48 362.28 301.205 ;
    RECT 357.475 0.48 357.67 301.205 ;
    RECT 356.87 0.48 357.095 301.205 ;
    RECT 355.675 0.48 356.33 301.205 ;
    RECT 354.26 0.48 355.135 301.205 ;
    RECT 353.41 0.48 353.88 301.205 ;
    RECT 352.025 0.48 352.41 301.205 ;
    RECT 350.205 0.48 351.165 301.205 ;
    RECT 348.26 0.48 349.565 301.205 ;
    RECT 346.625 0.48 347.8 301.205 ;
    RECT 343.225 0.48 346.245 301.205 ;
    RECT 341.865 0.48 342.615 301.205 ;
    RECT 337.945 0.48 341.225 301.205 ;
    RECT 336.105 0.48 337.485 301.205 ;
    RECT 335.395 0.48 335.565 301.205 ;
    RECT 334.085 0.48 334.855 301.205 ;
    RECT 332.595 0.48 333.635 301.205 ;
    RECT 331.655 0.48 332.055 301.205 ;
    RECT 330.93 0.48 331.115 301.205 ;
    RECT 329.405 0.48 329.975 301.205 ;
    RECT 328.64 0.48 328.955 301.205 ;
    RECT 327.025 0.48 328.0 301.205 ;
    RECT 326.24 0.48 326.405 301.205 ;
    RECT 325.555 0.48 325.78 301.205 ;
    RECT 321.655 0.48 322.92 301.205 ;
    RECT 320.805 0.48 321.015 301.205 ;
    RECT 317.545 0.48 318.73 301.205 ;
    RECT 316.815 0.48 316.975 301.205 ;
    RECT 315.835 0.48 316.245 301.205 ;
    RECT 314.365 0.48 314.775 301.205 ;
    RECT 312.585 0.48 313.795 301.205 ;
    RECT 311.855 0.48 312.015 301.205 ;
    RECT 310.875 0.48 311.285 301.205 ;
    RECT 309.405 0.48 309.815 301.205 ;
    RECT 307.625 0.48 308.835 301.205 ;
    RECT 306.895 0.48 307.055 301.205 ;
    RECT 305.915 0.48 306.325 301.205 ;
    RECT 304.445 0.48 304.855 301.205 ;
    RECT 302.665 0.48 303.875 301.205 ;
    RECT 301.935 0.48 302.095 301.205 ;
    RECT 300.955 0.48 301.365 301.205 ;
    RECT 299.485 0.48 299.895 301.205 ;
    RECT 297.705 0.48 298.915 301.205 ;
    RECT 296.975 0.48 297.135 301.205 ;
    RECT 295.995 0.48 296.405 301.205 ;
    RECT 294.525 0.48 294.935 301.205 ;
    RECT 292.745 0.48 293.955 301.205 ;
    RECT 292.015 0.48 292.175 301.205 ;
    RECT 291.035 0.48 291.445 301.205 ;
    RECT 289.565 0.48 289.975 301.205 ;
    RECT 287.785 0.48 288.995 301.205 ;
    RECT 287.055 0.48 287.215 301.205 ;
    RECT 286.075 0.48 286.485 301.205 ;
    RECT 284.605 0.48 285.015 301.205 ;
    RECT 282.825 0.48 284.035 301.205 ;
    RECT 282.095 0.48 282.255 301.205 ;
    RECT 281.115 0.48 281.525 301.205 ;
    RECT 279.645 0.48 280.055 301.205 ;
    RECT 277.865 0.48 279.075 301.205 ;
    RECT 277.135 0.48 277.295 301.205 ;
    RECT 276.155 0.48 276.565 301.205 ;
    RECT 274.685 0.48 275.095 301.205 ;
    RECT 272.905 0.48 274.115 301.205 ;
    RECT 272.175 0.48 272.335 301.205 ;
    RECT 271.195 0.48 271.605 301.205 ;
    RECT 269.725 0.48 270.135 301.205 ;
    RECT 267.945 0.48 269.155 301.205 ;
    RECT 267.215 0.48 267.375 301.205 ;
    RECT 266.235 0.48 266.645 301.205 ;
    RECT 264.765 0.48 265.175 301.205 ;
    RECT 262.985 0.48 264.195 301.205 ;
    RECT 262.255 0.48 262.415 301.205 ;
    RECT 261.275 0.48 261.685 301.205 ;
    RECT 259.805 0.48 260.215 301.205 ;
    RECT 258.025 0.48 259.235 301.205 ;
    RECT 257.295 0.48 257.455 301.205 ;
    RECT 256.315 0.48 256.725 301.205 ;
    RECT 254.845 0.48 255.255 301.205 ;
    RECT 253.065 0.48 254.275 301.205 ;
    RECT 252.335 0.48 252.495 301.205 ;
    RECT 251.355 0.48 251.765 301.205 ;
    RECT 249.885 0.48 250.295 301.205 ;
    RECT 248.105 0.48 249.315 301.205 ;
    RECT 247.375 0.48 247.535 301.205 ;
    RECT 246.395 0.48 246.805 301.205 ;
    RECT 244.925 0.48 245.335 301.205 ;
    RECT 243.145 0.48 244.355 301.205 ;
    RECT 242.415 0.48 242.575 301.205 ;
    RECT 241.435 0.48 241.845 301.205 ;
    RECT 239.965 0.48 240.375 301.205 ;
    RECT 238.185 0.48 239.395 301.205 ;
    RECT 237.455 0.48 237.615 301.205 ;
    RECT 236.475 0.48 236.885 301.205 ;
    RECT 235.005 0.48 235.415 301.205 ;
    RECT 233.225 0.48 234.435 301.205 ;
    RECT 232.495 0.48 232.655 301.205 ;
    RECT 231.515 0.48 231.925 301.205 ;
    RECT 230.045 0.48 230.455 301.205 ;
    RECT 228.265 0.48 229.475 301.205 ;
    RECT 227.535 0.48 227.695 301.205 ;
    RECT 226.555 0.48 226.965 301.205 ;
    RECT 225.085 0.48 225.495 301.205 ;
    RECT 223.305 0.48 224.515 301.205 ;
    RECT 222.575 0.48 222.735 301.205 ;
    RECT 221.595 0.48 222.005 301.205 ;
    RECT 220.125 0.48 220.535 301.205 ;
    RECT 218.345 0.48 219.555 301.205 ;
    RECT 217.615 0.48 217.775 301.205 ;
    RECT 216.635 0.48 217.045 301.205 ;
    RECT 215.165 0.48 215.575 301.205 ;
    RECT 213.385 0.48 214.595 301.205 ;
    RECT 212.655 0.48 212.815 301.205 ;
    RECT 211.675 0.48 212.085 301.205 ;
    RECT 210.205 0.48 210.615 301.205 ;
    RECT 208.425 0.48 209.635 301.205 ;
    RECT 207.695 0.48 207.855 301.205 ;
    RECT 206.715 0.48 207.125 301.205 ;
    RECT 205.245 0.48 205.655 301.205 ;
    RECT 203.465 0.48 204.675 301.205 ;
    RECT 202.735 0.48 202.895 301.205 ;
    RECT 201.755 0.48 202.165 301.205 ;
    RECT 200.285 0.48 200.695 301.205 ;
    RECT 198.505 0.48 199.715 301.205 ;
    RECT 197.775 0.48 197.935 301.205 ;
    RECT 196.795 0.48 197.205 301.205 ;
    RECT 195.325 0.48 195.735 301.205 ;
    RECT 193.545 0.48 194.755 301.205 ;
    RECT 192.815 0.48 192.975 301.205 ;
    RECT 191.835 0.48 192.245 301.205 ;
    RECT 190.365 0.48 190.775 301.205 ;
    RECT 188.585 0.48 189.795 301.205 ;
    RECT 187.855 0.48 188.015 301.205 ;
    RECT 186.875 0.48 187.285 301.205 ;
    RECT 185.405 0.48 185.815 301.205 ;
    RECT 183.625 0.48 184.835 301.205 ;
    RECT 182.895 0.48 183.055 301.205 ;
    RECT 181.915 0.48 182.325 301.205 ;
    RECT 180.445 0.48 180.855 301.205 ;
    RECT 178.665 0.48 179.875 301.205 ;
    RECT 177.935 0.48 178.095 301.205 ;
    RECT 176.955 0.48 177.365 301.205 ;
    RECT 175.485 0.48 175.895 301.205 ;
    RECT 173.705 0.48 174.915 301.205 ;
    RECT 172.975 0.48 173.135 301.205 ;
    RECT 171.995 0.48 172.405 301.205 ;
    RECT 170.525 0.48 170.935 301.205 ;
    RECT 168.745 0.48 169.955 301.205 ;
    RECT 168.015 0.48 168.175 301.205 ;
    RECT 167.035 0.48 167.445 301.205 ;
    RECT 165.565 0.48 165.975 301.205 ;
    RECT 163.785 0.48 164.995 301.205 ;
    RECT 163.055 0.48 163.215 301.205 ;
    RECT 162.075 0.48 162.485 301.205 ;
    RECT 160.605 0.48 161.015 301.205 ;
    RECT 158.825 0.48 160.035 301.205 ;
    RECT 158.095 0.48 158.255 301.205 ;
    RECT 157.115 0.48 157.525 301.205 ;
    RECT 155.645 0.48 156.055 301.205 ;
    RECT 153.865 0.48 155.075 301.205 ;
    RECT 153.135 0.48 153.295 301.205 ;
    RECT 152.155 0.48 152.565 301.205 ;
    RECT 150.685 0.48 151.095 301.205 ;
    RECT 148.905 0.48 150.115 301.205 ;
    RECT 148.175 0.48 148.335 301.205 ;
    RECT 147.195 0.48 147.605 301.205 ;
    RECT 145.725 0.48 146.135 301.205 ;
    RECT 143.945 0.48 145.155 301.205 ;
    RECT 143.215 0.48 143.375 301.205 ;
    RECT 142.235 0.48 142.645 301.205 ;
    RECT 140.765 0.48 141.175 301.205 ;
    RECT 138.985 0.48 140.195 301.205 ;
    RECT 138.255 0.48 138.415 301.205 ;
    RECT 137.275 0.48 137.685 301.205 ;
    RECT 135.805 0.48 136.215 301.205 ;
    RECT 134.025 0.48 135.235 301.205 ;
    RECT 133.295 0.48 133.455 301.205 ;
    RECT 132.315 0.48 132.725 301.205 ;
    RECT 130.845 0.48 131.255 301.205 ;
    RECT 129.065 0.48 130.275 301.205 ;
    RECT 128.335 0.48 128.495 301.205 ;
    RECT 127.355 0.48 127.765 301.205 ;
    RECT 125.885 0.48 126.295 301.205 ;
    RECT 124.105 0.48 125.315 301.205 ;
    RECT 123.375 0.48 123.535 301.205 ;
    RECT 122.395 0.48 122.805 301.205 ;
    RECT 120.925 0.48 121.335 301.205 ;
    RECT 119.145 0.48 120.355 301.205 ;
    RECT 118.415 0.48 118.575 301.205 ;
    RECT 117.435 0.48 117.845 301.205 ;
    RECT 115.965 0.48 116.375 301.205 ;
    RECT 114.185 0.48 115.395 301.205 ;
    RECT 113.455 0.48 113.615 301.205 ;
    RECT 112.475 0.48 112.885 301.205 ;
    RECT 111.005 0.48 111.415 301.205 ;
    RECT 109.225 0.48 110.435 301.205 ;
    RECT 108.495 0.48 108.655 301.205 ;
    RECT 107.515 0.48 107.925 301.205 ;
    RECT 106.045 0.48 106.455 301.205 ;
    RECT 104.265 0.48 105.475 301.205 ;
    RECT 103.535 0.48 103.695 301.205 ;
    RECT 102.555 0.48 102.965 301.205 ;
    RECT 101.085 0.48 101.495 301.205 ;
    RECT 99.305 0.48 100.515 301.205 ;
    RECT 98.575 0.48 98.735 301.205 ;
    RECT 97.595 0.48 98.005 301.205 ;
    RECT 96.125 0.48 96.535 301.205 ;
    RECT 94.345 0.48 95.555 301.205 ;
    RECT 93.615 0.48 93.775 301.205 ;
    RECT 92.635 0.48 93.045 301.205 ;
    RECT 91.165 0.48 91.575 301.205 ;
    RECT 89.385 0.48 90.595 301.205 ;
    RECT 88.655 0.48 88.815 301.205 ;
    RECT 87.675 0.48 88.085 301.205 ;
    RECT 86.205 0.48 86.615 301.205 ;
    RECT 84.425 0.48 85.635 301.205 ;
    RECT 83.695 0.48 83.855 301.205 ;
    RECT 82.715 0.48 83.125 301.205 ;
    RECT 81.245 0.48 81.655 301.205 ;
    RECT 79.465 0.48 80.675 301.205 ;
    RECT 78.735 0.48 78.895 301.205 ;
    RECT 77.755 0.48 78.165 301.205 ;
    RECT 76.285 0.48 76.695 301.205 ;
    RECT 74.505 0.48 75.715 301.205 ;
    RECT 73.775 0.48 73.935 301.205 ;
    RECT 72.795 0.48 73.205 301.205 ;
    RECT 71.325 0.48 71.735 301.205 ;
    RECT 69.545 0.48 70.755 301.205 ;
    RECT 68.815 0.48 68.975 301.205 ;
    RECT 67.835 0.48 68.245 301.205 ;
    RECT 66.365 0.48 66.775 301.205 ;
    RECT 64.585 0.48 65.795 301.205 ;
    RECT 63.855 0.48 64.015 301.205 ;
    RECT 62.875 0.48 63.285 301.205 ;
    RECT 61.405 0.48 61.815 301.205 ;
    RECT 59.625 0.48 60.835 301.205 ;
    RECT 58.895 0.48 59.055 301.205 ;
    RECT 57.915 0.48 58.325 301.205 ;
    RECT 56.445 0.48 56.855 301.205 ;
    RECT 54.665 0.48 55.875 301.205 ;
    RECT 53.935 0.48 54.095 301.205 ;
    RECT 52.955 0.48 53.365 301.205 ;
    RECT 51.485 0.48 51.895 301.205 ;
    RECT 49.705 0.48 50.915 301.205 ;
    RECT 48.975 0.48 49.135 301.205 ;
    RECT 47.995 0.48 48.405 301.205 ;
    RECT 46.525 0.48 46.935 301.205 ;
    RECT 44.745 0.48 45.955 301.205 ;
    RECT 44.015 0.48 44.175 301.205 ;
    RECT 43.035 0.48 43.445 301.205 ;
    RECT 41.565 0.48 41.975 301.205 ;
    RECT 39.785 0.48 40.995 301.205 ;
    RECT 39.055 0.48 39.215 301.205 ;
    RECT 38.075 0.48 38.485 301.205 ;
    RECT 36.605 0.48 37.015 301.205 ;
    RECT 34.825 0.48 36.035 301.205 ;
    RECT 34.095 0.48 34.255 301.205 ;
    RECT 33.115 0.48 33.525 301.205 ;
    RECT 31.645 0.48 32.055 301.205 ;
    RECT 29.865 0.48 31.075 301.205 ;
    RECT 29.135 0.48 29.295 301.205 ;
    RECT 28.155 0.48 28.565 301.205 ;
    RECT 26.685 0.48 27.095 301.205 ;
    RECT 24.905 0.48 26.115 301.205 ;
    RECT 24.175 0.48 24.335 301.205 ;
    RECT 23.195 0.48 23.605 301.205 ;
    RECT 21.725 0.48 22.135 301.205 ;
    RECT 19.945 0.48 21.155 301.205 ;
    RECT 19.215 0.48 19.375 301.205 ;
    RECT 18.235 0.48 18.645 301.205 ;
    RECT 16.765 0.48 17.175 301.205 ;
    RECT 14.985 0.48 16.195 301.205 ;
    RECT 14.255 0.48 14.415 301.205 ;
    RECT 13.275 0.48 13.685 301.205 ;
    RECT 11.805 0.48 12.215 301.205 ;
    RECT 10.025 0.48 11.235 301.205 ;
    RECT 9.295 0.48 9.455 301.205 ;
    RECT 8.315 0.48 8.725 301.205 ;
    RECT 6.845 0.48 7.255 301.205 ;
    RECT 5.065 0.48 6.275 301.205 ;
    RECT 4.335 0.48 4.495 301.205 ;
    RECT 3.355 0.48 3.765 301.205 ;
    RECT 1.885 0.48 2.295 301.205 ;
    END
  END sp_hse_8192_m16

END LIBRARY

